# Generated deterministically by seda-macro-lef-normalizer-v1; recipe orfs-ng45-fakeram-metal3-coupledl2-pg-v1.
VERSION 5.8 ;
BUSBITCHARS "[]" ;
DIVIDERCHAR "/" ;

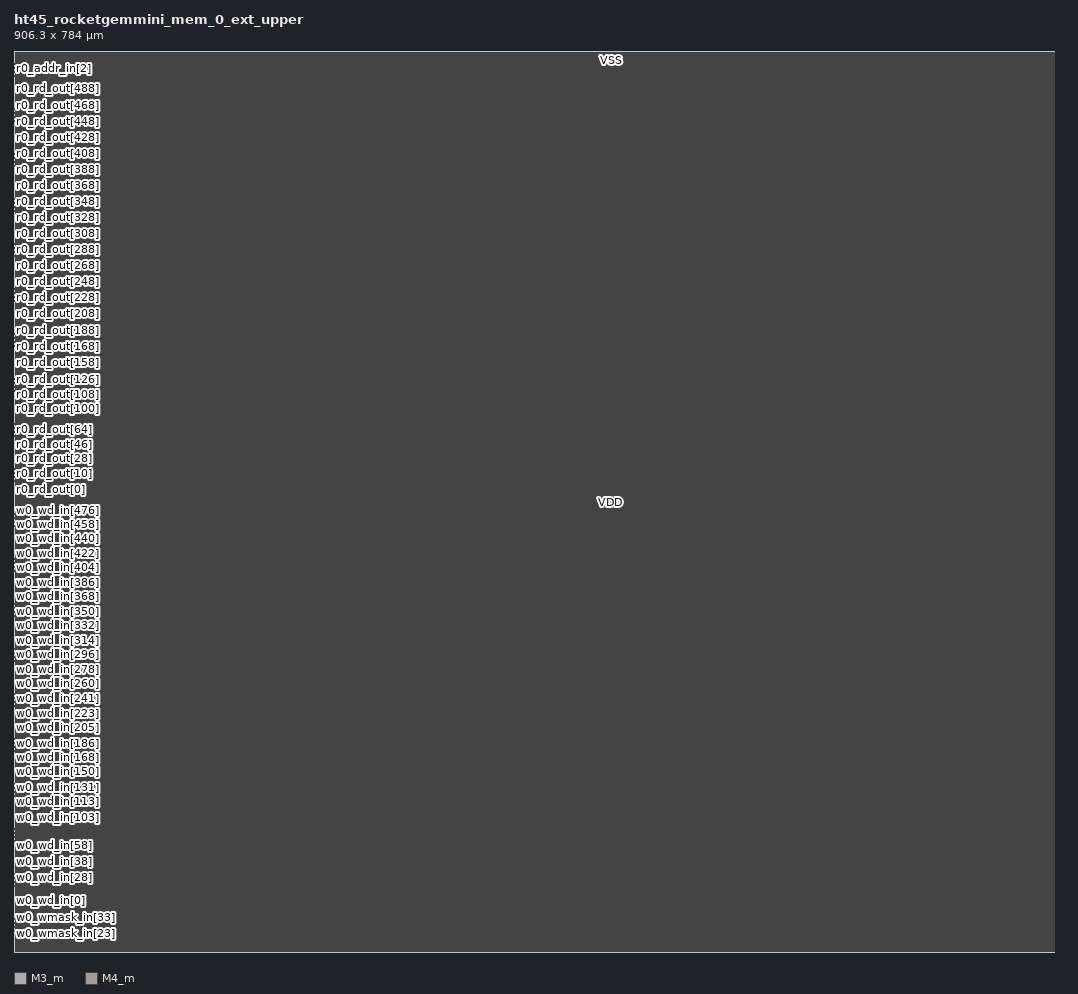
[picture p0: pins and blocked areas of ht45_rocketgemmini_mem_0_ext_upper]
MACRO ht45_rocketgemmini_mem_0_ext_upper
  FOREIGN ht45_rocketgemmini_mem_0_ext_upper 0 0 ;
  CLASS BLOCK ;
  ORIGIN 0 0 ;
  SIZE 906.3 BY 784 ;
  SYMMETRY X Y R90 ;
  PIN w0_wmask_in[0]
    DIRECTION INPUT ;
    USE SIGNAL ;
    SHAPE ABUTMENT ;
    PORT
      LAYER M3_m ;
      RECT 0 0.035 0.07 0.105 ;
    END
  END w0_wmask_in[0]
  PIN w0_wmask_in[1]
    DIRECTION INPUT ;
    USE SIGNAL ;
    SHAPE ABUTMENT ;
    PORT
      LAYER M3_m ;
      RECT 0 0.735 0.07 0.805 ;
    END
  END w0_wmask_in[1]
  PIN w0_wmask_in[2]
    DIRECTION INPUT ;
    USE SIGNAL ;
    SHAPE ABUTMENT ;
    PORT
      LAYER M3_m ;
      RECT 0 1.435 0.07 1.505 ;
    END
  END w0_wmask_in[2]
  PIN w0_wmask_in[3]
    DIRECTION INPUT ;
    USE SIGNAL ;
    SHAPE ABUTMENT ;
    PORT
      LAYER M3_m ;
      RECT 0 2.135 0.07 2.205 ;
    END
  END w0_wmask_in[3]
  PIN w0_wmask_in[4]
    DIRECTION INPUT ;
    USE SIGNAL ;
    SHAPE ABUTMENT ;
    PORT
      LAYER M3_m ;
      RECT 0 2.835 0.07 2.905 ;
    END
  END w0_wmask_in[4]
  PIN w0_wmask_in[5]
    DIRECTION INPUT ;
    USE SIGNAL ;
    SHAPE ABUTMENT ;
    PORT
      LAYER M3_m ;
      RECT 0 3.535 0.07 3.605 ;
    END
  END w0_wmask_in[5]
  PIN w0_wmask_in[6]
    DIRECTION INPUT ;
    USE SIGNAL ;
    SHAPE ABUTMENT ;
    PORT
      LAYER M3_m ;
      RECT 0 4.235 0.07 4.305 ;
    END
  END w0_wmask_in[6]
  PIN w0_wmask_in[7]
    DIRECTION INPUT ;
    USE SIGNAL ;
    SHAPE ABUTMENT ;
    PORT
      LAYER M3_m ;
      RECT 0 4.935 0.07 5.005 ;
    END
  END w0_wmask_in[7]
  PIN w0_wmask_in[8]
    DIRECTION INPUT ;
    USE SIGNAL ;
    SHAPE ABUTMENT ;
    PORT
      LAYER M3_m ;
      RECT 0 5.635 0.07 5.705 ;
    END
  END w0_wmask_in[8]
  PIN w0_wmask_in[9]
    DIRECTION INPUT ;
    USE SIGNAL ;
    SHAPE ABUTMENT ;
    PORT
      LAYER M3_m ;
      RECT 0 6.335 0.07 6.405 ;
    END
  END w0_wmask_in[9]
  PIN w0_wmask_in[10]
    DIRECTION INPUT ;
    USE SIGNAL ;
    SHAPE ABUTMENT ;
    PORT
      LAYER M3_m ;
      RECT 0 7.035 0.07 7.105 ;
    END
  END w0_wmask_in[10]
  PIN w0_wmask_in[11]
    DIRECTION INPUT ;
    USE SIGNAL ;
    SHAPE ABUTMENT ;
    PORT
      LAYER M3_m ;
      RECT 0 7.735 0.07 7.805 ;
    END
  END w0_wmask_in[11]
  PIN w0_wmask_in[12]
    DIRECTION INPUT ;
    USE SIGNAL ;
    SHAPE ABUTMENT ;
    PORT
      LAYER M3_m ;
      RECT 0 8.435 0.07 8.505 ;
    END
  END w0_wmask_in[12]
  PIN w0_wmask_in[13]
    DIRECTION INPUT ;
    USE SIGNAL ;
    SHAPE ABUTMENT ;
    PORT
      LAYER M3_m ;
      RECT 0 9.135 0.07 9.205 ;
    END
  END w0_wmask_in[13]
  PIN w0_wmask_in[14]
    DIRECTION INPUT ;
    USE SIGNAL ;
    SHAPE ABUTMENT ;
    PORT
      LAYER M3_m ;
      RECT 0 9.835 0.07 9.905 ;
    END
  END w0_wmask_in[14]
  PIN w0_wmask_in[15]
    DIRECTION INPUT ;
    USE SIGNAL ;
    SHAPE ABUTMENT ;
    PORT
      LAYER M3_m ;
      RECT 0 10.535 0.07 10.605 ;
    END
  END w0_wmask_in[15]
  PIN w0_wmask_in[16]
    DIRECTION INPUT ;
    USE SIGNAL ;
    SHAPE ABUTMENT ;
    PORT
      LAYER M3_m ;
      RECT 0 11.235 0.07 11.305 ;
    END
  END w0_wmask_in[16]
  PIN w0_wmask_in[17]
    DIRECTION INPUT ;
    USE SIGNAL ;
    SHAPE ABUTMENT ;
    PORT
      LAYER M3_m ;
      RECT 0 11.935 0.07 12.005 ;
    END
  END w0_wmask_in[17]
  PIN w0_wmask_in[18]
    DIRECTION INPUT ;
    USE SIGNAL ;
    SHAPE ABUTMENT ;
    PORT
      LAYER M3_m ;
      RECT 0 12.635 0.07 12.705 ;
    END
  END w0_wmask_in[18]
  PIN w0_wmask_in[19]
    DIRECTION INPUT ;
    USE SIGNAL ;
    SHAPE ABUTMENT ;
    PORT
      LAYER M3_m ;
      RECT 0 13.335 0.07 13.405 ;
    END
  END w0_wmask_in[19]
  PIN w0_wmask_in[20]
    DIRECTION INPUT ;
    USE SIGNAL ;
    SHAPE ABUTMENT ;
    PORT
      LAYER M3_m ;
      RECT 0 14.035 0.07 14.105 ;
    END
  END w0_wmask_in[20]
  PIN w0_wmask_in[21]
    DIRECTION INPUT ;
    USE SIGNAL ;
    SHAPE ABUTMENT ;
    PORT
      LAYER M3_m ;
      RECT 0 14.735 0.07 14.805 ;
    END
  END w0_wmask_in[21]
  PIN w0_wmask_in[22]
    DIRECTION INPUT ;
    USE SIGNAL ;
    SHAPE ABUTMENT ;
    PORT
      LAYER M3_m ;
      RECT 0 15.435 0.07 15.505 ;
    END
  END w0_wmask_in[22]
  PIN w0_wmask_in[23]
    DIRECTION INPUT ;
    USE SIGNAL ;
    SHAPE ABUTMENT ;
    PORT
      LAYER M3_m ;
      RECT 0 16.135 0.07 16.205 ;
    END
  END w0_wmask_in[23]
  PIN w0_wmask_in[24]
    DIRECTION INPUT ;
    USE SIGNAL ;
    SHAPE ABUTMENT ;
    PORT
      LAYER M3_m ;
      RECT 0 16.835 0.07 16.905 ;
    END
  END w0_wmask_in[24]
  PIN w0_wmask_in[25]
    DIRECTION INPUT ;
    USE SIGNAL ;
    SHAPE ABUTMENT ;
    PORT
      LAYER M3_m ;
      RECT 0 17.535 0.07 17.605 ;
    END
  END w0_wmask_in[25]
  PIN w0_wmask_in[26]
    DIRECTION INPUT ;
    USE SIGNAL ;
    SHAPE ABUTMENT ;
    PORT
      LAYER M3_m ;
      RECT 0 18.235 0.07 18.305 ;
    END
  END w0_wmask_in[26]
  PIN w0_wmask_in[27]
    DIRECTION INPUT ;
    USE SIGNAL ;
    SHAPE ABUTMENT ;
    PORT
      LAYER M3_m ;
      RECT 0 18.935 0.07 19.005 ;
    END
  END w0_wmask_in[27]
  PIN w0_wmask_in[28]
    DIRECTION INPUT ;
    USE SIGNAL ;
    SHAPE ABUTMENT ;
    PORT
      LAYER M3_m ;
      RECT 0 19.635 0.07 19.705 ;
    END
  END w0_wmask_in[28]
  PIN w0_wmask_in[29]
    DIRECTION INPUT ;
    USE SIGNAL ;
    SHAPE ABUTMENT ;
    PORT
      LAYER M3_m ;
      RECT 0 20.335 0.07 20.405 ;
    END
  END w0_wmask_in[29]
  PIN w0_wmask_in[30]
    DIRECTION INPUT ;
    USE SIGNAL ;
    SHAPE ABUTMENT ;
    PORT
      LAYER M3_m ;
      RECT 0 21.035 0.07 21.105 ;
    END
  END w0_wmask_in[30]
  PIN w0_wmask_in[31]
    DIRECTION INPUT ;
    USE SIGNAL ;
    SHAPE ABUTMENT ;
    PORT
      LAYER M3_m ;
      RECT 0 21.735 0.07 21.805 ;
    END
  END w0_wmask_in[31]
  PIN w0_wmask_in[32]
    DIRECTION INPUT ;
    USE SIGNAL ;
    SHAPE ABUTMENT ;
    PORT
      LAYER M3_m ;
      RECT 0 22.435 0.07 22.505 ;
    END
  END w0_wmask_in[32]
  PIN w0_wmask_in[33]
    DIRECTION INPUT ;
    USE SIGNAL ;
    SHAPE ABUTMENT ;
    PORT
      LAYER M3_m ;
      RECT 0 23.135 0.07 23.205 ;
    END
  END w0_wmask_in[33]
  PIN w0_wmask_in[34]
    DIRECTION INPUT ;
    USE SIGNAL ;
    SHAPE ABUTMENT ;
    PORT
      LAYER M3_m ;
      RECT 0 23.835 0.07 23.905 ;
    END
  END w0_wmask_in[34]
  PIN w0_wmask_in[35]
    DIRECTION INPUT ;
    USE SIGNAL ;
    SHAPE ABUTMENT ;
    PORT
      LAYER M3_m ;
      RECT 0 24.535 0.07 24.605 ;
    END
  END w0_wmask_in[35]
  PIN w0_wmask_in[36]
    DIRECTION INPUT ;
    USE SIGNAL ;
    SHAPE ABUTMENT ;
    PORT
      LAYER M3_m ;
      RECT 0 25.235 0.07 25.305 ;
    END
  END w0_wmask_in[36]
  PIN w0_wmask_in[37]
    DIRECTION INPUT ;
    USE SIGNAL ;
    SHAPE ABUTMENT ;
    PORT
      LAYER M3_m ;
      RECT 0 25.935 0.07 26.005 ;
    END
  END w0_wmask_in[37]
  PIN w0_wmask_in[38]
    DIRECTION INPUT ;
    USE SIGNAL ;
    SHAPE ABUTMENT ;
    PORT
      LAYER M3_m ;
      RECT 0 26.635 0.07 26.705 ;
    END
  END w0_wmask_in[38]
  PIN w0_wmask_in[39]
    DIRECTION INPUT ;
    USE SIGNAL ;
    SHAPE ABUTMENT ;
    PORT
      LAYER M3_m ;
      RECT 0 27.335 0.07 27.405 ;
    END
  END w0_wmask_in[39]
  PIN w0_wmask_in[40]
    DIRECTION INPUT ;
    USE SIGNAL ;
    SHAPE ABUTMENT ;
    PORT
      LAYER M3_m ;
      RECT 0 28.035 0.07 28.105 ;
    END
  END w0_wmask_in[40]
  PIN w0_wmask_in[41]
    DIRECTION INPUT ;
    USE SIGNAL ;
    SHAPE ABUTMENT ;
    PORT
      LAYER M3_m ;
      RECT 0 28.735 0.07 28.805 ;
    END
  END w0_wmask_in[41]
  PIN w0_wmask_in[42]
    DIRECTION INPUT ;
    USE SIGNAL ;
    SHAPE ABUTMENT ;
    PORT
      LAYER M3_m ;
      RECT 0 29.435 0.07 29.505 ;
    END
  END w0_wmask_in[42]
  PIN w0_wmask_in[43]
    DIRECTION INPUT ;
    USE SIGNAL ;
    SHAPE ABUTMENT ;
    PORT
      LAYER M3_m ;
      RECT 0 30.135 0.07 30.205 ;
    END
  END w0_wmask_in[43]
  PIN w0_wmask_in[44]
    DIRECTION INPUT ;
    USE SIGNAL ;
    SHAPE ABUTMENT ;
    PORT
      LAYER M3_m ;
      RECT 0 30.835 0.07 30.905 ;
    END
  END w0_wmask_in[44]
  PIN w0_wmask_in[45]
    DIRECTION INPUT ;
    USE SIGNAL ;
    SHAPE ABUTMENT ;
    PORT
      LAYER M3_m ;
      RECT 0 31.535 0.07 31.605 ;
    END
  END w0_wmask_in[45]
  PIN w0_wmask_in[46]
    DIRECTION INPUT ;
    USE SIGNAL ;
    SHAPE ABUTMENT ;
    PORT
      LAYER M3_m ;
      RECT 0 32.235 0.07 32.305 ;
    END
  END w0_wmask_in[46]
  PIN w0_wmask_in[47]
    DIRECTION INPUT ;
    USE SIGNAL ;
    SHAPE ABUTMENT ;
    PORT
      LAYER M3_m ;
      RECT 0 32.935 0.07 33.005 ;
    END
  END w0_wmask_in[47]
  PIN w0_wmask_in[48]
    DIRECTION INPUT ;
    USE SIGNAL ;
    SHAPE ABUTMENT ;
    PORT
      LAYER M3_m ;
      RECT 0 33.635 0.07 33.705 ;
    END
  END w0_wmask_in[48]
  PIN w0_wmask_in[49]
    DIRECTION INPUT ;
    USE SIGNAL ;
    SHAPE ABUTMENT ;
    PORT
      LAYER M3_m ;
      RECT 0 34.335 0.07 34.405 ;
    END
  END w0_wmask_in[49]
  PIN w0_wmask_in[50]
    DIRECTION INPUT ;
    USE SIGNAL ;
    SHAPE ABUTMENT ;
    PORT
      LAYER M3_m ;
      RECT 0 35.035 0.07 35.105 ;
    END
  END w0_wmask_in[50]
  PIN w0_wmask_in[51]
    DIRECTION INPUT ;
    USE SIGNAL ;
    SHAPE ABUTMENT ;
    PORT
      LAYER M3_m ;
      RECT 0 35.735 0.07 35.805 ;
    END
  END w0_wmask_in[51]
  PIN w0_wmask_in[52]
    DIRECTION INPUT ;
    USE SIGNAL ;
    SHAPE ABUTMENT ;
    PORT
      LAYER M3_m ;
      RECT 0 36.435 0.07 36.505 ;
    END
  END w0_wmask_in[52]
  PIN w0_wmask_in[53]
    DIRECTION INPUT ;
    USE SIGNAL ;
    SHAPE ABUTMENT ;
    PORT
      LAYER M3_m ;
      RECT 0 37.135 0.07 37.205 ;
    END
  END w0_wmask_in[53]
  PIN w0_wmask_in[54]
    DIRECTION INPUT ;
    USE SIGNAL ;
    SHAPE ABUTMENT ;
    PORT
      LAYER M3_m ;
      RECT 0 37.835 0.07 37.905 ;
    END
  END w0_wmask_in[54]
  PIN w0_wmask_in[55]
    DIRECTION INPUT ;
    USE SIGNAL ;
    SHAPE ABUTMENT ;
    PORT
      LAYER M3_m ;
      RECT 0 38.535 0.07 38.605 ;
    END
  END w0_wmask_in[55]
  PIN w0_wmask_in[56]
    DIRECTION INPUT ;
    USE SIGNAL ;
    SHAPE ABUTMENT ;
    PORT
      LAYER M3_m ;
      RECT 0 39.235 0.07 39.305 ;
    END
  END w0_wmask_in[56]
  PIN w0_wmask_in[57]
    DIRECTION INPUT ;
    USE SIGNAL ;
    SHAPE ABUTMENT ;
    PORT
      LAYER M3_m ;
      RECT 0 39.935 0.07 40.005 ;
    END
  END w0_wmask_in[57]
  PIN w0_wmask_in[58]
    DIRECTION INPUT ;
    USE SIGNAL ;
    SHAPE ABUTMENT ;
    PORT
      LAYER M3_m ;
      RECT 0 40.635 0.07 40.705 ;
    END
  END w0_wmask_in[58]
  PIN w0_wmask_in[59]
    DIRECTION INPUT ;
    USE SIGNAL ;
    SHAPE ABUTMENT ;
    PORT
      LAYER M3_m ;
      RECT 0 41.335 0.07 41.405 ;
    END
  END w0_wmask_in[59]
  PIN w0_wmask_in[60]
    DIRECTION INPUT ;
    USE SIGNAL ;
    SHAPE ABUTMENT ;
    PORT
      LAYER M3_m ;
      RECT 0 42.035 0.07 42.105 ;
    END
  END w0_wmask_in[60]
  PIN w0_wmask_in[61]
    DIRECTION INPUT ;
    USE SIGNAL ;
    SHAPE ABUTMENT ;
    PORT
      LAYER M3_m ;
      RECT 0 42.735 0.07 42.805 ;
    END
  END w0_wmask_in[61]
  PIN w0_wmask_in[62]
    DIRECTION INPUT ;
    USE SIGNAL ;
    SHAPE ABUTMENT ;
    PORT
      LAYER M3_m ;
      RECT 0 43.435 0.07 43.505 ;
    END
  END w0_wmask_in[62]
  PIN w0_wmask_in[63]
    DIRECTION INPUT ;
    USE SIGNAL ;
    SHAPE ABUTMENT ;
    PORT
      LAYER M3_m ;
      RECT 0 44.135 0.07 44.205 ;
    END
  END w0_wmask_in[63]
  PIN w0_wd_in[0]
    DIRECTION INPUT ;
    USE SIGNAL ;
    SHAPE ABUTMENT ;
    PORT
      LAYER M3_m ;
      RECT 0 44.835 0.07 44.905 ;
    END
  END w0_wd_in[0]
  PIN w0_wd_in[1]
    DIRECTION INPUT ;
    USE SIGNAL ;
    SHAPE ABUTMENT ;
    PORT
      LAYER M3_m ;
      RECT 0 45.535 0.07 45.605 ;
    END
  END w0_wd_in[1]
  PIN w0_wd_in[2]
    DIRECTION INPUT ;
    USE SIGNAL ;
    SHAPE ABUTMENT ;
    PORT
      LAYER M3_m ;
      RECT 0 46.235 0.07 46.305 ;
    END
  END w0_wd_in[2]
  PIN w0_wd_in[3]
    DIRECTION INPUT ;
    USE SIGNAL ;
    SHAPE ABUTMENT ;
    PORT
      LAYER M3_m ;
      RECT 0 46.935 0.07 47.005 ;
    END
  END w0_wd_in[3]
  PIN w0_wd_in[4]
    DIRECTION INPUT ;
    USE SIGNAL ;
    SHAPE ABUTMENT ;
    PORT
      LAYER M3_m ;
      RECT 0 47.635 0.07 47.705 ;
    END
  END w0_wd_in[4]
  PIN w0_wd_in[5]
    DIRECTION INPUT ;
    USE SIGNAL ;
    SHAPE ABUTMENT ;
    PORT
      LAYER M3_m ;
      RECT 0 48.335 0.07 48.405 ;
    END
  END w0_wd_in[5]
  PIN w0_wd_in[6]
    DIRECTION INPUT ;
    USE SIGNAL ;
    SHAPE ABUTMENT ;
    PORT
      LAYER M3_m ;
      RECT 0 49.035 0.07 49.105 ;
    END
  END w0_wd_in[6]
  PIN w0_wd_in[7]
    DIRECTION INPUT ;
    USE SIGNAL ;
    SHAPE ABUTMENT ;
    PORT
      LAYER M3_m ;
      RECT 0 49.735 0.07 49.805 ;
    END
  END w0_wd_in[7]
  PIN w0_wd_in[8]
    DIRECTION INPUT ;
    USE SIGNAL ;
    SHAPE ABUTMENT ;
    PORT
      LAYER M3_m ;
      RECT 0 50.435 0.07 50.505 ;
    END
  END w0_wd_in[8]
  PIN w0_wd_in[9]
    DIRECTION INPUT ;
    USE SIGNAL ;
    SHAPE ABUTMENT ;
    PORT
      LAYER M3_m ;
      RECT 0 51.135 0.07 51.205 ;
    END
  END w0_wd_in[9]
  PIN w0_wd_in[10]
    DIRECTION INPUT ;
    USE SIGNAL ;
    SHAPE ABUTMENT ;
    PORT
      LAYER M3_m ;
      RECT 0 51.835 0.07 51.905 ;
    END
  END w0_wd_in[10]
  PIN w0_wd_in[11]
    DIRECTION INPUT ;
    USE SIGNAL ;
    SHAPE ABUTMENT ;
    PORT
      LAYER M3_m ;
      RECT 0 52.535 0.07 52.605 ;
    END
  END w0_wd_in[11]
  PIN w0_wd_in[12]
    DIRECTION INPUT ;
    USE SIGNAL ;
    SHAPE ABUTMENT ;
    PORT
      LAYER M3_m ;
      RECT 0 53.235 0.07 53.305 ;
    END
  END w0_wd_in[12]
  PIN w0_wd_in[13]
    DIRECTION INPUT ;
    USE SIGNAL ;
    SHAPE ABUTMENT ;
    PORT
      LAYER M3_m ;
      RECT 0 53.935 0.07 54.005 ;
    END
  END w0_wd_in[13]
  PIN w0_wd_in[14]
    DIRECTION INPUT ;
    USE SIGNAL ;
    SHAPE ABUTMENT ;
    PORT
      LAYER M3_m ;
      RECT 0 54.635 0.07 54.705 ;
    END
  END w0_wd_in[14]
  PIN w0_wd_in[15]
    DIRECTION INPUT ;
    USE SIGNAL ;
    SHAPE ABUTMENT ;
    PORT
      LAYER M3_m ;
      RECT 0 55.335 0.07 55.405 ;
    END
  END w0_wd_in[15]
  PIN w0_wd_in[16]
    DIRECTION INPUT ;
    USE SIGNAL ;
    SHAPE ABUTMENT ;
    PORT
      LAYER M3_m ;
      RECT 0 56.035 0.07 56.105 ;
    END
  END w0_wd_in[16]
  PIN w0_wd_in[17]
    DIRECTION INPUT ;
    USE SIGNAL ;
    SHAPE ABUTMENT ;
    PORT
      LAYER M3_m ;
      RECT 0 56.735 0.07 56.805 ;
    END
  END w0_wd_in[17]
  PIN w0_wd_in[18]
    DIRECTION INPUT ;
    USE SIGNAL ;
    SHAPE ABUTMENT ;
    PORT
      LAYER M3_m ;
      RECT 0 57.435 0.07 57.505 ;
    END
  END w0_wd_in[18]
  PIN w0_wd_in[19]
    DIRECTION INPUT ;
    USE SIGNAL ;
    SHAPE ABUTMENT ;
    PORT
      LAYER M3_m ;
      RECT 0 58.135 0.07 58.205 ;
    END
  END w0_wd_in[19]
  PIN w0_wd_in[20]
    DIRECTION INPUT ;
    USE SIGNAL ;
    SHAPE ABUTMENT ;
    PORT
      LAYER M3_m ;
      RECT 0 58.835 0.07 58.905 ;
    END
  END w0_wd_in[20]
  PIN w0_wd_in[21]
    DIRECTION INPUT ;
    USE SIGNAL ;
    SHAPE ABUTMENT ;
    PORT
      LAYER M3_m ;
      RECT 0 59.535 0.07 59.605 ;
    END
  END w0_wd_in[21]
  PIN w0_wd_in[22]
    DIRECTION INPUT ;
    USE SIGNAL ;
    SHAPE ABUTMENT ;
    PORT
      LAYER M3_m ;
      RECT 0 60.235 0.07 60.305 ;
    END
  END w0_wd_in[22]
  PIN w0_wd_in[23]
    DIRECTION INPUT ;
    USE SIGNAL ;
    SHAPE ABUTMENT ;
    PORT
      LAYER M3_m ;
      RECT 0 60.935 0.07 61.005 ;
    END
  END w0_wd_in[23]
  PIN w0_wd_in[24]
    DIRECTION INPUT ;
    USE SIGNAL ;
    SHAPE ABUTMENT ;
    PORT
      LAYER M3_m ;
      RECT 0 61.635 0.07 61.705 ;
    END
  END w0_wd_in[24]
  PIN w0_wd_in[25]
    DIRECTION INPUT ;
    USE SIGNAL ;
    SHAPE ABUTMENT ;
    PORT
      LAYER M3_m ;
      RECT 0 62.335 0.07 62.405 ;
    END
  END w0_wd_in[25]
  PIN w0_wd_in[26]
    DIRECTION INPUT ;
    USE SIGNAL ;
    SHAPE ABUTMENT ;
    PORT
      LAYER M3_m ;
      RECT 0 63.035 0.07 63.105 ;
    END
  END w0_wd_in[26]
  PIN w0_wd_in[27]
    DIRECTION INPUT ;
    USE SIGNAL ;
    SHAPE ABUTMENT ;
    PORT
      LAYER M3_m ;
      RECT 0 63.735 0.07 63.805 ;
    END
  END w0_wd_in[27]
  PIN w0_wd_in[28]
    DIRECTION INPUT ;
    USE SIGNAL ;
    SHAPE ABUTMENT ;
    PORT
      LAYER M3_m ;
      RECT 0 64.435 0.07 64.505 ;
    END
  END w0_wd_in[28]
  PIN w0_wd_in[29]
    DIRECTION INPUT ;
    USE SIGNAL ;
    SHAPE ABUTMENT ;
    PORT
      LAYER M3_m ;
      RECT 0 65.135 0.07 65.205 ;
    END
  END w0_wd_in[29]
  PIN w0_wd_in[30]
    DIRECTION INPUT ;
    USE SIGNAL ;
    SHAPE ABUTMENT ;
    PORT
      LAYER M3_m ;
      RECT 0 65.835 0.07 65.905 ;
    END
  END w0_wd_in[30]
  PIN w0_wd_in[31]
    DIRECTION INPUT ;
    USE SIGNAL ;
    SHAPE ABUTMENT ;
    PORT
      LAYER M3_m ;
      RECT 0 66.535 0.07 66.605 ;
    END
  END w0_wd_in[31]
  PIN w0_wd_in[32]
    DIRECTION INPUT ;
    USE SIGNAL ;
    SHAPE ABUTMENT ;
    PORT
      LAYER M3_m ;
      RECT 0 67.235 0.07 67.305 ;
    END
  END w0_wd_in[32]
  PIN w0_wd_in[33]
    DIRECTION INPUT ;
    USE SIGNAL ;
    SHAPE ABUTMENT ;
    PORT
      LAYER M3_m ;
      RECT 0 67.935 0.07 68.005 ;
    END
  END w0_wd_in[33]
  PIN w0_wd_in[34]
    DIRECTION INPUT ;
    USE SIGNAL ;
    SHAPE ABUTMENT ;
    PORT
      LAYER M3_m ;
      RECT 0 68.635 0.07 68.705 ;
    END
  END w0_wd_in[34]
  PIN w0_wd_in[35]
    DIRECTION INPUT ;
    USE SIGNAL ;
    SHAPE ABUTMENT ;
    PORT
      LAYER M3_m ;
      RECT 0 69.335 0.07 69.405 ;
    END
  END w0_wd_in[35]
  PIN w0_wd_in[36]
    DIRECTION INPUT ;
    USE SIGNAL ;
    SHAPE ABUTMENT ;
    PORT
      LAYER M3_m ;
      RECT 0 70.035 0.07 70.105 ;
    END
  END w0_wd_in[36]
  PIN w0_wd_in[37]
    DIRECTION INPUT ;
    USE SIGNAL ;
    SHAPE ABUTMENT ;
    PORT
      LAYER M3_m ;
      RECT 0 70.735 0.07 70.805 ;
    END
  END w0_wd_in[37]
  PIN w0_wd_in[38]
    DIRECTION INPUT ;
    USE SIGNAL ;
    SHAPE ABUTMENT ;
    PORT
      LAYER M3_m ;
      RECT 0 71.435 0.07 71.505 ;
    END
  END w0_wd_in[38]
  PIN w0_wd_in[39]
    DIRECTION INPUT ;
    USE SIGNAL ;
    SHAPE ABUTMENT ;
    PORT
      LAYER M3_m ;
      RECT 0 72.135 0.07 72.205 ;
    END
  END w0_wd_in[39]
  PIN w0_wd_in[40]
    DIRECTION INPUT ;
    USE SIGNAL ;
    SHAPE ABUTMENT ;
    PORT
      LAYER M3_m ;
      RECT 0 72.835 0.07 72.905 ;
    END
  END w0_wd_in[40]
  PIN w0_wd_in[41]
    DIRECTION INPUT ;
    USE SIGNAL ;
    SHAPE ABUTMENT ;
    PORT
      LAYER M3_m ;
      RECT 0 73.535 0.07 73.605 ;
    END
  END w0_wd_in[41]
  PIN w0_wd_in[42]
    DIRECTION INPUT ;
    USE SIGNAL ;
    SHAPE ABUTMENT ;
    PORT
      LAYER M3_m ;
      RECT 0 74.235 0.07 74.305 ;
    END
  END w0_wd_in[42]
  PIN w0_wd_in[43]
    DIRECTION INPUT ;
    USE SIGNAL ;
    SHAPE ABUTMENT ;
    PORT
      LAYER M3_m ;
      RECT 0 74.935 0.07 75.005 ;
    END
  END w0_wd_in[43]
  PIN w0_wd_in[44]
    DIRECTION INPUT ;
    USE SIGNAL ;
    SHAPE ABUTMENT ;
    PORT
      LAYER M3_m ;
      RECT 0 75.635 0.07 75.705 ;
    END
  END w0_wd_in[44]
  PIN w0_wd_in[45]
    DIRECTION INPUT ;
    USE SIGNAL ;
    SHAPE ABUTMENT ;
    PORT
      LAYER M3_m ;
      RECT 0 76.335 0.07 76.405 ;
    END
  END w0_wd_in[45]
  PIN w0_wd_in[46]
    DIRECTION INPUT ;
    USE SIGNAL ;
    SHAPE ABUTMENT ;
    PORT
      LAYER M3_m ;
      RECT 0 77.035 0.07 77.105 ;
    END
  END w0_wd_in[46]
  PIN w0_wd_in[47]
    DIRECTION INPUT ;
    USE SIGNAL ;
    SHAPE ABUTMENT ;
    PORT
      LAYER M3_m ;
      RECT 0 77.735 0.07 77.805 ;
    END
  END w0_wd_in[47]
  PIN w0_wd_in[48]
    DIRECTION INPUT ;
    USE SIGNAL ;
    SHAPE ABUTMENT ;
    PORT
      LAYER M3_m ;
      RECT 0 78.435 0.07 78.505 ;
    END
  END w0_wd_in[48]
  PIN w0_wd_in[49]
    DIRECTION INPUT ;
    USE SIGNAL ;
    SHAPE ABUTMENT ;
    PORT
      LAYER M3_m ;
      RECT 0 79.135 0.07 79.205 ;
    END
  END w0_wd_in[49]
  PIN w0_wd_in[50]
    DIRECTION INPUT ;
    USE SIGNAL ;
    SHAPE ABUTMENT ;
    PORT
      LAYER M3_m ;
      RECT 0 79.835 0.07 79.905 ;
    END
  END w0_wd_in[50]
  PIN w0_wd_in[51]
    DIRECTION INPUT ;
    USE SIGNAL ;
    SHAPE ABUTMENT ;
    PORT
      LAYER M3_m ;
      RECT 0 80.535 0.07 80.605 ;
    END
  END w0_wd_in[51]
  PIN w0_wd_in[52]
    DIRECTION INPUT ;
    USE SIGNAL ;
    SHAPE ABUTMENT ;
    PORT
      LAYER M3_m ;
      RECT 0 81.235 0.07 81.305 ;
    END
  END w0_wd_in[52]
  PIN w0_wd_in[53]
    DIRECTION INPUT ;
    USE SIGNAL ;
    SHAPE ABUTMENT ;
    PORT
      LAYER M3_m ;
      RECT 0 81.935 0.07 82.005 ;
    END
  END w0_wd_in[53]
  PIN w0_wd_in[54]
    DIRECTION INPUT ;
    USE SIGNAL ;
    SHAPE ABUTMENT ;
    PORT
      LAYER M3_m ;
      RECT 0 82.635 0.07 82.705 ;
    END
  END w0_wd_in[54]
  PIN w0_wd_in[55]
    DIRECTION INPUT ;
    USE SIGNAL ;
    SHAPE ABUTMENT ;
    PORT
      LAYER M3_m ;
      RECT 0 83.335 0.07 83.405 ;
    END
  END w0_wd_in[55]
  PIN w0_wd_in[56]
    DIRECTION INPUT ;
    USE SIGNAL ;
    SHAPE ABUTMENT ;
    PORT
      LAYER M3_m ;
      RECT 0 84.035 0.07 84.105 ;
    END
  END w0_wd_in[56]
  PIN w0_wd_in[57]
    DIRECTION INPUT ;
    USE SIGNAL ;
    SHAPE ABUTMENT ;
    PORT
      LAYER M3_m ;
      RECT 0 84.735 0.07 84.805 ;
    END
  END w0_wd_in[57]
  PIN w0_wd_in[58]
    DIRECTION INPUT ;
    USE SIGNAL ;
    SHAPE ABUTMENT ;
    PORT
      LAYER M3_m ;
      RECT 0 85.435 0.07 85.505 ;
    END
  END w0_wd_in[58]
  PIN w0_wd_in[59]
    DIRECTION INPUT ;
    USE SIGNAL ;
    SHAPE ABUTMENT ;
    PORT
      LAYER M3_m ;
      RECT 0 86.135 0.07 86.205 ;
    END
  END w0_wd_in[59]
  PIN w0_wd_in[60]
    DIRECTION INPUT ;
    USE SIGNAL ;
    SHAPE ABUTMENT ;
    PORT
      LAYER M3_m ;
      RECT 0 86.835 0.07 86.905 ;
    END
  END w0_wd_in[60]
  PIN w0_wd_in[61]
    DIRECTION INPUT ;
    USE SIGNAL ;
    SHAPE ABUTMENT ;
    PORT
      LAYER M3_m ;
      RECT 0 87.535 0.07 87.605 ;
    END
  END w0_wd_in[61]
  PIN w0_wd_in[62]
    DIRECTION INPUT ;
    USE SIGNAL ;
    SHAPE ABUTMENT ;
    PORT
      LAYER M3_m ;
      RECT 0 88.235 0.07 88.305 ;
    END
  END w0_wd_in[62]
  PIN w0_wd_in[63]
    DIRECTION INPUT ;
    USE SIGNAL ;
    SHAPE ABUTMENT ;
    PORT
      LAYER M3_m ;
      RECT 0 88.935 0.07 89.005 ;
    END
  END w0_wd_in[63]
  PIN w0_wd_in[64]
    DIRECTION INPUT ;
    USE SIGNAL ;
    SHAPE ABUTMENT ;
    PORT
      LAYER M3_m ;
      RECT 0 89.635 0.07 89.705 ;
    END
  END w0_wd_in[64]
  PIN w0_wd_in[65]
    DIRECTION INPUT ;
    USE SIGNAL ;
    SHAPE ABUTMENT ;
    PORT
      LAYER M3_m ;
      RECT 0 90.335 0.07 90.405 ;
    END
  END w0_wd_in[65]
  PIN w0_wd_in[66]
    DIRECTION INPUT ;
    USE SIGNAL ;
    SHAPE ABUTMENT ;
    PORT
      LAYER M3_m ;
      RECT 0 91.035 0.07 91.105 ;
    END
  END w0_wd_in[66]
  PIN w0_wd_in[67]
    DIRECTION INPUT ;
    USE SIGNAL ;
    SHAPE ABUTMENT ;
    PORT
      LAYER M3_m ;
      RECT 0 91.735 0.07 91.805 ;
    END
  END w0_wd_in[67]
  PIN w0_wd_in[68]
    DIRECTION INPUT ;
    USE SIGNAL ;
    SHAPE ABUTMENT ;
    PORT
      LAYER M3_m ;
      RECT 0 92.435 0.07 92.505 ;
    END
  END w0_wd_in[68]
  PIN w0_wd_in[69]
    DIRECTION INPUT ;
    USE SIGNAL ;
    SHAPE ABUTMENT ;
    PORT
      LAYER M3_m ;
      RECT 0 93.135 0.07 93.205 ;
    END
  END w0_wd_in[69]
  PIN w0_wd_in[70]
    DIRECTION INPUT ;
    USE SIGNAL ;
    SHAPE ABUTMENT ;
    PORT
      LAYER M3_m ;
      RECT 0 93.835 0.07 93.905 ;
    END
  END w0_wd_in[70]
  PIN w0_wd_in[71]
    DIRECTION INPUT ;
    USE SIGNAL ;
    SHAPE ABUTMENT ;
    PORT
      LAYER M3_m ;
      RECT 0 94.535 0.07 94.605 ;
    END
  END w0_wd_in[71]
  PIN w0_wd_in[72]
    DIRECTION INPUT ;
    USE SIGNAL ;
    SHAPE ABUTMENT ;
    PORT
      LAYER M3_m ;
      RECT 0 95.235 0.07 95.305 ;
    END
  END w0_wd_in[72]
  PIN w0_wd_in[73]
    DIRECTION INPUT ;
    USE SIGNAL ;
    SHAPE ABUTMENT ;
    PORT
      LAYER M3_m ;
      RECT 0 95.935 0.07 96.005 ;
    END
  END w0_wd_in[73]
  PIN w0_wd_in[74]
    DIRECTION INPUT ;
    USE SIGNAL ;
    SHAPE ABUTMENT ;
    PORT
      LAYER M3_m ;
      RECT 0 96.635 0.07 96.705 ;
    END
  END w0_wd_in[74]
  PIN w0_wd_in[75]
    DIRECTION INPUT ;
    USE SIGNAL ;
    SHAPE ABUTMENT ;
    PORT
      LAYER M3_m ;
      RECT 0 97.335 0.07 97.405 ;
    END
  END w0_wd_in[75]
  PIN w0_wd_in[76]
    DIRECTION INPUT ;
    USE SIGNAL ;
    SHAPE ABUTMENT ;
    PORT
      LAYER M3_m ;
      RECT 0 98.035 0.07 98.105 ;
    END
  END w0_wd_in[76]
  PIN w0_wd_in[77]
    DIRECTION INPUT ;
    USE SIGNAL ;
    SHAPE ABUTMENT ;
    PORT
      LAYER M3_m ;
      RECT 0 98.735 0.07 98.805 ;
    END
  END w0_wd_in[77]
  PIN w0_wd_in[78]
    DIRECTION INPUT ;
    USE SIGNAL ;
    SHAPE ABUTMENT ;
    PORT
      LAYER M3_m ;
      RECT 0 99.435 0.07 99.505 ;
    END
  END w0_wd_in[78]
  PIN w0_wd_in[79]
    DIRECTION INPUT ;
    USE SIGNAL ;
    SHAPE ABUTMENT ;
    PORT
      LAYER M3_m ;
      RECT 0 100.135 0.07 100.205 ;
    END
  END w0_wd_in[79]
  PIN w0_wd_in[80]
    DIRECTION INPUT ;
    USE SIGNAL ;
    SHAPE ABUTMENT ;
    PORT
      LAYER M3_m ;
      RECT 0 100.835 0.07 100.905 ;
    END
  END w0_wd_in[80]
  PIN w0_wd_in[81]
    DIRECTION INPUT ;
    USE SIGNAL ;
    SHAPE ABUTMENT ;
    PORT
      LAYER M3_m ;
      RECT 0 101.535 0.07 101.605 ;
    END
  END w0_wd_in[81]
  PIN w0_wd_in[82]
    DIRECTION INPUT ;
    USE SIGNAL ;
    SHAPE ABUTMENT ;
    PORT
      LAYER M3_m ;
      RECT 0 102.235 0.07 102.305 ;
    END
  END w0_wd_in[82]
  PIN w0_wd_in[83]
    DIRECTION INPUT ;
    USE SIGNAL ;
    SHAPE ABUTMENT ;
    PORT
      LAYER M3_m ;
      RECT 0 102.935 0.07 103.005 ;
    END
  END w0_wd_in[83]
  PIN w0_wd_in[84]
    DIRECTION INPUT ;
    USE SIGNAL ;
    SHAPE ABUTMENT ;
    PORT
      LAYER M3_m ;
      RECT 0 103.635 0.07 103.705 ;
    END
  END w0_wd_in[84]
  PIN w0_wd_in[85]
    DIRECTION INPUT ;
    USE SIGNAL ;
    SHAPE ABUTMENT ;
    PORT
      LAYER M3_m ;
      RECT 0 104.335 0.07 104.405 ;
    END
  END w0_wd_in[85]
  PIN w0_wd_in[86]
    DIRECTION INPUT ;
    USE SIGNAL ;
    SHAPE ABUTMENT ;
    PORT
      LAYER M3_m ;
      RECT 0 105.035 0.07 105.105 ;
    END
  END w0_wd_in[86]
  PIN w0_wd_in[87]
    DIRECTION INPUT ;
    USE SIGNAL ;
    SHAPE ABUTMENT ;
    PORT
      LAYER M3_m ;
      RECT 0 105.735 0.07 105.805 ;
    END
  END w0_wd_in[87]
  PIN w0_wd_in[88]
    DIRECTION INPUT ;
    USE SIGNAL ;
    SHAPE ABUTMENT ;
    PORT
      LAYER M3_m ;
      RECT 0 106.435 0.07 106.505 ;
    END
  END w0_wd_in[88]
  PIN w0_wd_in[89]
    DIRECTION INPUT ;
    USE SIGNAL ;
    SHAPE ABUTMENT ;
    PORT
      LAYER M3_m ;
      RECT 0 107.135 0.07 107.205 ;
    END
  END w0_wd_in[89]
  PIN w0_wd_in[90]
    DIRECTION INPUT ;
    USE SIGNAL ;
    SHAPE ABUTMENT ;
    PORT
      LAYER M3_m ;
      RECT 0 107.835 0.07 107.905 ;
    END
  END w0_wd_in[90]
  PIN w0_wd_in[91]
    DIRECTION INPUT ;
    USE SIGNAL ;
    SHAPE ABUTMENT ;
    PORT
      LAYER M3_m ;
      RECT 0 108.535 0.07 108.605 ;
    END
  END w0_wd_in[91]
  PIN w0_wd_in[92]
    DIRECTION INPUT ;
    USE SIGNAL ;
    SHAPE ABUTMENT ;
    PORT
      LAYER M3_m ;
      RECT 0 109.235 0.07 109.305 ;
    END
  END w0_wd_in[92]
  PIN w0_wd_in[93]
    DIRECTION INPUT ;
    USE SIGNAL ;
    SHAPE ABUTMENT ;
    PORT
      LAYER M3_m ;
      RECT 0 109.935 0.07 110.005 ;
    END
  END w0_wd_in[93]
  PIN w0_wd_in[94]
    DIRECTION INPUT ;
    USE SIGNAL ;
    SHAPE ABUTMENT ;
    PORT
      LAYER M3_m ;
      RECT 0 110.635 0.07 110.705 ;
    END
  END w0_wd_in[94]
  PIN w0_wd_in[95]
    DIRECTION INPUT ;
    USE SIGNAL ;
    SHAPE ABUTMENT ;
    PORT
      LAYER M3_m ;
      RECT 0 111.335 0.07 111.405 ;
    END
  END w0_wd_in[95]
  PIN w0_wd_in[96]
    DIRECTION INPUT ;
    USE SIGNAL ;
    SHAPE ABUTMENT ;
    PORT
      LAYER M3_m ;
      RECT 0 112.035 0.07 112.105 ;
    END
  END w0_wd_in[96]
  PIN w0_wd_in[97]
    DIRECTION INPUT ;
    USE SIGNAL ;
    SHAPE ABUTMENT ;
    PORT
      LAYER M3_m ;
      RECT 0 112.735 0.07 112.805 ;
    END
  END w0_wd_in[97]
  PIN w0_wd_in[98]
    DIRECTION INPUT ;
    USE SIGNAL ;
    SHAPE ABUTMENT ;
    PORT
      LAYER M3_m ;
      RECT 0 113.435 0.07 113.505 ;
    END
  END w0_wd_in[98]
  PIN w0_wd_in[99]
    DIRECTION INPUT ;
    USE SIGNAL ;
    SHAPE ABUTMENT ;
    PORT
      LAYER M3_m ;
      RECT 0 114.135 0.07 114.205 ;
    END
  END w0_wd_in[99]
  PIN w0_wd_in[100]
    DIRECTION INPUT ;
    USE SIGNAL ;
    SHAPE ABUTMENT ;
    PORT
      LAYER M3_m ;
      RECT 0 114.835 0.07 114.905 ;
    END
  END w0_wd_in[100]
  PIN w0_wd_in[101]
    DIRECTION INPUT ;
    USE SIGNAL ;
    SHAPE ABUTMENT ;
    PORT
      LAYER M3_m ;
      RECT 0 115.535 0.07 115.605 ;
    END
  END w0_wd_in[101]
  PIN w0_wd_in[102]
    DIRECTION INPUT ;
    USE SIGNAL ;
    SHAPE ABUTMENT ;
    PORT
      LAYER M3_m ;
      RECT 0 116.235 0.07 116.305 ;
    END
  END w0_wd_in[102]
  PIN w0_wd_in[103]
    DIRECTION INPUT ;
    USE SIGNAL ;
    SHAPE ABUTMENT ;
    PORT
      LAYER M3_m ;
      RECT 0 116.935 0.07 117.005 ;
    END
  END w0_wd_in[103]
  PIN w0_wd_in[104]
    DIRECTION INPUT ;
    USE SIGNAL ;
    SHAPE ABUTMENT ;
    PORT
      LAYER M3_m ;
      RECT 0 117.635 0.07 117.705 ;
    END
  END w0_wd_in[104]
  PIN w0_wd_in[105]
    DIRECTION INPUT ;
    USE SIGNAL ;
    SHAPE ABUTMENT ;
    PORT
      LAYER M3_m ;
      RECT 0 118.335 0.07 118.405 ;
    END
  END w0_wd_in[105]
  PIN w0_wd_in[106]
    DIRECTION INPUT ;
    USE SIGNAL ;
    SHAPE ABUTMENT ;
    PORT
      LAYER M3_m ;
      RECT 0 119.035 0.07 119.105 ;
    END
  END w0_wd_in[106]
  PIN w0_wd_in[107]
    DIRECTION INPUT ;
    USE SIGNAL ;
    SHAPE ABUTMENT ;
    PORT
      LAYER M3_m ;
      RECT 0 119.735 0.07 119.805 ;
    END
  END w0_wd_in[107]
  PIN w0_wd_in[108]
    DIRECTION INPUT ;
    USE SIGNAL ;
    SHAPE ABUTMENT ;
    PORT
      LAYER M3_m ;
      RECT 0 120.435 0.07 120.505 ;
    END
  END w0_wd_in[108]
  PIN w0_wd_in[109]
    DIRECTION INPUT ;
    USE SIGNAL ;
    SHAPE ABUTMENT ;
    PORT
      LAYER M3_m ;
      RECT 0 121.135 0.07 121.205 ;
    END
  END w0_wd_in[109]
  PIN w0_wd_in[110]
    DIRECTION INPUT ;
    USE SIGNAL ;
    SHAPE ABUTMENT ;
    PORT
      LAYER M3_m ;
      RECT 0 121.835 0.07 121.905 ;
    END
  END w0_wd_in[110]
  PIN w0_wd_in[111]
    DIRECTION INPUT ;
    USE SIGNAL ;
    SHAPE ABUTMENT ;
    PORT
      LAYER M3_m ;
      RECT 0 122.535 0.07 122.605 ;
    END
  END w0_wd_in[111]
  PIN w0_wd_in[112]
    DIRECTION INPUT ;
    USE SIGNAL ;
    SHAPE ABUTMENT ;
    PORT
      LAYER M3_m ;
      RECT 0 123.235 0.07 123.305 ;
    END
  END w0_wd_in[112]
  PIN w0_wd_in[113]
    DIRECTION INPUT ;
    USE SIGNAL ;
    SHAPE ABUTMENT ;
    PORT
      LAYER M3_m ;
      RECT 0 123.935 0.07 124.005 ;
    END
  END w0_wd_in[113]
  PIN w0_wd_in[114]
    DIRECTION INPUT ;
    USE SIGNAL ;
    SHAPE ABUTMENT ;
    PORT
      LAYER M3_m ;
      RECT 0 124.635 0.07 124.705 ;
    END
  END w0_wd_in[114]
  PIN w0_wd_in[115]
    DIRECTION INPUT ;
    USE SIGNAL ;
    SHAPE ABUTMENT ;
    PORT
      LAYER M3_m ;
      RECT 0 125.335 0.07 125.405 ;
    END
  END w0_wd_in[115]
  PIN w0_wd_in[116]
    DIRECTION INPUT ;
    USE SIGNAL ;
    SHAPE ABUTMENT ;
    PORT
      LAYER M3_m ;
      RECT 0 126.035 0.07 126.105 ;
    END
  END w0_wd_in[116]
  PIN w0_wd_in[117]
    DIRECTION INPUT ;
    USE SIGNAL ;
    SHAPE ABUTMENT ;
    PORT
      LAYER M3_m ;
      RECT 0 126.735 0.07 126.805 ;
    END
  END w0_wd_in[117]
  PIN w0_wd_in[118]
    DIRECTION INPUT ;
    USE SIGNAL ;
    SHAPE ABUTMENT ;
    PORT
      LAYER M3_m ;
      RECT 0 127.435 0.07 127.505 ;
    END
  END w0_wd_in[118]
  PIN w0_wd_in[119]
    DIRECTION INPUT ;
    USE SIGNAL ;
    SHAPE ABUTMENT ;
    PORT
      LAYER M3_m ;
      RECT 0 128.135 0.07 128.205 ;
    END
  END w0_wd_in[119]
  PIN w0_wd_in[120]
    DIRECTION INPUT ;
    USE SIGNAL ;
    SHAPE ABUTMENT ;
    PORT
      LAYER M3_m ;
      RECT 0 128.835 0.07 128.905 ;
    END
  END w0_wd_in[120]
  PIN w0_wd_in[121]
    DIRECTION INPUT ;
    USE SIGNAL ;
    SHAPE ABUTMENT ;
    PORT
      LAYER M3_m ;
      RECT 0 129.535 0.07 129.605 ;
    END
  END w0_wd_in[121]
  PIN w0_wd_in[122]
    DIRECTION INPUT ;
    USE SIGNAL ;
    SHAPE ABUTMENT ;
    PORT
      LAYER M3_m ;
      RECT 0 130.235 0.07 130.305 ;
    END
  END w0_wd_in[122]
  PIN w0_wd_in[123]
    DIRECTION INPUT ;
    USE SIGNAL ;
    SHAPE ABUTMENT ;
    PORT
      LAYER M3_m ;
      RECT 0 130.935 0.07 131.005 ;
    END
  END w0_wd_in[123]
  PIN w0_wd_in[124]
    DIRECTION INPUT ;
    USE SIGNAL ;
    SHAPE ABUTMENT ;
    PORT
      LAYER M3_m ;
      RECT 0 131.635 0.07 131.705 ;
    END
  END w0_wd_in[124]
  PIN w0_wd_in[125]
    DIRECTION INPUT ;
    USE SIGNAL ;
    SHAPE ABUTMENT ;
    PORT
      LAYER M3_m ;
      RECT 0 132.335 0.07 132.405 ;
    END
  END w0_wd_in[125]
  PIN w0_wd_in[126]
    DIRECTION INPUT ;
    USE SIGNAL ;
    SHAPE ABUTMENT ;
    PORT
      LAYER M3_m ;
      RECT 0 133.035 0.07 133.105 ;
    END
  END w0_wd_in[126]
  PIN w0_wd_in[127]
    DIRECTION INPUT ;
    USE SIGNAL ;
    SHAPE ABUTMENT ;
    PORT
      LAYER M3_m ;
      RECT 0 133.735 0.07 133.805 ;
    END
  END w0_wd_in[127]
  PIN w0_wd_in[128]
    DIRECTION INPUT ;
    USE SIGNAL ;
    SHAPE ABUTMENT ;
    PORT
      LAYER M3_m ;
      RECT 0 134.435 0.07 134.505 ;
    END
  END w0_wd_in[128]
  PIN w0_wd_in[129]
    DIRECTION INPUT ;
    USE SIGNAL ;
    SHAPE ABUTMENT ;
    PORT
      LAYER M3_m ;
      RECT 0 135.135 0.07 135.205 ;
    END
  END w0_wd_in[129]
  PIN w0_wd_in[130]
    DIRECTION INPUT ;
    USE SIGNAL ;
    SHAPE ABUTMENT ;
    PORT
      LAYER M3_m ;
      RECT 0 135.835 0.07 135.905 ;
    END
  END w0_wd_in[130]
  PIN w0_wd_in[131]
    DIRECTION INPUT ;
    USE SIGNAL ;
    SHAPE ABUTMENT ;
    PORT
      LAYER M3_m ;
      RECT 0 136.535 0.07 136.605 ;
    END
  END w0_wd_in[131]
  PIN w0_wd_in[132]
    DIRECTION INPUT ;
    USE SIGNAL ;
    SHAPE ABUTMENT ;
    PORT
      LAYER M3_m ;
      RECT 0 137.235 0.07 137.305 ;
    END
  END w0_wd_in[132]
  PIN w0_wd_in[133]
    DIRECTION INPUT ;
    USE SIGNAL ;
    SHAPE ABUTMENT ;
    PORT
      LAYER M3_m ;
      RECT 0 137.935 0.07 138.005 ;
    END
  END w0_wd_in[133]
  PIN w0_wd_in[134]
    DIRECTION INPUT ;
    USE SIGNAL ;
    SHAPE ABUTMENT ;
    PORT
      LAYER M3_m ;
      RECT 0 138.635 0.07 138.705 ;
    END
  END w0_wd_in[134]
  PIN w0_wd_in[135]
    DIRECTION INPUT ;
    USE SIGNAL ;
    SHAPE ABUTMENT ;
    PORT
      LAYER M3_m ;
      RECT 0 139.335 0.07 139.405 ;
    END
  END w0_wd_in[135]
  PIN w0_wd_in[136]
    DIRECTION INPUT ;
    USE SIGNAL ;
    SHAPE ABUTMENT ;
    PORT
      LAYER M3_m ;
      RECT 0 140.035 0.07 140.105 ;
    END
  END w0_wd_in[136]
  PIN w0_wd_in[137]
    DIRECTION INPUT ;
    USE SIGNAL ;
    SHAPE ABUTMENT ;
    PORT
      LAYER M3_m ;
      RECT 0 140.735 0.07 140.805 ;
    END
  END w0_wd_in[137]
  PIN w0_wd_in[138]
    DIRECTION INPUT ;
    USE SIGNAL ;
    SHAPE ABUTMENT ;
    PORT
      LAYER M3_m ;
      RECT 0 141.435 0.07 141.505 ;
    END
  END w0_wd_in[138]
  PIN w0_wd_in[139]
    DIRECTION INPUT ;
    USE SIGNAL ;
    SHAPE ABUTMENT ;
    PORT
      LAYER M3_m ;
      RECT 0 142.135 0.07 142.205 ;
    END
  END w0_wd_in[139]
  PIN w0_wd_in[140]
    DIRECTION INPUT ;
    USE SIGNAL ;
    SHAPE ABUTMENT ;
    PORT
      LAYER M3_m ;
      RECT 0 142.835 0.07 142.905 ;
    END
  END w0_wd_in[140]
  PIN w0_wd_in[141]
    DIRECTION INPUT ;
    USE SIGNAL ;
    SHAPE ABUTMENT ;
    PORT
      LAYER M3_m ;
      RECT 0 143.535 0.07 143.605 ;
    END
  END w0_wd_in[141]
  PIN w0_wd_in[142]
    DIRECTION INPUT ;
    USE SIGNAL ;
    SHAPE ABUTMENT ;
    PORT
      LAYER M3_m ;
      RECT 0 144.235 0.07 144.305 ;
    END
  END w0_wd_in[142]
  PIN w0_wd_in[143]
    DIRECTION INPUT ;
    USE SIGNAL ;
    SHAPE ABUTMENT ;
    PORT
      LAYER M3_m ;
      RECT 0 144.935 0.07 145.005 ;
    END
  END w0_wd_in[143]
  PIN w0_wd_in[144]
    DIRECTION INPUT ;
    USE SIGNAL ;
    SHAPE ABUTMENT ;
    PORT
      LAYER M3_m ;
      RECT 0 145.635 0.07 145.705 ;
    END
  END w0_wd_in[144]
  PIN w0_wd_in[145]
    DIRECTION INPUT ;
    USE SIGNAL ;
    SHAPE ABUTMENT ;
    PORT
      LAYER M3_m ;
      RECT 0 146.335 0.07 146.405 ;
    END
  END w0_wd_in[145]
  PIN w0_wd_in[146]
    DIRECTION INPUT ;
    USE SIGNAL ;
    SHAPE ABUTMENT ;
    PORT
      LAYER M3_m ;
      RECT 0 147.035 0.07 147.105 ;
    END
  END w0_wd_in[146]
  PIN w0_wd_in[147]
    DIRECTION INPUT ;
    USE SIGNAL ;
    SHAPE ABUTMENT ;
    PORT
      LAYER M3_m ;
      RECT 0 147.735 0.07 147.805 ;
    END
  END w0_wd_in[147]
  PIN w0_wd_in[148]
    DIRECTION INPUT ;
    USE SIGNAL ;
    SHAPE ABUTMENT ;
    PORT
      LAYER M3_m ;
      RECT 0 148.435 0.07 148.505 ;
    END
  END w0_wd_in[148]
  PIN w0_wd_in[149]
    DIRECTION INPUT ;
    USE SIGNAL ;
    SHAPE ABUTMENT ;
    PORT
      LAYER M3_m ;
      RECT 0 149.135 0.07 149.205 ;
    END
  END w0_wd_in[149]
  PIN w0_wd_in[150]
    DIRECTION INPUT ;
    USE SIGNAL ;
    SHAPE ABUTMENT ;
    PORT
      LAYER M3_m ;
      RECT 0 149.835 0.07 149.905 ;
    END
  END w0_wd_in[150]
  PIN w0_wd_in[151]
    DIRECTION INPUT ;
    USE SIGNAL ;
    SHAPE ABUTMENT ;
    PORT
      LAYER M3_m ;
      RECT 0 150.535 0.07 150.605 ;
    END
  END w0_wd_in[151]
  PIN w0_wd_in[152]
    DIRECTION INPUT ;
    USE SIGNAL ;
    SHAPE ABUTMENT ;
    PORT
      LAYER M3_m ;
      RECT 0 151.235 0.07 151.305 ;
    END
  END w0_wd_in[152]
  PIN w0_wd_in[153]
    DIRECTION INPUT ;
    USE SIGNAL ;
    SHAPE ABUTMENT ;
    PORT
      LAYER M3_m ;
      RECT 0 151.935 0.07 152.005 ;
    END
  END w0_wd_in[153]
  PIN w0_wd_in[154]
    DIRECTION INPUT ;
    USE SIGNAL ;
    SHAPE ABUTMENT ;
    PORT
      LAYER M3_m ;
      RECT 0 152.635 0.07 152.705 ;
    END
  END w0_wd_in[154]
  PIN w0_wd_in[155]
    DIRECTION INPUT ;
    USE SIGNAL ;
    SHAPE ABUTMENT ;
    PORT
      LAYER M3_m ;
      RECT 0 153.335 0.07 153.405 ;
    END
  END w0_wd_in[155]
  PIN w0_wd_in[156]
    DIRECTION INPUT ;
    USE SIGNAL ;
    SHAPE ABUTMENT ;
    PORT
      LAYER M3_m ;
      RECT 0 154.035 0.07 154.105 ;
    END
  END w0_wd_in[156]
  PIN w0_wd_in[157]
    DIRECTION INPUT ;
    USE SIGNAL ;
    SHAPE ABUTMENT ;
    PORT
      LAYER M3_m ;
      RECT 0 154.735 0.07 154.805 ;
    END
  END w0_wd_in[157]
  PIN w0_wd_in[158]
    DIRECTION INPUT ;
    USE SIGNAL ;
    SHAPE ABUTMENT ;
    PORT
      LAYER M3_m ;
      RECT 0 155.435 0.07 155.505 ;
    END
  END w0_wd_in[158]
  PIN w0_wd_in[159]
    DIRECTION INPUT ;
    USE SIGNAL ;
    SHAPE ABUTMENT ;
    PORT
      LAYER M3_m ;
      RECT 0 156.135 0.07 156.205 ;
    END
  END w0_wd_in[159]
  PIN w0_wd_in[160]
    DIRECTION INPUT ;
    USE SIGNAL ;
    SHAPE ABUTMENT ;
    PORT
      LAYER M3_m ;
      RECT 0 156.835 0.07 156.905 ;
    END
  END w0_wd_in[160]
  PIN w0_wd_in[161]
    DIRECTION INPUT ;
    USE SIGNAL ;
    SHAPE ABUTMENT ;
    PORT
      LAYER M3_m ;
      RECT 0 157.535 0.07 157.605 ;
    END
  END w0_wd_in[161]
  PIN w0_wd_in[162]
    DIRECTION INPUT ;
    USE SIGNAL ;
    SHAPE ABUTMENT ;
    PORT
      LAYER M3_m ;
      RECT 0 158.235 0.07 158.305 ;
    END
  END w0_wd_in[162]
  PIN w0_wd_in[163]
    DIRECTION INPUT ;
    USE SIGNAL ;
    SHAPE ABUTMENT ;
    PORT
      LAYER M3_m ;
      RECT 0 158.935 0.07 159.005 ;
    END
  END w0_wd_in[163]
  PIN w0_wd_in[164]
    DIRECTION INPUT ;
    USE SIGNAL ;
    SHAPE ABUTMENT ;
    PORT
      LAYER M3_m ;
      RECT 0 159.635 0.07 159.705 ;
    END
  END w0_wd_in[164]
  PIN w0_wd_in[165]
    DIRECTION INPUT ;
    USE SIGNAL ;
    SHAPE ABUTMENT ;
    PORT
      LAYER M3_m ;
      RECT 0 160.335 0.07 160.405 ;
    END
  END w0_wd_in[165]
  PIN w0_wd_in[166]
    DIRECTION INPUT ;
    USE SIGNAL ;
    SHAPE ABUTMENT ;
    PORT
      LAYER M3_m ;
      RECT 0 161.035 0.07 161.105 ;
    END
  END w0_wd_in[166]
  PIN w0_wd_in[167]
    DIRECTION INPUT ;
    USE SIGNAL ;
    SHAPE ABUTMENT ;
    PORT
      LAYER M3_m ;
      RECT 0 161.735 0.07 161.805 ;
    END
  END w0_wd_in[167]
  PIN w0_wd_in[168]
    DIRECTION INPUT ;
    USE SIGNAL ;
    SHAPE ABUTMENT ;
    PORT
      LAYER M3_m ;
      RECT 0 162.435 0.07 162.505 ;
    END
  END w0_wd_in[168]
  PIN w0_wd_in[169]
    DIRECTION INPUT ;
    USE SIGNAL ;
    SHAPE ABUTMENT ;
    PORT
      LAYER M3_m ;
      RECT 0 163.135 0.07 163.205 ;
    END
  END w0_wd_in[169]
  PIN w0_wd_in[170]
    DIRECTION INPUT ;
    USE SIGNAL ;
    SHAPE ABUTMENT ;
    PORT
      LAYER M3_m ;
      RECT 0 163.835 0.07 163.905 ;
    END
  END w0_wd_in[170]
  PIN w0_wd_in[171]
    DIRECTION INPUT ;
    USE SIGNAL ;
    SHAPE ABUTMENT ;
    PORT
      LAYER M3_m ;
      RECT 0 164.535 0.07 164.605 ;
    END
  END w0_wd_in[171]
  PIN w0_wd_in[172]
    DIRECTION INPUT ;
    USE SIGNAL ;
    SHAPE ABUTMENT ;
    PORT
      LAYER M3_m ;
      RECT 0 165.235 0.07 165.305 ;
    END
  END w0_wd_in[172]
  PIN w0_wd_in[173]
    DIRECTION INPUT ;
    USE SIGNAL ;
    SHAPE ABUTMENT ;
    PORT
      LAYER M3_m ;
      RECT 0 165.935 0.07 166.005 ;
    END
  END w0_wd_in[173]
  PIN w0_wd_in[174]
    DIRECTION INPUT ;
    USE SIGNAL ;
    SHAPE ABUTMENT ;
    PORT
      LAYER M3_m ;
      RECT 0 166.635 0.07 166.705 ;
    END
  END w0_wd_in[174]
  PIN w0_wd_in[175]
    DIRECTION INPUT ;
    USE SIGNAL ;
    SHAPE ABUTMENT ;
    PORT
      LAYER M3_m ;
      RECT 0 167.335 0.07 167.405 ;
    END
  END w0_wd_in[175]
  PIN w0_wd_in[176]
    DIRECTION INPUT ;
    USE SIGNAL ;
    SHAPE ABUTMENT ;
    PORT
      LAYER M3_m ;
      RECT 0 168.035 0.07 168.105 ;
    END
  END w0_wd_in[176]
  PIN w0_wd_in[177]
    DIRECTION INPUT ;
    USE SIGNAL ;
    SHAPE ABUTMENT ;
    PORT
      LAYER M3_m ;
      RECT 0 168.735 0.07 168.805 ;
    END
  END w0_wd_in[177]
  PIN w0_wd_in[178]
    DIRECTION INPUT ;
    USE SIGNAL ;
    SHAPE ABUTMENT ;
    PORT
      LAYER M3_m ;
      RECT 0 169.435 0.07 169.505 ;
    END
  END w0_wd_in[178]
  PIN w0_wd_in[179]
    DIRECTION INPUT ;
    USE SIGNAL ;
    SHAPE ABUTMENT ;
    PORT
      LAYER M3_m ;
      RECT 0 170.135 0.07 170.205 ;
    END
  END w0_wd_in[179]
  PIN w0_wd_in[180]
    DIRECTION INPUT ;
    USE SIGNAL ;
    SHAPE ABUTMENT ;
    PORT
      LAYER M3_m ;
      RECT 0 170.835 0.07 170.905 ;
    END
  END w0_wd_in[180]
  PIN w0_wd_in[181]
    DIRECTION INPUT ;
    USE SIGNAL ;
    SHAPE ABUTMENT ;
    PORT
      LAYER M3_m ;
      RECT 0 171.535 0.07 171.605 ;
    END
  END w0_wd_in[181]
  PIN w0_wd_in[182]
    DIRECTION INPUT ;
    USE SIGNAL ;
    SHAPE ABUTMENT ;
    PORT
      LAYER M3_m ;
      RECT 0 172.235 0.07 172.305 ;
    END
  END w0_wd_in[182]
  PIN w0_wd_in[183]
    DIRECTION INPUT ;
    USE SIGNAL ;
    SHAPE ABUTMENT ;
    PORT
      LAYER M3_m ;
      RECT 0 172.935 0.07 173.005 ;
    END
  END w0_wd_in[183]
  PIN w0_wd_in[184]
    DIRECTION INPUT ;
    USE SIGNAL ;
    SHAPE ABUTMENT ;
    PORT
      LAYER M3_m ;
      RECT 0 173.635 0.07 173.705 ;
    END
  END w0_wd_in[184]
  PIN w0_wd_in[185]
    DIRECTION INPUT ;
    USE SIGNAL ;
    SHAPE ABUTMENT ;
    PORT
      LAYER M3_m ;
      RECT 0 174.335 0.07 174.405 ;
    END
  END w0_wd_in[185]
  PIN w0_wd_in[186]
    DIRECTION INPUT ;
    USE SIGNAL ;
    SHAPE ABUTMENT ;
    PORT
      LAYER M3_m ;
      RECT 0 175.035 0.07 175.105 ;
    END
  END w0_wd_in[186]
  PIN w0_wd_in[187]
    DIRECTION INPUT ;
    USE SIGNAL ;
    SHAPE ABUTMENT ;
    PORT
      LAYER M3_m ;
      RECT 0 175.735 0.07 175.805 ;
    END
  END w0_wd_in[187]
  PIN w0_wd_in[188]
    DIRECTION INPUT ;
    USE SIGNAL ;
    SHAPE ABUTMENT ;
    PORT
      LAYER M3_m ;
      RECT 0 176.435 0.07 176.505 ;
    END
  END w0_wd_in[188]
  PIN w0_wd_in[189]
    DIRECTION INPUT ;
    USE SIGNAL ;
    SHAPE ABUTMENT ;
    PORT
      LAYER M3_m ;
      RECT 0 177.135 0.07 177.205 ;
    END
  END w0_wd_in[189]
  PIN w0_wd_in[190]
    DIRECTION INPUT ;
    USE SIGNAL ;
    SHAPE ABUTMENT ;
    PORT
      LAYER M3_m ;
      RECT 0 177.835 0.07 177.905 ;
    END
  END w0_wd_in[190]
  PIN w0_wd_in[191]
    DIRECTION INPUT ;
    USE SIGNAL ;
    SHAPE ABUTMENT ;
    PORT
      LAYER M3_m ;
      RECT 0 178.535 0.07 178.605 ;
    END
  END w0_wd_in[191]
  PIN w0_wd_in[192]
    DIRECTION INPUT ;
    USE SIGNAL ;
    SHAPE ABUTMENT ;
    PORT
      LAYER M3_m ;
      RECT 0 179.235 0.07 179.305 ;
    END
  END w0_wd_in[192]
  PIN w0_wd_in[193]
    DIRECTION INPUT ;
    USE SIGNAL ;
    SHAPE ABUTMENT ;
    PORT
      LAYER M3_m ;
      RECT 0 179.935 0.07 180.005 ;
    END
  END w0_wd_in[193]
  PIN w0_wd_in[194]
    DIRECTION INPUT ;
    USE SIGNAL ;
    SHAPE ABUTMENT ;
    PORT
      LAYER M3_m ;
      RECT 0 180.635 0.07 180.705 ;
    END
  END w0_wd_in[194]
  PIN w0_wd_in[195]
    DIRECTION INPUT ;
    USE SIGNAL ;
    SHAPE ABUTMENT ;
    PORT
      LAYER M3_m ;
      RECT 0 181.335 0.07 181.405 ;
    END
  END w0_wd_in[195]
  PIN w0_wd_in[196]
    DIRECTION INPUT ;
    USE SIGNAL ;
    SHAPE ABUTMENT ;
    PORT
      LAYER M3_m ;
      RECT 0 182.035 0.07 182.105 ;
    END
  END w0_wd_in[196]
  PIN w0_wd_in[197]
    DIRECTION INPUT ;
    USE SIGNAL ;
    SHAPE ABUTMENT ;
    PORT
      LAYER M3_m ;
      RECT 0 182.735 0.07 182.805 ;
    END
  END w0_wd_in[197]
  PIN w0_wd_in[198]
    DIRECTION INPUT ;
    USE SIGNAL ;
    SHAPE ABUTMENT ;
    PORT
      LAYER M3_m ;
      RECT 0 183.435 0.07 183.505 ;
    END
  END w0_wd_in[198]
  PIN w0_wd_in[199]
    DIRECTION INPUT ;
    USE SIGNAL ;
    SHAPE ABUTMENT ;
    PORT
      LAYER M3_m ;
      RECT 0 184.135 0.07 184.205 ;
    END
  END w0_wd_in[199]
  PIN w0_wd_in[200]
    DIRECTION INPUT ;
    USE SIGNAL ;
    SHAPE ABUTMENT ;
    PORT
      LAYER M3_m ;
      RECT 0 184.835 0.07 184.905 ;
    END
  END w0_wd_in[200]
  PIN w0_wd_in[201]
    DIRECTION INPUT ;
    USE SIGNAL ;
    SHAPE ABUTMENT ;
    PORT
      LAYER M3_m ;
      RECT 0 185.535 0.07 185.605 ;
    END
  END w0_wd_in[201]
  PIN w0_wd_in[202]
    DIRECTION INPUT ;
    USE SIGNAL ;
    SHAPE ABUTMENT ;
    PORT
      LAYER M3_m ;
      RECT 0 186.235 0.07 186.305 ;
    END
  END w0_wd_in[202]
  PIN w0_wd_in[203]
    DIRECTION INPUT ;
    USE SIGNAL ;
    SHAPE ABUTMENT ;
    PORT
      LAYER M3_m ;
      RECT 0 186.935 0.07 187.005 ;
    END
  END w0_wd_in[203]
  PIN w0_wd_in[204]
    DIRECTION INPUT ;
    USE SIGNAL ;
    SHAPE ABUTMENT ;
    PORT
      LAYER M3_m ;
      RECT 0 187.635 0.07 187.705 ;
    END
  END w0_wd_in[204]
  PIN w0_wd_in[205]
    DIRECTION INPUT ;
    USE SIGNAL ;
    SHAPE ABUTMENT ;
    PORT
      LAYER M3_m ;
      RECT 0 188.335 0.07 188.405 ;
    END
  END w0_wd_in[205]
  PIN w0_wd_in[206]
    DIRECTION INPUT ;
    USE SIGNAL ;
    SHAPE ABUTMENT ;
    PORT
      LAYER M3_m ;
      RECT 0 189.035 0.07 189.105 ;
    END
  END w0_wd_in[206]
  PIN w0_wd_in[207]
    DIRECTION INPUT ;
    USE SIGNAL ;
    SHAPE ABUTMENT ;
    PORT
      LAYER M3_m ;
      RECT 0 189.735 0.07 189.805 ;
    END
  END w0_wd_in[207]
  PIN w0_wd_in[208]
    DIRECTION INPUT ;
    USE SIGNAL ;
    SHAPE ABUTMENT ;
    PORT
      LAYER M3_m ;
      RECT 0 190.435 0.07 190.505 ;
    END
  END w0_wd_in[208]
  PIN w0_wd_in[209]
    DIRECTION INPUT ;
    USE SIGNAL ;
    SHAPE ABUTMENT ;
    PORT
      LAYER M3_m ;
      RECT 0 191.135 0.07 191.205 ;
    END
  END w0_wd_in[209]
  PIN w0_wd_in[210]
    DIRECTION INPUT ;
    USE SIGNAL ;
    SHAPE ABUTMENT ;
    PORT
      LAYER M3_m ;
      RECT 0 191.835 0.07 191.905 ;
    END
  END w0_wd_in[210]
  PIN w0_wd_in[211]
    DIRECTION INPUT ;
    USE SIGNAL ;
    SHAPE ABUTMENT ;
    PORT
      LAYER M3_m ;
      RECT 0 192.535 0.07 192.605 ;
    END
  END w0_wd_in[211]
  PIN w0_wd_in[212]
    DIRECTION INPUT ;
    USE SIGNAL ;
    SHAPE ABUTMENT ;
    PORT
      LAYER M3_m ;
      RECT 0 193.235 0.07 193.305 ;
    END
  END w0_wd_in[212]
  PIN w0_wd_in[213]
    DIRECTION INPUT ;
    USE SIGNAL ;
    SHAPE ABUTMENT ;
    PORT
      LAYER M3_m ;
      RECT 0 193.935 0.07 194.005 ;
    END
  END w0_wd_in[213]
  PIN w0_wd_in[214]
    DIRECTION INPUT ;
    USE SIGNAL ;
    SHAPE ABUTMENT ;
    PORT
      LAYER M3_m ;
      RECT 0 194.635 0.07 194.705 ;
    END
  END w0_wd_in[214]
  PIN w0_wd_in[215]
    DIRECTION INPUT ;
    USE SIGNAL ;
    SHAPE ABUTMENT ;
    PORT
      LAYER M3_m ;
      RECT 0 195.335 0.07 195.405 ;
    END
  END w0_wd_in[215]
  PIN w0_wd_in[216]
    DIRECTION INPUT ;
    USE SIGNAL ;
    SHAPE ABUTMENT ;
    PORT
      LAYER M3_m ;
      RECT 0 196.035 0.07 196.105 ;
    END
  END w0_wd_in[216]
  PIN w0_wd_in[217]
    DIRECTION INPUT ;
    USE SIGNAL ;
    SHAPE ABUTMENT ;
    PORT
      LAYER M3_m ;
      RECT 0 196.735 0.07 196.805 ;
    END
  END w0_wd_in[217]
  PIN w0_wd_in[218]
    DIRECTION INPUT ;
    USE SIGNAL ;
    SHAPE ABUTMENT ;
    PORT
      LAYER M3_m ;
      RECT 0 197.435 0.07 197.505 ;
    END
  END w0_wd_in[218]
  PIN w0_wd_in[219]
    DIRECTION INPUT ;
    USE SIGNAL ;
    SHAPE ABUTMENT ;
    PORT
      LAYER M3_m ;
      RECT 0 198.135 0.07 198.205 ;
    END
  END w0_wd_in[219]
  PIN w0_wd_in[220]
    DIRECTION INPUT ;
    USE SIGNAL ;
    SHAPE ABUTMENT ;
    PORT
      LAYER M3_m ;
      RECT 0 198.835 0.07 198.905 ;
    END
  END w0_wd_in[220]
  PIN w0_wd_in[221]
    DIRECTION INPUT ;
    USE SIGNAL ;
    SHAPE ABUTMENT ;
    PORT
      LAYER M3_m ;
      RECT 0 199.535 0.07 199.605 ;
    END
  END w0_wd_in[221]
  PIN w0_wd_in[222]
    DIRECTION INPUT ;
    USE SIGNAL ;
    SHAPE ABUTMENT ;
    PORT
      LAYER M3_m ;
      RECT 0 200.235 0.07 200.305 ;
    END
  END w0_wd_in[222]
  PIN w0_wd_in[223]
    DIRECTION INPUT ;
    USE SIGNAL ;
    SHAPE ABUTMENT ;
    PORT
      LAYER M3_m ;
      RECT 0 200.935 0.07 201.005 ;
    END
  END w0_wd_in[223]
  PIN w0_wd_in[224]
    DIRECTION INPUT ;
    USE SIGNAL ;
    SHAPE ABUTMENT ;
    PORT
      LAYER M3_m ;
      RECT 0 201.635 0.07 201.705 ;
    END
  END w0_wd_in[224]
  PIN w0_wd_in[225]
    DIRECTION INPUT ;
    USE SIGNAL ;
    SHAPE ABUTMENT ;
    PORT
      LAYER M3_m ;
      RECT 0 202.335 0.07 202.405 ;
    END
  END w0_wd_in[225]
  PIN w0_wd_in[226]
    DIRECTION INPUT ;
    USE SIGNAL ;
    SHAPE ABUTMENT ;
    PORT
      LAYER M3_m ;
      RECT 0 203.035 0.07 203.105 ;
    END
  END w0_wd_in[226]
  PIN w0_wd_in[227]
    DIRECTION INPUT ;
    USE SIGNAL ;
    SHAPE ABUTMENT ;
    PORT
      LAYER M3_m ;
      RECT 0 203.735 0.07 203.805 ;
    END
  END w0_wd_in[227]
  PIN w0_wd_in[228]
    DIRECTION INPUT ;
    USE SIGNAL ;
    SHAPE ABUTMENT ;
    PORT
      LAYER M3_m ;
      RECT 0 204.435 0.07 204.505 ;
    END
  END w0_wd_in[228]
  PIN w0_wd_in[229]
    DIRECTION INPUT ;
    USE SIGNAL ;
    SHAPE ABUTMENT ;
    PORT
      LAYER M3_m ;
      RECT 0 205.135 0.07 205.205 ;
    END
  END w0_wd_in[229]
  PIN w0_wd_in[230]
    DIRECTION INPUT ;
    USE SIGNAL ;
    SHAPE ABUTMENT ;
    PORT
      LAYER M3_m ;
      RECT 0 205.835 0.07 205.905 ;
    END
  END w0_wd_in[230]
  PIN w0_wd_in[231]
    DIRECTION INPUT ;
    USE SIGNAL ;
    SHAPE ABUTMENT ;
    PORT
      LAYER M3_m ;
      RECT 0 206.535 0.07 206.605 ;
    END
  END w0_wd_in[231]
  PIN w0_wd_in[232]
    DIRECTION INPUT ;
    USE SIGNAL ;
    SHAPE ABUTMENT ;
    PORT
      LAYER M3_m ;
      RECT 0 207.235 0.07 207.305 ;
    END
  END w0_wd_in[232]
  PIN w0_wd_in[233]
    DIRECTION INPUT ;
    USE SIGNAL ;
    SHAPE ABUTMENT ;
    PORT
      LAYER M3_m ;
      RECT 0 207.935 0.07 208.005 ;
    END
  END w0_wd_in[233]
  PIN w0_wd_in[234]
    DIRECTION INPUT ;
    USE SIGNAL ;
    SHAPE ABUTMENT ;
    PORT
      LAYER M3_m ;
      RECT 0 208.635 0.07 208.705 ;
    END
  END w0_wd_in[234]
  PIN w0_wd_in[235]
    DIRECTION INPUT ;
    USE SIGNAL ;
    SHAPE ABUTMENT ;
    PORT
      LAYER M3_m ;
      RECT 0 209.335 0.07 209.405 ;
    END
  END w0_wd_in[235]
  PIN w0_wd_in[236]
    DIRECTION INPUT ;
    USE SIGNAL ;
    SHAPE ABUTMENT ;
    PORT
      LAYER M3_m ;
      RECT 0 210.035 0.07 210.105 ;
    END
  END w0_wd_in[236]
  PIN w0_wd_in[237]
    DIRECTION INPUT ;
    USE SIGNAL ;
    SHAPE ABUTMENT ;
    PORT
      LAYER M3_m ;
      RECT 0 210.735 0.07 210.805 ;
    END
  END w0_wd_in[237]
  PIN w0_wd_in[238]
    DIRECTION INPUT ;
    USE SIGNAL ;
    SHAPE ABUTMENT ;
    PORT
      LAYER M3_m ;
      RECT 0 211.435 0.07 211.505 ;
    END
  END w0_wd_in[238]
  PIN w0_wd_in[239]
    DIRECTION INPUT ;
    USE SIGNAL ;
    SHAPE ABUTMENT ;
    PORT
      LAYER M3_m ;
      RECT 0 212.135 0.07 212.205 ;
    END
  END w0_wd_in[239]
  PIN w0_wd_in[240]
    DIRECTION INPUT ;
    USE SIGNAL ;
    SHAPE ABUTMENT ;
    PORT
      LAYER M3_m ;
      RECT 0 212.835 0.07 212.905 ;
    END
  END w0_wd_in[240]
  PIN w0_wd_in[241]
    DIRECTION INPUT ;
    USE SIGNAL ;
    SHAPE ABUTMENT ;
    PORT
      LAYER M3_m ;
      RECT 0 213.535 0.07 213.605 ;
    END
  END w0_wd_in[241]
  PIN w0_wd_in[242]
    DIRECTION INPUT ;
    USE SIGNAL ;
    SHAPE ABUTMENT ;
    PORT
      LAYER M3_m ;
      RECT 0 214.235 0.07 214.305 ;
    END
  END w0_wd_in[242]
  PIN w0_wd_in[243]
    DIRECTION INPUT ;
    USE SIGNAL ;
    SHAPE ABUTMENT ;
    PORT
      LAYER M3_m ;
      RECT 0 214.935 0.07 215.005 ;
    END
  END w0_wd_in[243]
  PIN w0_wd_in[244]
    DIRECTION INPUT ;
    USE SIGNAL ;
    SHAPE ABUTMENT ;
    PORT
      LAYER M3_m ;
      RECT 0 215.635 0.07 215.705 ;
    END
  END w0_wd_in[244]
  PIN w0_wd_in[245]
    DIRECTION INPUT ;
    USE SIGNAL ;
    SHAPE ABUTMENT ;
    PORT
      LAYER M3_m ;
      RECT 0 216.335 0.07 216.405 ;
    END
  END w0_wd_in[245]
  PIN w0_wd_in[246]
    DIRECTION INPUT ;
    USE SIGNAL ;
    SHAPE ABUTMENT ;
    PORT
      LAYER M3_m ;
      RECT 0 217.035 0.07 217.105 ;
    END
  END w0_wd_in[246]
  PIN w0_wd_in[247]
    DIRECTION INPUT ;
    USE SIGNAL ;
    SHAPE ABUTMENT ;
    PORT
      LAYER M3_m ;
      RECT 0 217.735 0.07 217.805 ;
    END
  END w0_wd_in[247]
  PIN w0_wd_in[248]
    DIRECTION INPUT ;
    USE SIGNAL ;
    SHAPE ABUTMENT ;
    PORT
      LAYER M3_m ;
      RECT 0 218.435 0.07 218.505 ;
    END
  END w0_wd_in[248]
  PIN w0_wd_in[249]
    DIRECTION INPUT ;
    USE SIGNAL ;
    SHAPE ABUTMENT ;
    PORT
      LAYER M3_m ;
      RECT 0 219.135 0.07 219.205 ;
    END
  END w0_wd_in[249]
  PIN w0_wd_in[250]
    DIRECTION INPUT ;
    USE SIGNAL ;
    SHAPE ABUTMENT ;
    PORT
      LAYER M3_m ;
      RECT 0 219.835 0.07 219.905 ;
    END
  END w0_wd_in[250]
  PIN w0_wd_in[251]
    DIRECTION INPUT ;
    USE SIGNAL ;
    SHAPE ABUTMENT ;
    PORT
      LAYER M3_m ;
      RECT 0 220.535 0.07 220.605 ;
    END
  END w0_wd_in[251]
  PIN w0_wd_in[252]
    DIRECTION INPUT ;
    USE SIGNAL ;
    SHAPE ABUTMENT ;
    PORT
      LAYER M3_m ;
      RECT 0 221.235 0.07 221.305 ;
    END
  END w0_wd_in[252]
  PIN w0_wd_in[253]
    DIRECTION INPUT ;
    USE SIGNAL ;
    SHAPE ABUTMENT ;
    PORT
      LAYER M3_m ;
      RECT 0 221.935 0.07 222.005 ;
    END
  END w0_wd_in[253]
  PIN w0_wd_in[254]
    DIRECTION INPUT ;
    USE SIGNAL ;
    SHAPE ABUTMENT ;
    PORT
      LAYER M3_m ;
      RECT 0 222.635 0.07 222.705 ;
    END
  END w0_wd_in[254]
  PIN w0_wd_in[255]
    DIRECTION INPUT ;
    USE SIGNAL ;
    SHAPE ABUTMENT ;
    PORT
      LAYER M3_m ;
      RECT 0 223.335 0.07 223.405 ;
    END
  END w0_wd_in[255]
  PIN w0_wd_in[256]
    DIRECTION INPUT ;
    USE SIGNAL ;
    SHAPE ABUTMENT ;
    PORT
      LAYER M3_m ;
      RECT 0 224.035 0.07 224.105 ;
    END
  END w0_wd_in[256]
  PIN w0_wd_in[257]
    DIRECTION INPUT ;
    USE SIGNAL ;
    SHAPE ABUTMENT ;
    PORT
      LAYER M3_m ;
      RECT 0 224.735 0.07 224.805 ;
    END
  END w0_wd_in[257]
  PIN w0_wd_in[258]
    DIRECTION INPUT ;
    USE SIGNAL ;
    SHAPE ABUTMENT ;
    PORT
      LAYER M3_m ;
      RECT 0 225.435 0.07 225.505 ;
    END
  END w0_wd_in[258]
  PIN w0_wd_in[259]
    DIRECTION INPUT ;
    USE SIGNAL ;
    SHAPE ABUTMENT ;
    PORT
      LAYER M3_m ;
      RECT 0 226.135 0.07 226.205 ;
    END
  END w0_wd_in[259]
  PIN w0_wd_in[260]
    DIRECTION INPUT ;
    USE SIGNAL ;
    SHAPE ABUTMENT ;
    PORT
      LAYER M3_m ;
      RECT 0 226.835 0.07 226.905 ;
    END
  END w0_wd_in[260]
  PIN w0_wd_in[261]
    DIRECTION INPUT ;
    USE SIGNAL ;
    SHAPE ABUTMENT ;
    PORT
      LAYER M3_m ;
      RECT 0 227.535 0.07 227.605 ;
    END
  END w0_wd_in[261]
  PIN w0_wd_in[262]
    DIRECTION INPUT ;
    USE SIGNAL ;
    SHAPE ABUTMENT ;
    PORT
      LAYER M3_m ;
      RECT 0 228.235 0.07 228.305 ;
    END
  END w0_wd_in[262]
  PIN w0_wd_in[263]
    DIRECTION INPUT ;
    USE SIGNAL ;
    SHAPE ABUTMENT ;
    PORT
      LAYER M3_m ;
      RECT 0 228.935 0.07 229.005 ;
    END
  END w0_wd_in[263]
  PIN w0_wd_in[264]
    DIRECTION INPUT ;
    USE SIGNAL ;
    SHAPE ABUTMENT ;
    PORT
      LAYER M3_m ;
      RECT 0 229.635 0.07 229.705 ;
    END
  END w0_wd_in[264]
  PIN w0_wd_in[265]
    DIRECTION INPUT ;
    USE SIGNAL ;
    SHAPE ABUTMENT ;
    PORT
      LAYER M3_m ;
      RECT 0 230.335 0.07 230.405 ;
    END
  END w0_wd_in[265]
  PIN w0_wd_in[266]
    DIRECTION INPUT ;
    USE SIGNAL ;
    SHAPE ABUTMENT ;
    PORT
      LAYER M3_m ;
      RECT 0 231.035 0.07 231.105 ;
    END
  END w0_wd_in[266]
  PIN w0_wd_in[267]
    DIRECTION INPUT ;
    USE SIGNAL ;
    SHAPE ABUTMENT ;
    PORT
      LAYER M3_m ;
      RECT 0 231.735 0.07 231.805 ;
    END
  END w0_wd_in[267]
  PIN w0_wd_in[268]
    DIRECTION INPUT ;
    USE SIGNAL ;
    SHAPE ABUTMENT ;
    PORT
      LAYER M3_m ;
      RECT 0 232.435 0.07 232.505 ;
    END
  END w0_wd_in[268]
  PIN w0_wd_in[269]
    DIRECTION INPUT ;
    USE SIGNAL ;
    SHAPE ABUTMENT ;
    PORT
      LAYER M3_m ;
      RECT 0 233.135 0.07 233.205 ;
    END
  END w0_wd_in[269]
  PIN w0_wd_in[270]
    DIRECTION INPUT ;
    USE SIGNAL ;
    SHAPE ABUTMENT ;
    PORT
      LAYER M3_m ;
      RECT 0 233.835 0.07 233.905 ;
    END
  END w0_wd_in[270]
  PIN w0_wd_in[271]
    DIRECTION INPUT ;
    USE SIGNAL ;
    SHAPE ABUTMENT ;
    PORT
      LAYER M3_m ;
      RECT 0 234.535 0.07 234.605 ;
    END
  END w0_wd_in[271]
  PIN w0_wd_in[272]
    DIRECTION INPUT ;
    USE SIGNAL ;
    SHAPE ABUTMENT ;
    PORT
      LAYER M3_m ;
      RECT 0 235.235 0.07 235.305 ;
    END
  END w0_wd_in[272]
  PIN w0_wd_in[273]
    DIRECTION INPUT ;
    USE SIGNAL ;
    SHAPE ABUTMENT ;
    PORT
      LAYER M3_m ;
      RECT 0 235.935 0.07 236.005 ;
    END
  END w0_wd_in[273]
  PIN w0_wd_in[274]
    DIRECTION INPUT ;
    USE SIGNAL ;
    SHAPE ABUTMENT ;
    PORT
      LAYER M3_m ;
      RECT 0 236.635 0.07 236.705 ;
    END
  END w0_wd_in[274]
  PIN w0_wd_in[275]
    DIRECTION INPUT ;
    USE SIGNAL ;
    SHAPE ABUTMENT ;
    PORT
      LAYER M3_m ;
      RECT 0 237.335 0.07 237.405 ;
    END
  END w0_wd_in[275]
  PIN w0_wd_in[276]
    DIRECTION INPUT ;
    USE SIGNAL ;
    SHAPE ABUTMENT ;
    PORT
      LAYER M3_m ;
      RECT 0 238.035 0.07 238.105 ;
    END
  END w0_wd_in[276]
  PIN w0_wd_in[277]
    DIRECTION INPUT ;
    USE SIGNAL ;
    SHAPE ABUTMENT ;
    PORT
      LAYER M3_m ;
      RECT 0 238.735 0.07 238.805 ;
    END
  END w0_wd_in[277]
  PIN w0_wd_in[278]
    DIRECTION INPUT ;
    USE SIGNAL ;
    SHAPE ABUTMENT ;
    PORT
      LAYER M3_m ;
      RECT 0 239.435 0.07 239.505 ;
    END
  END w0_wd_in[278]
  PIN w0_wd_in[279]
    DIRECTION INPUT ;
    USE SIGNAL ;
    SHAPE ABUTMENT ;
    PORT
      LAYER M3_m ;
      RECT 0 240.135 0.07 240.205 ;
    END
  END w0_wd_in[279]
  PIN w0_wd_in[280]
    DIRECTION INPUT ;
    USE SIGNAL ;
    SHAPE ABUTMENT ;
    PORT
      LAYER M3_m ;
      RECT 0 240.835 0.07 240.905 ;
    END
  END w0_wd_in[280]
  PIN w0_wd_in[281]
    DIRECTION INPUT ;
    USE SIGNAL ;
    SHAPE ABUTMENT ;
    PORT
      LAYER M3_m ;
      RECT 0 241.535 0.07 241.605 ;
    END
  END w0_wd_in[281]
  PIN w0_wd_in[282]
    DIRECTION INPUT ;
    USE SIGNAL ;
    SHAPE ABUTMENT ;
    PORT
      LAYER M3_m ;
      RECT 0 242.235 0.07 242.305 ;
    END
  END w0_wd_in[282]
  PIN w0_wd_in[283]
    DIRECTION INPUT ;
    USE SIGNAL ;
    SHAPE ABUTMENT ;
    PORT
      LAYER M3_m ;
      RECT 0 242.935 0.07 243.005 ;
    END
  END w0_wd_in[283]
  PIN w0_wd_in[284]
    DIRECTION INPUT ;
    USE SIGNAL ;
    SHAPE ABUTMENT ;
    PORT
      LAYER M3_m ;
      RECT 0 243.635 0.07 243.705 ;
    END
  END w0_wd_in[284]
  PIN w0_wd_in[285]
    DIRECTION INPUT ;
    USE SIGNAL ;
    SHAPE ABUTMENT ;
    PORT
      LAYER M3_m ;
      RECT 0 244.335 0.07 244.405 ;
    END
  END w0_wd_in[285]
  PIN w0_wd_in[286]
    DIRECTION INPUT ;
    USE SIGNAL ;
    SHAPE ABUTMENT ;
    PORT
      LAYER M3_m ;
      RECT 0 245.035 0.07 245.105 ;
    END
  END w0_wd_in[286]
  PIN w0_wd_in[287]
    DIRECTION INPUT ;
    USE SIGNAL ;
    SHAPE ABUTMENT ;
    PORT
      LAYER M3_m ;
      RECT 0 245.735 0.07 245.805 ;
    END
  END w0_wd_in[287]
  PIN w0_wd_in[288]
    DIRECTION INPUT ;
    USE SIGNAL ;
    SHAPE ABUTMENT ;
    PORT
      LAYER M3_m ;
      RECT 0 246.435 0.07 246.505 ;
    END
  END w0_wd_in[288]
  PIN w0_wd_in[289]
    DIRECTION INPUT ;
    USE SIGNAL ;
    SHAPE ABUTMENT ;
    PORT
      LAYER M3_m ;
      RECT 0 247.135 0.07 247.205 ;
    END
  END w0_wd_in[289]
  PIN w0_wd_in[290]
    DIRECTION INPUT ;
    USE SIGNAL ;
    SHAPE ABUTMENT ;
    PORT
      LAYER M3_m ;
      RECT 0 247.835 0.07 247.905 ;
    END
  END w0_wd_in[290]
  PIN w0_wd_in[291]
    DIRECTION INPUT ;
    USE SIGNAL ;
    SHAPE ABUTMENT ;
    PORT
      LAYER M3_m ;
      RECT 0 248.535 0.07 248.605 ;
    END
  END w0_wd_in[291]
  PIN w0_wd_in[292]
    DIRECTION INPUT ;
    USE SIGNAL ;
    SHAPE ABUTMENT ;
    PORT
      LAYER M3_m ;
      RECT 0 249.235 0.07 249.305 ;
    END
  END w0_wd_in[292]
  PIN w0_wd_in[293]
    DIRECTION INPUT ;
    USE SIGNAL ;
    SHAPE ABUTMENT ;
    PORT
      LAYER M3_m ;
      RECT 0 249.935 0.07 250.005 ;
    END
  END w0_wd_in[293]
  PIN w0_wd_in[294]
    DIRECTION INPUT ;
    USE SIGNAL ;
    SHAPE ABUTMENT ;
    PORT
      LAYER M3_m ;
      RECT 0 250.635 0.07 250.705 ;
    END
  END w0_wd_in[294]
  PIN w0_wd_in[295]
    DIRECTION INPUT ;
    USE SIGNAL ;
    SHAPE ABUTMENT ;
    PORT
      LAYER M3_m ;
      RECT 0 251.335 0.07 251.405 ;
    END
  END w0_wd_in[295]
  PIN w0_wd_in[296]
    DIRECTION INPUT ;
    USE SIGNAL ;
    SHAPE ABUTMENT ;
    PORT
      LAYER M3_m ;
      RECT 0 252.035 0.07 252.105 ;
    END
  END w0_wd_in[296]
  PIN w0_wd_in[297]
    DIRECTION INPUT ;
    USE SIGNAL ;
    SHAPE ABUTMENT ;
    PORT
      LAYER M3_m ;
      RECT 0 252.735 0.07 252.805 ;
    END
  END w0_wd_in[297]
  PIN w0_wd_in[298]
    DIRECTION INPUT ;
    USE SIGNAL ;
    SHAPE ABUTMENT ;
    PORT
      LAYER M3_m ;
      RECT 0 253.435 0.07 253.505 ;
    END
  END w0_wd_in[298]
  PIN w0_wd_in[299]
    DIRECTION INPUT ;
    USE SIGNAL ;
    SHAPE ABUTMENT ;
    PORT
      LAYER M3_m ;
      RECT 0 254.135 0.07 254.205 ;
    END
  END w0_wd_in[299]
  PIN w0_wd_in[300]
    DIRECTION INPUT ;
    USE SIGNAL ;
    SHAPE ABUTMENT ;
    PORT
      LAYER M3_m ;
      RECT 0 254.835 0.07 254.905 ;
    END
  END w0_wd_in[300]
  PIN w0_wd_in[301]
    DIRECTION INPUT ;
    USE SIGNAL ;
    SHAPE ABUTMENT ;
    PORT
      LAYER M3_m ;
      RECT 0 255.535 0.07 255.605 ;
    END
  END w0_wd_in[301]
  PIN w0_wd_in[302]
    DIRECTION INPUT ;
    USE SIGNAL ;
    SHAPE ABUTMENT ;
    PORT
      LAYER M3_m ;
      RECT 0 256.235 0.07 256.305 ;
    END
  END w0_wd_in[302]
  PIN w0_wd_in[303]
    DIRECTION INPUT ;
    USE SIGNAL ;
    SHAPE ABUTMENT ;
    PORT
      LAYER M3_m ;
      RECT 0 256.935 0.07 257.005 ;
    END
  END w0_wd_in[303]
  PIN w0_wd_in[304]
    DIRECTION INPUT ;
    USE SIGNAL ;
    SHAPE ABUTMENT ;
    PORT
      LAYER M3_m ;
      RECT 0 257.635 0.07 257.705 ;
    END
  END w0_wd_in[304]
  PIN w0_wd_in[305]
    DIRECTION INPUT ;
    USE SIGNAL ;
    SHAPE ABUTMENT ;
    PORT
      LAYER M3_m ;
      RECT 0 258.335 0.07 258.405 ;
    END
  END w0_wd_in[305]
  PIN w0_wd_in[306]
    DIRECTION INPUT ;
    USE SIGNAL ;
    SHAPE ABUTMENT ;
    PORT
      LAYER M3_m ;
      RECT 0 259.035 0.07 259.105 ;
    END
  END w0_wd_in[306]
  PIN w0_wd_in[307]
    DIRECTION INPUT ;
    USE SIGNAL ;
    SHAPE ABUTMENT ;
    PORT
      LAYER M3_m ;
      RECT 0 259.735 0.07 259.805 ;
    END
  END w0_wd_in[307]
  PIN w0_wd_in[308]
    DIRECTION INPUT ;
    USE SIGNAL ;
    SHAPE ABUTMENT ;
    PORT
      LAYER M3_m ;
      RECT 0 260.435 0.07 260.505 ;
    END
  END w0_wd_in[308]
  PIN w0_wd_in[309]
    DIRECTION INPUT ;
    USE SIGNAL ;
    SHAPE ABUTMENT ;
    PORT
      LAYER M3_m ;
      RECT 0 261.135 0.07 261.205 ;
    END
  END w0_wd_in[309]
  PIN w0_wd_in[310]
    DIRECTION INPUT ;
    USE SIGNAL ;
    SHAPE ABUTMENT ;
    PORT
      LAYER M3_m ;
      RECT 0 261.835 0.07 261.905 ;
    END
  END w0_wd_in[310]
  PIN w0_wd_in[311]
    DIRECTION INPUT ;
    USE SIGNAL ;
    SHAPE ABUTMENT ;
    PORT
      LAYER M3_m ;
      RECT 0 262.535 0.07 262.605 ;
    END
  END w0_wd_in[311]
  PIN w0_wd_in[312]
    DIRECTION INPUT ;
    USE SIGNAL ;
    SHAPE ABUTMENT ;
    PORT
      LAYER M3_m ;
      RECT 0 263.235 0.07 263.305 ;
    END
  END w0_wd_in[312]
  PIN w0_wd_in[313]
    DIRECTION INPUT ;
    USE SIGNAL ;
    SHAPE ABUTMENT ;
    PORT
      LAYER M3_m ;
      RECT 0 263.935 0.07 264.005 ;
    END
  END w0_wd_in[313]
  PIN w0_wd_in[314]
    DIRECTION INPUT ;
    USE SIGNAL ;
    SHAPE ABUTMENT ;
    PORT
      LAYER M3_m ;
      RECT 0 264.635 0.07 264.705 ;
    END
  END w0_wd_in[314]
  PIN w0_wd_in[315]
    DIRECTION INPUT ;
    USE SIGNAL ;
    SHAPE ABUTMENT ;
    PORT
      LAYER M3_m ;
      RECT 0 265.335 0.07 265.405 ;
    END
  END w0_wd_in[315]
  PIN w0_wd_in[316]
    DIRECTION INPUT ;
    USE SIGNAL ;
    SHAPE ABUTMENT ;
    PORT
      LAYER M3_m ;
      RECT 0 266.035 0.07 266.105 ;
    END
  END w0_wd_in[316]
  PIN w0_wd_in[317]
    DIRECTION INPUT ;
    USE SIGNAL ;
    SHAPE ABUTMENT ;
    PORT
      LAYER M3_m ;
      RECT 0 266.735 0.07 266.805 ;
    END
  END w0_wd_in[317]
  PIN w0_wd_in[318]
    DIRECTION INPUT ;
    USE SIGNAL ;
    SHAPE ABUTMENT ;
    PORT
      LAYER M3_m ;
      RECT 0 267.435 0.07 267.505 ;
    END
  END w0_wd_in[318]
  PIN w0_wd_in[319]
    DIRECTION INPUT ;
    USE SIGNAL ;
    SHAPE ABUTMENT ;
    PORT
      LAYER M3_m ;
      RECT 0 268.135 0.07 268.205 ;
    END
  END w0_wd_in[319]
  PIN w0_wd_in[320]
    DIRECTION INPUT ;
    USE SIGNAL ;
    SHAPE ABUTMENT ;
    PORT
      LAYER M3_m ;
      RECT 0 268.835 0.07 268.905 ;
    END
  END w0_wd_in[320]
  PIN w0_wd_in[321]
    DIRECTION INPUT ;
    USE SIGNAL ;
    SHAPE ABUTMENT ;
    PORT
      LAYER M3_m ;
      RECT 0 269.535 0.07 269.605 ;
    END
  END w0_wd_in[321]
  PIN w0_wd_in[322]
    DIRECTION INPUT ;
    USE SIGNAL ;
    SHAPE ABUTMENT ;
    PORT
      LAYER M3_m ;
      RECT 0 270.235 0.07 270.305 ;
    END
  END w0_wd_in[322]
  PIN w0_wd_in[323]
    DIRECTION INPUT ;
    USE SIGNAL ;
    SHAPE ABUTMENT ;
    PORT
      LAYER M3_m ;
      RECT 0 270.935 0.07 271.005 ;
    END
  END w0_wd_in[323]
  PIN w0_wd_in[324]
    DIRECTION INPUT ;
    USE SIGNAL ;
    SHAPE ABUTMENT ;
    PORT
      LAYER M3_m ;
      RECT 0 271.635 0.07 271.705 ;
    END
  END w0_wd_in[324]
  PIN w0_wd_in[325]
    DIRECTION INPUT ;
    USE SIGNAL ;
    SHAPE ABUTMENT ;
    PORT
      LAYER M3_m ;
      RECT 0 272.335 0.07 272.405 ;
    END
  END w0_wd_in[325]
  PIN w0_wd_in[326]
    DIRECTION INPUT ;
    USE SIGNAL ;
    SHAPE ABUTMENT ;
    PORT
      LAYER M3_m ;
      RECT 0 273.035 0.07 273.105 ;
    END
  END w0_wd_in[326]
  PIN w0_wd_in[327]
    DIRECTION INPUT ;
    USE SIGNAL ;
    SHAPE ABUTMENT ;
    PORT
      LAYER M3_m ;
      RECT 0 273.735 0.07 273.805 ;
    END
  END w0_wd_in[327]
  PIN w0_wd_in[328]
    DIRECTION INPUT ;
    USE SIGNAL ;
    SHAPE ABUTMENT ;
    PORT
      LAYER M3_m ;
      RECT 0 274.435 0.07 274.505 ;
    END
  END w0_wd_in[328]
  PIN w0_wd_in[329]
    DIRECTION INPUT ;
    USE SIGNAL ;
    SHAPE ABUTMENT ;
    PORT
      LAYER M3_m ;
      RECT 0 275.135 0.07 275.205 ;
    END
  END w0_wd_in[329]
  PIN w0_wd_in[330]
    DIRECTION INPUT ;
    USE SIGNAL ;
    SHAPE ABUTMENT ;
    PORT
      LAYER M3_m ;
      RECT 0 275.835 0.07 275.905 ;
    END
  END w0_wd_in[330]
  PIN w0_wd_in[331]
    DIRECTION INPUT ;
    USE SIGNAL ;
    SHAPE ABUTMENT ;
    PORT
      LAYER M3_m ;
      RECT 0 276.535 0.07 276.605 ;
    END
  END w0_wd_in[331]
  PIN w0_wd_in[332]
    DIRECTION INPUT ;
    USE SIGNAL ;
    SHAPE ABUTMENT ;
    PORT
      LAYER M3_m ;
      RECT 0 277.235 0.07 277.305 ;
    END
  END w0_wd_in[332]
  PIN w0_wd_in[333]
    DIRECTION INPUT ;
    USE SIGNAL ;
    SHAPE ABUTMENT ;
    PORT
      LAYER M3_m ;
      RECT 0 277.935 0.07 278.005 ;
    END
  END w0_wd_in[333]
  PIN w0_wd_in[334]
    DIRECTION INPUT ;
    USE SIGNAL ;
    SHAPE ABUTMENT ;
    PORT
      LAYER M3_m ;
      RECT 0 278.635 0.07 278.705 ;
    END
  END w0_wd_in[334]
  PIN w0_wd_in[335]
    DIRECTION INPUT ;
    USE SIGNAL ;
    SHAPE ABUTMENT ;
    PORT
      LAYER M3_m ;
      RECT 0 279.335 0.07 279.405 ;
    END
  END w0_wd_in[335]
  PIN w0_wd_in[336]
    DIRECTION INPUT ;
    USE SIGNAL ;
    SHAPE ABUTMENT ;
    PORT
      LAYER M3_m ;
      RECT 0 280.035 0.07 280.105 ;
    END
  END w0_wd_in[336]
  PIN w0_wd_in[337]
    DIRECTION INPUT ;
    USE SIGNAL ;
    SHAPE ABUTMENT ;
    PORT
      LAYER M3_m ;
      RECT 0 280.735 0.07 280.805 ;
    END
  END w0_wd_in[337]
  PIN w0_wd_in[338]
    DIRECTION INPUT ;
    USE SIGNAL ;
    SHAPE ABUTMENT ;
    PORT
      LAYER M3_m ;
      RECT 0 281.435 0.07 281.505 ;
    END
  END w0_wd_in[338]
  PIN w0_wd_in[339]
    DIRECTION INPUT ;
    USE SIGNAL ;
    SHAPE ABUTMENT ;
    PORT
      LAYER M3_m ;
      RECT 0 282.135 0.07 282.205 ;
    END
  END w0_wd_in[339]
  PIN w0_wd_in[340]
    DIRECTION INPUT ;
    USE SIGNAL ;
    SHAPE ABUTMENT ;
    PORT
      LAYER M3_m ;
      RECT 0 282.835 0.07 282.905 ;
    END
  END w0_wd_in[340]
  PIN w0_wd_in[341]
    DIRECTION INPUT ;
    USE SIGNAL ;
    SHAPE ABUTMENT ;
    PORT
      LAYER M3_m ;
      RECT 0 283.535 0.07 283.605 ;
    END
  END w0_wd_in[341]
  PIN w0_wd_in[342]
    DIRECTION INPUT ;
    USE SIGNAL ;
    SHAPE ABUTMENT ;
    PORT
      LAYER M3_m ;
      RECT 0 284.235 0.07 284.305 ;
    END
  END w0_wd_in[342]
  PIN w0_wd_in[343]
    DIRECTION INPUT ;
    USE SIGNAL ;
    SHAPE ABUTMENT ;
    PORT
      LAYER M3_m ;
      RECT 0 284.935 0.07 285.005 ;
    END
  END w0_wd_in[343]
  PIN w0_wd_in[344]
    DIRECTION INPUT ;
    USE SIGNAL ;
    SHAPE ABUTMENT ;
    PORT
      LAYER M3_m ;
      RECT 0 285.635 0.07 285.705 ;
    END
  END w0_wd_in[344]
  PIN w0_wd_in[345]
    DIRECTION INPUT ;
    USE SIGNAL ;
    SHAPE ABUTMENT ;
    PORT
      LAYER M3_m ;
      RECT 0 286.335 0.07 286.405 ;
    END
  END w0_wd_in[345]
  PIN w0_wd_in[346]
    DIRECTION INPUT ;
    USE SIGNAL ;
    SHAPE ABUTMENT ;
    PORT
      LAYER M3_m ;
      RECT 0 287.035 0.07 287.105 ;
    END
  END w0_wd_in[346]
  PIN w0_wd_in[347]
    DIRECTION INPUT ;
    USE SIGNAL ;
    SHAPE ABUTMENT ;
    PORT
      LAYER M3_m ;
      RECT 0 287.735 0.07 287.805 ;
    END
  END w0_wd_in[347]
  PIN w0_wd_in[348]
    DIRECTION INPUT ;
    USE SIGNAL ;
    SHAPE ABUTMENT ;
    PORT
      LAYER M3_m ;
      RECT 0 288.435 0.07 288.505 ;
    END
  END w0_wd_in[348]
  PIN w0_wd_in[349]
    DIRECTION INPUT ;
    USE SIGNAL ;
    SHAPE ABUTMENT ;
    PORT
      LAYER M3_m ;
      RECT 0 289.135 0.07 289.205 ;
    END
  END w0_wd_in[349]
  PIN w0_wd_in[350]
    DIRECTION INPUT ;
    USE SIGNAL ;
    SHAPE ABUTMENT ;
    PORT
      LAYER M3_m ;
      RECT 0 289.835 0.07 289.905 ;
    END
  END w0_wd_in[350]
  PIN w0_wd_in[351]
    DIRECTION INPUT ;
    USE SIGNAL ;
    SHAPE ABUTMENT ;
    PORT
      LAYER M3_m ;
      RECT 0 290.535 0.07 290.605 ;
    END
  END w0_wd_in[351]
  PIN w0_wd_in[352]
    DIRECTION INPUT ;
    USE SIGNAL ;
    SHAPE ABUTMENT ;
    PORT
      LAYER M3_m ;
      RECT 0 291.235 0.07 291.305 ;
    END
  END w0_wd_in[352]
  PIN w0_wd_in[353]
    DIRECTION INPUT ;
    USE SIGNAL ;
    SHAPE ABUTMENT ;
    PORT
      LAYER M3_m ;
      RECT 0 291.935 0.07 292.005 ;
    END
  END w0_wd_in[353]
  PIN w0_wd_in[354]
    DIRECTION INPUT ;
    USE SIGNAL ;
    SHAPE ABUTMENT ;
    PORT
      LAYER M3_m ;
      RECT 0 292.635 0.07 292.705 ;
    END
  END w0_wd_in[354]
  PIN w0_wd_in[355]
    DIRECTION INPUT ;
    USE SIGNAL ;
    SHAPE ABUTMENT ;
    PORT
      LAYER M3_m ;
      RECT 0 293.335 0.07 293.405 ;
    END
  END w0_wd_in[355]
  PIN w0_wd_in[356]
    DIRECTION INPUT ;
    USE SIGNAL ;
    SHAPE ABUTMENT ;
    PORT
      LAYER M3_m ;
      RECT 0 294.035 0.07 294.105 ;
    END
  END w0_wd_in[356]
  PIN w0_wd_in[357]
    DIRECTION INPUT ;
    USE SIGNAL ;
    SHAPE ABUTMENT ;
    PORT
      LAYER M3_m ;
      RECT 0 294.735 0.07 294.805 ;
    END
  END w0_wd_in[357]
  PIN w0_wd_in[358]
    DIRECTION INPUT ;
    USE SIGNAL ;
    SHAPE ABUTMENT ;
    PORT
      LAYER M3_m ;
      RECT 0 295.435 0.07 295.505 ;
    END
  END w0_wd_in[358]
  PIN w0_wd_in[359]
    DIRECTION INPUT ;
    USE SIGNAL ;
    SHAPE ABUTMENT ;
    PORT
      LAYER M3_m ;
      RECT 0 296.135 0.07 296.205 ;
    END
  END w0_wd_in[359]
  PIN w0_wd_in[360]
    DIRECTION INPUT ;
    USE SIGNAL ;
    SHAPE ABUTMENT ;
    PORT
      LAYER M3_m ;
      RECT 0 296.835 0.07 296.905 ;
    END
  END w0_wd_in[360]
  PIN w0_wd_in[361]
    DIRECTION INPUT ;
    USE SIGNAL ;
    SHAPE ABUTMENT ;
    PORT
      LAYER M3_m ;
      RECT 0 297.535 0.07 297.605 ;
    END
  END w0_wd_in[361]
  PIN w0_wd_in[362]
    DIRECTION INPUT ;
    USE SIGNAL ;
    SHAPE ABUTMENT ;
    PORT
      LAYER M3_m ;
      RECT 0 298.235 0.07 298.305 ;
    END
  END w0_wd_in[362]
  PIN w0_wd_in[363]
    DIRECTION INPUT ;
    USE SIGNAL ;
    SHAPE ABUTMENT ;
    PORT
      LAYER M3_m ;
      RECT 0 298.935 0.07 299.005 ;
    END
  END w0_wd_in[363]
  PIN w0_wd_in[364]
    DIRECTION INPUT ;
    USE SIGNAL ;
    SHAPE ABUTMENT ;
    PORT
      LAYER M3_m ;
      RECT 0 299.635 0.07 299.705 ;
    END
  END w0_wd_in[364]
  PIN w0_wd_in[365]
    DIRECTION INPUT ;
    USE SIGNAL ;
    SHAPE ABUTMENT ;
    PORT
      LAYER M3_m ;
      RECT 0 300.335 0.07 300.405 ;
    END
  END w0_wd_in[365]
  PIN w0_wd_in[366]
    DIRECTION INPUT ;
    USE SIGNAL ;
    SHAPE ABUTMENT ;
    PORT
      LAYER M3_m ;
      RECT 0 301.035 0.07 301.105 ;
    END
  END w0_wd_in[366]
  PIN w0_wd_in[367]
    DIRECTION INPUT ;
    USE SIGNAL ;
    SHAPE ABUTMENT ;
    PORT
      LAYER M3_m ;
      RECT 0 301.735 0.07 301.805 ;
    END
  END w0_wd_in[367]
  PIN w0_wd_in[368]
    DIRECTION INPUT ;
    USE SIGNAL ;
    SHAPE ABUTMENT ;
    PORT
      LAYER M3_m ;
      RECT 0 302.435 0.07 302.505 ;
    END
  END w0_wd_in[368]
  PIN w0_wd_in[369]
    DIRECTION INPUT ;
    USE SIGNAL ;
    SHAPE ABUTMENT ;
    PORT
      LAYER M3_m ;
      RECT 0 303.135 0.07 303.205 ;
    END
  END w0_wd_in[369]
  PIN w0_wd_in[370]
    DIRECTION INPUT ;
    USE SIGNAL ;
    SHAPE ABUTMENT ;
    PORT
      LAYER M3_m ;
      RECT 0 303.835 0.07 303.905 ;
    END
  END w0_wd_in[370]
  PIN w0_wd_in[371]
    DIRECTION INPUT ;
    USE SIGNAL ;
    SHAPE ABUTMENT ;
    PORT
      LAYER M3_m ;
      RECT 0 304.535 0.07 304.605 ;
    END
  END w0_wd_in[371]
  PIN w0_wd_in[372]
    DIRECTION INPUT ;
    USE SIGNAL ;
    SHAPE ABUTMENT ;
    PORT
      LAYER M3_m ;
      RECT 0 305.235 0.07 305.305 ;
    END
  END w0_wd_in[372]
  PIN w0_wd_in[373]
    DIRECTION INPUT ;
    USE SIGNAL ;
    SHAPE ABUTMENT ;
    PORT
      LAYER M3_m ;
      RECT 0 305.935 0.07 306.005 ;
    END
  END w0_wd_in[373]
  PIN w0_wd_in[374]
    DIRECTION INPUT ;
    USE SIGNAL ;
    SHAPE ABUTMENT ;
    PORT
      LAYER M3_m ;
      RECT 0 306.635 0.07 306.705 ;
    END
  END w0_wd_in[374]
  PIN w0_wd_in[375]
    DIRECTION INPUT ;
    USE SIGNAL ;
    SHAPE ABUTMENT ;
    PORT
      LAYER M3_m ;
      RECT 0 307.335 0.07 307.405 ;
    END
  END w0_wd_in[375]
  PIN w0_wd_in[376]
    DIRECTION INPUT ;
    USE SIGNAL ;
    SHAPE ABUTMENT ;
    PORT
      LAYER M3_m ;
      RECT 0 308.035 0.07 308.105 ;
    END
  END w0_wd_in[376]
  PIN w0_wd_in[377]
    DIRECTION INPUT ;
    USE SIGNAL ;
    SHAPE ABUTMENT ;
    PORT
      LAYER M3_m ;
      RECT 0 308.735 0.07 308.805 ;
    END
  END w0_wd_in[377]
  PIN w0_wd_in[378]
    DIRECTION INPUT ;
    USE SIGNAL ;
    SHAPE ABUTMENT ;
    PORT
      LAYER M3_m ;
      RECT 0 309.435 0.07 309.505 ;
    END
  END w0_wd_in[378]
  PIN w0_wd_in[379]
    DIRECTION INPUT ;
    USE SIGNAL ;
    SHAPE ABUTMENT ;
    PORT
      LAYER M3_m ;
      RECT 0 310.135 0.07 310.205 ;
    END
  END w0_wd_in[379]
  PIN w0_wd_in[380]
    DIRECTION INPUT ;
    USE SIGNAL ;
    SHAPE ABUTMENT ;
    PORT
      LAYER M3_m ;
      RECT 0 310.835 0.07 310.905 ;
    END
  END w0_wd_in[380]
  PIN w0_wd_in[381]
    DIRECTION INPUT ;
    USE SIGNAL ;
    SHAPE ABUTMENT ;
    PORT
      LAYER M3_m ;
      RECT 0 311.535 0.07 311.605 ;
    END
  END w0_wd_in[381]
  PIN w0_wd_in[382]
    DIRECTION INPUT ;
    USE SIGNAL ;
    SHAPE ABUTMENT ;
    PORT
      LAYER M3_m ;
      RECT 0 312.235 0.07 312.305 ;
    END
  END w0_wd_in[382]
  PIN w0_wd_in[383]
    DIRECTION INPUT ;
    USE SIGNAL ;
    SHAPE ABUTMENT ;
    PORT
      LAYER M3_m ;
      RECT 0 312.935 0.07 313.005 ;
    END
  END w0_wd_in[383]
  PIN w0_wd_in[384]
    DIRECTION INPUT ;
    USE SIGNAL ;
    SHAPE ABUTMENT ;
    PORT
      LAYER M3_m ;
      RECT 0 313.635 0.07 313.705 ;
    END
  END w0_wd_in[384]
  PIN w0_wd_in[385]
    DIRECTION INPUT ;
    USE SIGNAL ;
    SHAPE ABUTMENT ;
    PORT
      LAYER M3_m ;
      RECT 0 314.335 0.07 314.405 ;
    END
  END w0_wd_in[385]
  PIN w0_wd_in[386]
    DIRECTION INPUT ;
    USE SIGNAL ;
    SHAPE ABUTMENT ;
    PORT
      LAYER M3_m ;
      RECT 0 315.035 0.07 315.105 ;
    END
  END w0_wd_in[386]
  PIN w0_wd_in[387]
    DIRECTION INPUT ;
    USE SIGNAL ;
    SHAPE ABUTMENT ;
    PORT
      LAYER M3_m ;
      RECT 0 315.735 0.07 315.805 ;
    END
  END w0_wd_in[387]
  PIN w0_wd_in[388]
    DIRECTION INPUT ;
    USE SIGNAL ;
    SHAPE ABUTMENT ;
    PORT
      LAYER M3_m ;
      RECT 0 316.435 0.07 316.505 ;
    END
  END w0_wd_in[388]
  PIN w0_wd_in[389]
    DIRECTION INPUT ;
    USE SIGNAL ;
    SHAPE ABUTMENT ;
    PORT
      LAYER M3_m ;
      RECT 0 317.135 0.07 317.205 ;
    END
  END w0_wd_in[389]
  PIN w0_wd_in[390]
    DIRECTION INPUT ;
    USE SIGNAL ;
    SHAPE ABUTMENT ;
    PORT
      LAYER M3_m ;
      RECT 0 317.835 0.07 317.905 ;
    END
  END w0_wd_in[390]
  PIN w0_wd_in[391]
    DIRECTION INPUT ;
    USE SIGNAL ;
    SHAPE ABUTMENT ;
    PORT
      LAYER M3_m ;
      RECT 0 318.535 0.07 318.605 ;
    END
  END w0_wd_in[391]
  PIN w0_wd_in[392]
    DIRECTION INPUT ;
    USE SIGNAL ;
    SHAPE ABUTMENT ;
    PORT
      LAYER M3_m ;
      RECT 0 319.235 0.07 319.305 ;
    END
  END w0_wd_in[392]
  PIN w0_wd_in[393]
    DIRECTION INPUT ;
    USE SIGNAL ;
    SHAPE ABUTMENT ;
    PORT
      LAYER M3_m ;
      RECT 0 319.935 0.07 320.005 ;
    END
  END w0_wd_in[393]
  PIN w0_wd_in[394]
    DIRECTION INPUT ;
    USE SIGNAL ;
    SHAPE ABUTMENT ;
    PORT
      LAYER M3_m ;
      RECT 0 320.635 0.07 320.705 ;
    END
  END w0_wd_in[394]
  PIN w0_wd_in[395]
    DIRECTION INPUT ;
    USE SIGNAL ;
    SHAPE ABUTMENT ;
    PORT
      LAYER M3_m ;
      RECT 0 321.335 0.07 321.405 ;
    END
  END w0_wd_in[395]
  PIN w0_wd_in[396]
    DIRECTION INPUT ;
    USE SIGNAL ;
    SHAPE ABUTMENT ;
    PORT
      LAYER M3_m ;
      RECT 0 322.035 0.07 322.105 ;
    END
  END w0_wd_in[396]
  PIN w0_wd_in[397]
    DIRECTION INPUT ;
    USE SIGNAL ;
    SHAPE ABUTMENT ;
    PORT
      LAYER M3_m ;
      RECT 0 322.735 0.07 322.805 ;
    END
  END w0_wd_in[397]
  PIN w0_wd_in[398]
    DIRECTION INPUT ;
    USE SIGNAL ;
    SHAPE ABUTMENT ;
    PORT
      LAYER M3_m ;
      RECT 0 323.435 0.07 323.505 ;
    END
  END w0_wd_in[398]
  PIN w0_wd_in[399]
    DIRECTION INPUT ;
    USE SIGNAL ;
    SHAPE ABUTMENT ;
    PORT
      LAYER M3_m ;
      RECT 0 324.135 0.07 324.205 ;
    END
  END w0_wd_in[399]
  PIN w0_wd_in[400]
    DIRECTION INPUT ;
    USE SIGNAL ;
    SHAPE ABUTMENT ;
    PORT
      LAYER M3_m ;
      RECT 0 324.835 0.07 324.905 ;
    END
  END w0_wd_in[400]
  PIN w0_wd_in[401]
    DIRECTION INPUT ;
    USE SIGNAL ;
    SHAPE ABUTMENT ;
    PORT
      LAYER M3_m ;
      RECT 0 325.535 0.07 325.605 ;
    END
  END w0_wd_in[401]
  PIN w0_wd_in[402]
    DIRECTION INPUT ;
    USE SIGNAL ;
    SHAPE ABUTMENT ;
    PORT
      LAYER M3_m ;
      RECT 0 326.235 0.07 326.305 ;
    END
  END w0_wd_in[402]
  PIN w0_wd_in[403]
    DIRECTION INPUT ;
    USE SIGNAL ;
    SHAPE ABUTMENT ;
    PORT
      LAYER M3_m ;
      RECT 0 326.935 0.07 327.005 ;
    END
  END w0_wd_in[403]
  PIN w0_wd_in[404]
    DIRECTION INPUT ;
    USE SIGNAL ;
    SHAPE ABUTMENT ;
    PORT
      LAYER M3_m ;
      RECT 0 327.635 0.07 327.705 ;
    END
  END w0_wd_in[404]
  PIN w0_wd_in[405]
    DIRECTION INPUT ;
    USE SIGNAL ;
    SHAPE ABUTMENT ;
    PORT
      LAYER M3_m ;
      RECT 0 328.335 0.07 328.405 ;
    END
  END w0_wd_in[405]
  PIN w0_wd_in[406]
    DIRECTION INPUT ;
    USE SIGNAL ;
    SHAPE ABUTMENT ;
    PORT
      LAYER M3_m ;
      RECT 0 329.035 0.07 329.105 ;
    END
  END w0_wd_in[406]
  PIN w0_wd_in[407]
    DIRECTION INPUT ;
    USE SIGNAL ;
    SHAPE ABUTMENT ;
    PORT
      LAYER M3_m ;
      RECT 0 329.735 0.07 329.805 ;
    END
  END w0_wd_in[407]
  PIN w0_wd_in[408]
    DIRECTION INPUT ;
    USE SIGNAL ;
    SHAPE ABUTMENT ;
    PORT
      LAYER M3_m ;
      RECT 0 330.435 0.07 330.505 ;
    END
  END w0_wd_in[408]
  PIN w0_wd_in[409]
    DIRECTION INPUT ;
    USE SIGNAL ;
    SHAPE ABUTMENT ;
    PORT
      LAYER M3_m ;
      RECT 0 331.135 0.07 331.205 ;
    END
  END w0_wd_in[409]
  PIN w0_wd_in[410]
    DIRECTION INPUT ;
    USE SIGNAL ;
    SHAPE ABUTMENT ;
    PORT
      LAYER M3_m ;
      RECT 0 331.835 0.07 331.905 ;
    END
  END w0_wd_in[410]
  PIN w0_wd_in[411]
    DIRECTION INPUT ;
    USE SIGNAL ;
    SHAPE ABUTMENT ;
    PORT
      LAYER M3_m ;
      RECT 0 332.535 0.07 332.605 ;
    END
  END w0_wd_in[411]
  PIN w0_wd_in[412]
    DIRECTION INPUT ;
    USE SIGNAL ;
    SHAPE ABUTMENT ;
    PORT
      LAYER M3_m ;
      RECT 0 333.235 0.07 333.305 ;
    END
  END w0_wd_in[412]
  PIN w0_wd_in[413]
    DIRECTION INPUT ;
    USE SIGNAL ;
    SHAPE ABUTMENT ;
    PORT
      LAYER M3_m ;
      RECT 0 333.935 0.07 334.005 ;
    END
  END w0_wd_in[413]
  PIN w0_wd_in[414]
    DIRECTION INPUT ;
    USE SIGNAL ;
    SHAPE ABUTMENT ;
    PORT
      LAYER M3_m ;
      RECT 0 334.635 0.07 334.705 ;
    END
  END w0_wd_in[414]
  PIN w0_wd_in[415]
    DIRECTION INPUT ;
    USE SIGNAL ;
    SHAPE ABUTMENT ;
    PORT
      LAYER M3_m ;
      RECT 0 335.335 0.07 335.405 ;
    END
  END w0_wd_in[415]
  PIN w0_wd_in[416]
    DIRECTION INPUT ;
    USE SIGNAL ;
    SHAPE ABUTMENT ;
    PORT
      LAYER M3_m ;
      RECT 0 336.035 0.07 336.105 ;
    END
  END w0_wd_in[416]
  PIN w0_wd_in[417]
    DIRECTION INPUT ;
    USE SIGNAL ;
    SHAPE ABUTMENT ;
    PORT
      LAYER M3_m ;
      RECT 0 336.735 0.07 336.805 ;
    END
  END w0_wd_in[417]
  PIN w0_wd_in[418]
    DIRECTION INPUT ;
    USE SIGNAL ;
    SHAPE ABUTMENT ;
    PORT
      LAYER M3_m ;
      RECT 0 337.435 0.07 337.505 ;
    END
  END w0_wd_in[418]
  PIN w0_wd_in[419]
    DIRECTION INPUT ;
    USE SIGNAL ;
    SHAPE ABUTMENT ;
    PORT
      LAYER M3_m ;
      RECT 0 338.135 0.07 338.205 ;
    END
  END w0_wd_in[419]
  PIN w0_wd_in[420]
    DIRECTION INPUT ;
    USE SIGNAL ;
    SHAPE ABUTMENT ;
    PORT
      LAYER M3_m ;
      RECT 0 338.835 0.07 338.905 ;
    END
  END w0_wd_in[420]
  PIN w0_wd_in[421]
    DIRECTION INPUT ;
    USE SIGNAL ;
    SHAPE ABUTMENT ;
    PORT
      LAYER M3_m ;
      RECT 0 339.535 0.07 339.605 ;
    END
  END w0_wd_in[421]
  PIN w0_wd_in[422]
    DIRECTION INPUT ;
    USE SIGNAL ;
    SHAPE ABUTMENT ;
    PORT
      LAYER M3_m ;
      RECT 0 340.235 0.07 340.305 ;
    END
  END w0_wd_in[422]
  PIN w0_wd_in[423]
    DIRECTION INPUT ;
    USE SIGNAL ;
    SHAPE ABUTMENT ;
    PORT
      LAYER M3_m ;
      RECT 0 340.935 0.07 341.005 ;
    END
  END w0_wd_in[423]
  PIN w0_wd_in[424]
    DIRECTION INPUT ;
    USE SIGNAL ;
    SHAPE ABUTMENT ;
    PORT
      LAYER M3_m ;
      RECT 0 341.635 0.07 341.705 ;
    END
  END w0_wd_in[424]
  PIN w0_wd_in[425]
    DIRECTION INPUT ;
    USE SIGNAL ;
    SHAPE ABUTMENT ;
    PORT
      LAYER M3_m ;
      RECT 0 342.335 0.07 342.405 ;
    END
  END w0_wd_in[425]
  PIN w0_wd_in[426]
    DIRECTION INPUT ;
    USE SIGNAL ;
    SHAPE ABUTMENT ;
    PORT
      LAYER M3_m ;
      RECT 0 343.035 0.07 343.105 ;
    END
  END w0_wd_in[426]
  PIN w0_wd_in[427]
    DIRECTION INPUT ;
    USE SIGNAL ;
    SHAPE ABUTMENT ;
    PORT
      LAYER M3_m ;
      RECT 0 343.735 0.07 343.805 ;
    END
  END w0_wd_in[427]
  PIN w0_wd_in[428]
    DIRECTION INPUT ;
    USE SIGNAL ;
    SHAPE ABUTMENT ;
    PORT
      LAYER M3_m ;
      RECT 0 344.435 0.07 344.505 ;
    END
  END w0_wd_in[428]
  PIN w0_wd_in[429]
    DIRECTION INPUT ;
    USE SIGNAL ;
    SHAPE ABUTMENT ;
    PORT
      LAYER M3_m ;
      RECT 0 345.135 0.07 345.205 ;
    END
  END w0_wd_in[429]
  PIN w0_wd_in[430]
    DIRECTION INPUT ;
    USE SIGNAL ;
    SHAPE ABUTMENT ;
    PORT
      LAYER M3_m ;
      RECT 0 345.835 0.07 345.905 ;
    END
  END w0_wd_in[430]
  PIN w0_wd_in[431]
    DIRECTION INPUT ;
    USE SIGNAL ;
    SHAPE ABUTMENT ;
    PORT
      LAYER M3_m ;
      RECT 0 346.535 0.07 346.605 ;
    END
  END w0_wd_in[431]
  PIN w0_wd_in[432]
    DIRECTION INPUT ;
    USE SIGNAL ;
    SHAPE ABUTMENT ;
    PORT
      LAYER M3_m ;
      RECT 0 347.235 0.07 347.305 ;
    END
  END w0_wd_in[432]
  PIN w0_wd_in[433]
    DIRECTION INPUT ;
    USE SIGNAL ;
    SHAPE ABUTMENT ;
    PORT
      LAYER M3_m ;
      RECT 0 347.935 0.07 348.005 ;
    END
  END w0_wd_in[433]
  PIN w0_wd_in[434]
    DIRECTION INPUT ;
    USE SIGNAL ;
    SHAPE ABUTMENT ;
    PORT
      LAYER M3_m ;
      RECT 0 348.635 0.07 348.705 ;
    END
  END w0_wd_in[434]
  PIN w0_wd_in[435]
    DIRECTION INPUT ;
    USE SIGNAL ;
    SHAPE ABUTMENT ;
    PORT
      LAYER M3_m ;
      RECT 0 349.335 0.07 349.405 ;
    END
  END w0_wd_in[435]
  PIN w0_wd_in[436]
    DIRECTION INPUT ;
    USE SIGNAL ;
    SHAPE ABUTMENT ;
    PORT
      LAYER M3_m ;
      RECT 0 350.035 0.07 350.105 ;
    END
  END w0_wd_in[436]
  PIN w0_wd_in[437]
    DIRECTION INPUT ;
    USE SIGNAL ;
    SHAPE ABUTMENT ;
    PORT
      LAYER M3_m ;
      RECT 0 350.735 0.07 350.805 ;
    END
  END w0_wd_in[437]
  PIN w0_wd_in[438]
    DIRECTION INPUT ;
    USE SIGNAL ;
    SHAPE ABUTMENT ;
    PORT
      LAYER M3_m ;
      RECT 0 351.435 0.07 351.505 ;
    END
  END w0_wd_in[438]
  PIN w0_wd_in[439]
    DIRECTION INPUT ;
    USE SIGNAL ;
    SHAPE ABUTMENT ;
    PORT
      LAYER M3_m ;
      RECT 0 352.135 0.07 352.205 ;
    END
  END w0_wd_in[439]
  PIN w0_wd_in[440]
    DIRECTION INPUT ;
    USE SIGNAL ;
    SHAPE ABUTMENT ;
    PORT
      LAYER M3_m ;
      RECT 0 352.835 0.07 352.905 ;
    END
  END w0_wd_in[440]
  PIN w0_wd_in[441]
    DIRECTION INPUT ;
    USE SIGNAL ;
    SHAPE ABUTMENT ;
    PORT
      LAYER M3_m ;
      RECT 0 353.535 0.07 353.605 ;
    END
  END w0_wd_in[441]
  PIN w0_wd_in[442]
    DIRECTION INPUT ;
    USE SIGNAL ;
    SHAPE ABUTMENT ;
    PORT
      LAYER M3_m ;
      RECT 0 354.235 0.07 354.305 ;
    END
  END w0_wd_in[442]
  PIN w0_wd_in[443]
    DIRECTION INPUT ;
    USE SIGNAL ;
    SHAPE ABUTMENT ;
    PORT
      LAYER M3_m ;
      RECT 0 354.935 0.07 355.005 ;
    END
  END w0_wd_in[443]
  PIN w0_wd_in[444]
    DIRECTION INPUT ;
    USE SIGNAL ;
    SHAPE ABUTMENT ;
    PORT
      LAYER M3_m ;
      RECT 0 355.635 0.07 355.705 ;
    END
  END w0_wd_in[444]
  PIN w0_wd_in[445]
    DIRECTION INPUT ;
    USE SIGNAL ;
    SHAPE ABUTMENT ;
    PORT
      LAYER M3_m ;
      RECT 0 356.335 0.07 356.405 ;
    END
  END w0_wd_in[445]
  PIN w0_wd_in[446]
    DIRECTION INPUT ;
    USE SIGNAL ;
    SHAPE ABUTMENT ;
    PORT
      LAYER M3_m ;
      RECT 0 357.035 0.07 357.105 ;
    END
  END w0_wd_in[446]
  PIN w0_wd_in[447]
    DIRECTION INPUT ;
    USE SIGNAL ;
    SHAPE ABUTMENT ;
    PORT
      LAYER M3_m ;
      RECT 0 357.735 0.07 357.805 ;
    END
  END w0_wd_in[447]
  PIN w0_wd_in[448]
    DIRECTION INPUT ;
    USE SIGNAL ;
    SHAPE ABUTMENT ;
    PORT
      LAYER M3_m ;
      RECT 0 358.435 0.07 358.505 ;
    END
  END w0_wd_in[448]
  PIN w0_wd_in[449]
    DIRECTION INPUT ;
    USE SIGNAL ;
    SHAPE ABUTMENT ;
    PORT
      LAYER M3_m ;
      RECT 0 359.135 0.07 359.205 ;
    END
  END w0_wd_in[449]
  PIN w0_wd_in[450]
    DIRECTION INPUT ;
    USE SIGNAL ;
    SHAPE ABUTMENT ;
    PORT
      LAYER M3_m ;
      RECT 0 359.835 0.07 359.905 ;
    END
  END w0_wd_in[450]
  PIN w0_wd_in[451]
    DIRECTION INPUT ;
    USE SIGNAL ;
    SHAPE ABUTMENT ;
    PORT
      LAYER M3_m ;
      RECT 0 360.535 0.07 360.605 ;
    END
  END w0_wd_in[451]
  PIN w0_wd_in[452]
    DIRECTION INPUT ;
    USE SIGNAL ;
    SHAPE ABUTMENT ;
    PORT
      LAYER M3_m ;
      RECT 0 361.235 0.07 361.305 ;
    END
  END w0_wd_in[452]
  PIN w0_wd_in[453]
    DIRECTION INPUT ;
    USE SIGNAL ;
    SHAPE ABUTMENT ;
    PORT
      LAYER M3_m ;
      RECT 0 361.935 0.07 362.005 ;
    END
  END w0_wd_in[453]
  PIN w0_wd_in[454]
    DIRECTION INPUT ;
    USE SIGNAL ;
    SHAPE ABUTMENT ;
    PORT
      LAYER M3_m ;
      RECT 0 362.635 0.07 362.705 ;
    END
  END w0_wd_in[454]
  PIN w0_wd_in[455]
    DIRECTION INPUT ;
    USE SIGNAL ;
    SHAPE ABUTMENT ;
    PORT
      LAYER M3_m ;
      RECT 0 363.335 0.07 363.405 ;
    END
  END w0_wd_in[455]
  PIN w0_wd_in[456]
    DIRECTION INPUT ;
    USE SIGNAL ;
    SHAPE ABUTMENT ;
    PORT
      LAYER M3_m ;
      RECT 0 364.035 0.07 364.105 ;
    END
  END w0_wd_in[456]
  PIN w0_wd_in[457]
    DIRECTION INPUT ;
    USE SIGNAL ;
    SHAPE ABUTMENT ;
    PORT
      LAYER M3_m ;
      RECT 0 364.735 0.07 364.805 ;
    END
  END w0_wd_in[457]
  PIN w0_wd_in[458]
    DIRECTION INPUT ;
    USE SIGNAL ;
    SHAPE ABUTMENT ;
    PORT
      LAYER M3_m ;
      RECT 0 365.435 0.07 365.505 ;
    END
  END w0_wd_in[458]
  PIN w0_wd_in[459]
    DIRECTION INPUT ;
    USE SIGNAL ;
    SHAPE ABUTMENT ;
    PORT
      LAYER M3_m ;
      RECT 0 366.135 0.07 366.205 ;
    END
  END w0_wd_in[459]
  PIN w0_wd_in[460]
    DIRECTION INPUT ;
    USE SIGNAL ;
    SHAPE ABUTMENT ;
    PORT
      LAYER M3_m ;
      RECT 0 366.835 0.07 366.905 ;
    END
  END w0_wd_in[460]
  PIN w0_wd_in[461]
    DIRECTION INPUT ;
    USE SIGNAL ;
    SHAPE ABUTMENT ;
    PORT
      LAYER M3_m ;
      RECT 0 367.535 0.07 367.605 ;
    END
  END w0_wd_in[461]
  PIN w0_wd_in[462]
    DIRECTION INPUT ;
    USE SIGNAL ;
    SHAPE ABUTMENT ;
    PORT
      LAYER M3_m ;
      RECT 0 368.235 0.07 368.305 ;
    END
  END w0_wd_in[462]
  PIN w0_wd_in[463]
    DIRECTION INPUT ;
    USE SIGNAL ;
    SHAPE ABUTMENT ;
    PORT
      LAYER M3_m ;
      RECT 0 368.935 0.07 369.005 ;
    END
  END w0_wd_in[463]
  PIN w0_wd_in[464]
    DIRECTION INPUT ;
    USE SIGNAL ;
    SHAPE ABUTMENT ;
    PORT
      LAYER M3_m ;
      RECT 0 369.635 0.07 369.705 ;
    END
  END w0_wd_in[464]
  PIN w0_wd_in[465]
    DIRECTION INPUT ;
    USE SIGNAL ;
    SHAPE ABUTMENT ;
    PORT
      LAYER M3_m ;
      RECT 0 370.335 0.07 370.405 ;
    END
  END w0_wd_in[465]
  PIN w0_wd_in[466]
    DIRECTION INPUT ;
    USE SIGNAL ;
    SHAPE ABUTMENT ;
    PORT
      LAYER M3_m ;
      RECT 0 371.035 0.07 371.105 ;
    END
  END w0_wd_in[466]
  PIN w0_wd_in[467]
    DIRECTION INPUT ;
    USE SIGNAL ;
    SHAPE ABUTMENT ;
    PORT
      LAYER M3_m ;
      RECT 0 371.735 0.07 371.805 ;
    END
  END w0_wd_in[467]
  PIN w0_wd_in[468]
    DIRECTION INPUT ;
    USE SIGNAL ;
    SHAPE ABUTMENT ;
    PORT
      LAYER M3_m ;
      RECT 0 372.435 0.07 372.505 ;
    END
  END w0_wd_in[468]
  PIN w0_wd_in[469]
    DIRECTION INPUT ;
    USE SIGNAL ;
    SHAPE ABUTMENT ;
    PORT
      LAYER M3_m ;
      RECT 0 373.135 0.07 373.205 ;
    END
  END w0_wd_in[469]
  PIN w0_wd_in[470]
    DIRECTION INPUT ;
    USE SIGNAL ;
    SHAPE ABUTMENT ;
    PORT
      LAYER M3_m ;
      RECT 0 373.835 0.07 373.905 ;
    END
  END w0_wd_in[470]
  PIN w0_wd_in[471]
    DIRECTION INPUT ;
    USE SIGNAL ;
    SHAPE ABUTMENT ;
    PORT
      LAYER M3_m ;
      RECT 0 374.535 0.07 374.605 ;
    END
  END w0_wd_in[471]
  PIN w0_wd_in[472]
    DIRECTION INPUT ;
    USE SIGNAL ;
    SHAPE ABUTMENT ;
    PORT
      LAYER M3_m ;
      RECT 0 375.235 0.07 375.305 ;
    END
  END w0_wd_in[472]
  PIN w0_wd_in[473]
    DIRECTION INPUT ;
    USE SIGNAL ;
    SHAPE ABUTMENT ;
    PORT
      LAYER M3_m ;
      RECT 0 375.935 0.07 376.005 ;
    END
  END w0_wd_in[473]
  PIN w0_wd_in[474]
    DIRECTION INPUT ;
    USE SIGNAL ;
    SHAPE ABUTMENT ;
    PORT
      LAYER M3_m ;
      RECT 0 376.635 0.07 376.705 ;
    END
  END w0_wd_in[474]
  PIN w0_wd_in[475]
    DIRECTION INPUT ;
    USE SIGNAL ;
    SHAPE ABUTMENT ;
    PORT
      LAYER M3_m ;
      RECT 0 377.335 0.07 377.405 ;
    END
  END w0_wd_in[475]
  PIN w0_wd_in[476]
    DIRECTION INPUT ;
    USE SIGNAL ;
    SHAPE ABUTMENT ;
    PORT
      LAYER M3_m ;
      RECT 0 378.035 0.07 378.105 ;
    END
  END w0_wd_in[476]
  PIN w0_wd_in[477]
    DIRECTION INPUT ;
    USE SIGNAL ;
    SHAPE ABUTMENT ;
    PORT
      LAYER M3_m ;
      RECT 0 378.735 0.07 378.805 ;
    END
  END w0_wd_in[477]
  PIN w0_wd_in[478]
    DIRECTION INPUT ;
    USE SIGNAL ;
    SHAPE ABUTMENT ;
    PORT
      LAYER M3_m ;
      RECT 0 379.435 0.07 379.505 ;
    END
  END w0_wd_in[478]
  PIN w0_wd_in[479]
    DIRECTION INPUT ;
    USE SIGNAL ;
    SHAPE ABUTMENT ;
    PORT
      LAYER M3_m ;
      RECT 0 380.135 0.07 380.205 ;
    END
  END w0_wd_in[479]
  PIN w0_wd_in[480]
    DIRECTION INPUT ;
    USE SIGNAL ;
    SHAPE ABUTMENT ;
    PORT
      LAYER M3_m ;
      RECT 0 380.835 0.07 380.905 ;
    END
  END w0_wd_in[480]
  PIN w0_wd_in[481]
    DIRECTION INPUT ;
    USE SIGNAL ;
    SHAPE ABUTMENT ;
    PORT
      LAYER M3_m ;
      RECT 0 381.535 0.07 381.605 ;
    END
  END w0_wd_in[481]
  PIN w0_wd_in[482]
    DIRECTION INPUT ;
    USE SIGNAL ;
    SHAPE ABUTMENT ;
    PORT
      LAYER M3_m ;
      RECT 0 382.235 0.07 382.305 ;
    END
  END w0_wd_in[482]
  PIN w0_wd_in[483]
    DIRECTION INPUT ;
    USE SIGNAL ;
    SHAPE ABUTMENT ;
    PORT
      LAYER M3_m ;
      RECT 0 382.935 0.07 383.005 ;
    END
  END w0_wd_in[483]
  PIN w0_wd_in[484]
    DIRECTION INPUT ;
    USE SIGNAL ;
    SHAPE ABUTMENT ;
    PORT
      LAYER M3_m ;
      RECT 0 383.635 0.07 383.705 ;
    END
  END w0_wd_in[484]
  PIN w0_wd_in[485]
    DIRECTION INPUT ;
    USE SIGNAL ;
    SHAPE ABUTMENT ;
    PORT
      LAYER M3_m ;
      RECT 0 384.335 0.07 384.405 ;
    END
  END w0_wd_in[485]
  PIN w0_wd_in[486]
    DIRECTION INPUT ;
    USE SIGNAL ;
    SHAPE ABUTMENT ;
    PORT
      LAYER M3_m ;
      RECT 0 385.035 0.07 385.105 ;
    END
  END w0_wd_in[486]
  PIN w0_wd_in[487]
    DIRECTION INPUT ;
    USE SIGNAL ;
    SHAPE ABUTMENT ;
    PORT
      LAYER M3_m ;
      RECT 0 385.735 0.07 385.805 ;
    END
  END w0_wd_in[487]
  PIN w0_wd_in[488]
    DIRECTION INPUT ;
    USE SIGNAL ;
    SHAPE ABUTMENT ;
    PORT
      LAYER M3_m ;
      RECT 0 386.435 0.07 386.505 ;
    END
  END w0_wd_in[488]
  PIN w0_wd_in[489]
    DIRECTION INPUT ;
    USE SIGNAL ;
    SHAPE ABUTMENT ;
    PORT
      LAYER M3_m ;
      RECT 0 387.135 0.07 387.205 ;
    END
  END w0_wd_in[489]
  PIN w0_wd_in[490]
    DIRECTION INPUT ;
    USE SIGNAL ;
    SHAPE ABUTMENT ;
    PORT
      LAYER M3_m ;
      RECT 0 387.835 0.07 387.905 ;
    END
  END w0_wd_in[490]
  PIN w0_wd_in[491]
    DIRECTION INPUT ;
    USE SIGNAL ;
    SHAPE ABUTMENT ;
    PORT
      LAYER M3_m ;
      RECT 0 388.535 0.07 388.605 ;
    END
  END w0_wd_in[491]
  PIN w0_wd_in[492]
    DIRECTION INPUT ;
    USE SIGNAL ;
    SHAPE ABUTMENT ;
    PORT
      LAYER M3_m ;
      RECT 0 389.235 0.07 389.305 ;
    END
  END w0_wd_in[492]
  PIN w0_wd_in[493]
    DIRECTION INPUT ;
    USE SIGNAL ;
    SHAPE ABUTMENT ;
    PORT
      LAYER M3_m ;
      RECT 0 389.935 0.07 390.005 ;
    END
  END w0_wd_in[493]
  PIN w0_wd_in[494]
    DIRECTION INPUT ;
    USE SIGNAL ;
    SHAPE ABUTMENT ;
    PORT
      LAYER M3_m ;
      RECT 0 390.635 0.07 390.705 ;
    END
  END w0_wd_in[494]
  PIN w0_wd_in[495]
    DIRECTION INPUT ;
    USE SIGNAL ;
    SHAPE ABUTMENT ;
    PORT
      LAYER M3_m ;
      RECT 0 391.335 0.07 391.405 ;
    END
  END w0_wd_in[495]
  PIN w0_wd_in[496]
    DIRECTION INPUT ;
    USE SIGNAL ;
    SHAPE ABUTMENT ;
    PORT
      LAYER M3_m ;
      RECT 0 392.035 0.07 392.105 ;
    END
  END w0_wd_in[496]
  PIN w0_wd_in[497]
    DIRECTION INPUT ;
    USE SIGNAL ;
    SHAPE ABUTMENT ;
    PORT
      LAYER M3_m ;
      RECT 0 392.735 0.07 392.805 ;
    END
  END w0_wd_in[497]
  PIN w0_wd_in[498]
    DIRECTION INPUT ;
    USE SIGNAL ;
    SHAPE ABUTMENT ;
    PORT
      LAYER M3_m ;
      RECT 0 393.435 0.07 393.505 ;
    END
  END w0_wd_in[498]
  PIN w0_wd_in[499]
    DIRECTION INPUT ;
    USE SIGNAL ;
    SHAPE ABUTMENT ;
    PORT
      LAYER M3_m ;
      RECT 0 394.135 0.07 394.205 ;
    END
  END w0_wd_in[499]
  PIN w0_wd_in[500]
    DIRECTION INPUT ;
    USE SIGNAL ;
    SHAPE ABUTMENT ;
    PORT
      LAYER M3_m ;
      RECT 0 394.835 0.07 394.905 ;
    END
  END w0_wd_in[500]
  PIN w0_wd_in[501]
    DIRECTION INPUT ;
    USE SIGNAL ;
    SHAPE ABUTMENT ;
    PORT
      LAYER M3_m ;
      RECT 0 395.535 0.07 395.605 ;
    END
  END w0_wd_in[501]
  PIN w0_wd_in[502]
    DIRECTION INPUT ;
    USE SIGNAL ;
    SHAPE ABUTMENT ;
    PORT
      LAYER M3_m ;
      RECT 0 396.235 0.07 396.305 ;
    END
  END w0_wd_in[502]
  PIN w0_wd_in[503]
    DIRECTION INPUT ;
    USE SIGNAL ;
    SHAPE ABUTMENT ;
    PORT
      LAYER M3_m ;
      RECT 0 396.935 0.07 397.005 ;
    END
  END w0_wd_in[503]
  PIN w0_wd_in[504]
    DIRECTION INPUT ;
    USE SIGNAL ;
    SHAPE ABUTMENT ;
    PORT
      LAYER M3_m ;
      RECT 0 397.635 0.07 397.705 ;
    END
  END w0_wd_in[504]
  PIN w0_wd_in[505]
    DIRECTION INPUT ;
    USE SIGNAL ;
    SHAPE ABUTMENT ;
    PORT
      LAYER M3_m ;
      RECT 0 398.335 0.07 398.405 ;
    END
  END w0_wd_in[505]
  PIN w0_wd_in[506]
    DIRECTION INPUT ;
    USE SIGNAL ;
    SHAPE ABUTMENT ;
    PORT
      LAYER M3_m ;
      RECT 0 399.035 0.07 399.105 ;
    END
  END w0_wd_in[506]
  PIN w0_wd_in[507]
    DIRECTION INPUT ;
    USE SIGNAL ;
    SHAPE ABUTMENT ;
    PORT
      LAYER M3_m ;
      RECT 0 399.735 0.07 399.805 ;
    END
  END w0_wd_in[507]
  PIN w0_wd_in[508]
    DIRECTION INPUT ;
    USE SIGNAL ;
    SHAPE ABUTMENT ;
    PORT
      LAYER M3_m ;
      RECT 0 400.435 0.07 400.505 ;
    END
  END w0_wd_in[508]
  PIN w0_wd_in[509]
    DIRECTION INPUT ;
    USE SIGNAL ;
    SHAPE ABUTMENT ;
    PORT
      LAYER M3_m ;
      RECT 0 401.135 0.07 401.205 ;
    END
  END w0_wd_in[509]
  PIN w0_wd_in[510]
    DIRECTION INPUT ;
    USE SIGNAL ;
    SHAPE ABUTMENT ;
    PORT
      LAYER M3_m ;
      RECT 0 401.835 0.07 401.905 ;
    END
  END w0_wd_in[510]
  PIN w0_wd_in[511]
    DIRECTION INPUT ;
    USE SIGNAL ;
    SHAPE ABUTMENT ;
    PORT
      LAYER M3_m ;
      RECT 0 402.535 0.07 402.605 ;
    END
  END w0_wd_in[511]
  PIN r0_rd_out[0]
    DIRECTION OUTPUT ;
    USE SIGNAL ;
    SHAPE ABUTMENT ;
    PORT
      LAYER M3_m ;
      RECT 0 403.235 0.07 403.305 ;
    END
  END r0_rd_out[0]
  PIN r0_rd_out[1]
    DIRECTION OUTPUT ;
    USE SIGNAL ;
    SHAPE ABUTMENT ;
    PORT
      LAYER M3_m ;
      RECT 0 403.935 0.07 404.005 ;
    END
  END r0_rd_out[1]
  PIN r0_rd_out[2]
    DIRECTION OUTPUT ;
    USE SIGNAL ;
    SHAPE ABUTMENT ;
    PORT
      LAYER M3_m ;
      RECT 0 404.635 0.07 404.705 ;
    END
  END r0_rd_out[2]
  PIN r0_rd_out[3]
    DIRECTION OUTPUT ;
    USE SIGNAL ;
    SHAPE ABUTMENT ;
    PORT
      LAYER M3_m ;
      RECT 0 405.335 0.07 405.405 ;
    END
  END r0_rd_out[3]
  PIN r0_rd_out[4]
    DIRECTION OUTPUT ;
    USE SIGNAL ;
    SHAPE ABUTMENT ;
    PORT
      LAYER M3_m ;
      RECT 0 406.035 0.07 406.105 ;
    END
  END r0_rd_out[4]
  PIN r0_rd_out[5]
    DIRECTION OUTPUT ;
    USE SIGNAL ;
    SHAPE ABUTMENT ;
    PORT
      LAYER M3_m ;
      RECT 0 406.735 0.07 406.805 ;
    END
  END r0_rd_out[5]
  PIN r0_rd_out[6]
    DIRECTION OUTPUT ;
    USE SIGNAL ;
    SHAPE ABUTMENT ;
    PORT
      LAYER M3_m ;
      RECT 0 407.435 0.07 407.505 ;
    END
  END r0_rd_out[6]
  PIN r0_rd_out[7]
    DIRECTION OUTPUT ;
    USE SIGNAL ;
    SHAPE ABUTMENT ;
    PORT
      LAYER M3_m ;
      RECT 0 408.135 0.07 408.205 ;
    END
  END r0_rd_out[7]
  PIN r0_rd_out[8]
    DIRECTION OUTPUT ;
    USE SIGNAL ;
    SHAPE ABUTMENT ;
    PORT
      LAYER M3_m ;
      RECT 0 408.835 0.07 408.905 ;
    END
  END r0_rd_out[8]
  PIN r0_rd_out[9]
    DIRECTION OUTPUT ;
    USE SIGNAL ;
    SHAPE ABUTMENT ;
    PORT
      LAYER M3_m ;
      RECT 0 409.535 0.07 409.605 ;
    END
  END r0_rd_out[9]
  PIN r0_rd_out[10]
    DIRECTION OUTPUT ;
    USE SIGNAL ;
    SHAPE ABUTMENT ;
    PORT
      LAYER M3_m ;
      RECT 0 410.235 0.07 410.305 ;
    END
  END r0_rd_out[10]
  PIN r0_rd_out[11]
    DIRECTION OUTPUT ;
    USE SIGNAL ;
    SHAPE ABUTMENT ;
    PORT
      LAYER M3_m ;
      RECT 0 410.935 0.07 411.005 ;
    END
  END r0_rd_out[11]
  PIN r0_rd_out[12]
    DIRECTION OUTPUT ;
    USE SIGNAL ;
    SHAPE ABUTMENT ;
    PORT
      LAYER M3_m ;
      RECT 0 411.635 0.07 411.705 ;
    END
  END r0_rd_out[12]
  PIN r0_rd_out[13]
    DIRECTION OUTPUT ;
    USE SIGNAL ;
    SHAPE ABUTMENT ;
    PORT
      LAYER M3_m ;
      RECT 0 412.335 0.07 412.405 ;
    END
  END r0_rd_out[13]
  PIN r0_rd_out[14]
    DIRECTION OUTPUT ;
    USE SIGNAL ;
    SHAPE ABUTMENT ;
    PORT
      LAYER M3_m ;
      RECT 0 413.035 0.07 413.105 ;
    END
  END r0_rd_out[14]
  PIN r0_rd_out[15]
    DIRECTION OUTPUT ;
    USE SIGNAL ;
    SHAPE ABUTMENT ;
    PORT
      LAYER M3_m ;
      RECT 0 413.735 0.07 413.805 ;
    END
  END r0_rd_out[15]
  PIN r0_rd_out[16]
    DIRECTION OUTPUT ;
    USE SIGNAL ;
    SHAPE ABUTMENT ;
    PORT
      LAYER M3_m ;
      RECT 0 414.435 0.07 414.505 ;
    END
  END r0_rd_out[16]
  PIN r0_rd_out[17]
    DIRECTION OUTPUT ;
    USE SIGNAL ;
    SHAPE ABUTMENT ;
    PORT
      LAYER M3_m ;
      RECT 0 415.135 0.07 415.205 ;
    END
  END r0_rd_out[17]
  PIN r0_rd_out[18]
    DIRECTION OUTPUT ;
    USE SIGNAL ;
    SHAPE ABUTMENT ;
    PORT
      LAYER M3_m ;
      RECT 0 415.835 0.07 415.905 ;
    END
  END r0_rd_out[18]
  PIN r0_rd_out[19]
    DIRECTION OUTPUT ;
    USE SIGNAL ;
    SHAPE ABUTMENT ;
    PORT
      LAYER M3_m ;
      RECT 0 416.535 0.07 416.605 ;
    END
  END r0_rd_out[19]
  PIN r0_rd_out[20]
    DIRECTION OUTPUT ;
    USE SIGNAL ;
    SHAPE ABUTMENT ;
    PORT
      LAYER M3_m ;
      RECT 0 417.235 0.07 417.305 ;
    END
  END r0_rd_out[20]
  PIN r0_rd_out[21]
    DIRECTION OUTPUT ;
    USE SIGNAL ;
    SHAPE ABUTMENT ;
    PORT
      LAYER M3_m ;
      RECT 0 417.935 0.07 418.005 ;
    END
  END r0_rd_out[21]
  PIN r0_rd_out[22]
    DIRECTION OUTPUT ;
    USE SIGNAL ;
    SHAPE ABUTMENT ;
    PORT
      LAYER M3_m ;
      RECT 0 418.635 0.07 418.705 ;
    END
  END r0_rd_out[22]
  PIN r0_rd_out[23]
    DIRECTION OUTPUT ;
    USE SIGNAL ;
    SHAPE ABUTMENT ;
    PORT
      LAYER M3_m ;
      RECT 0 419.335 0.07 419.405 ;
    END
  END r0_rd_out[23]
  PIN r0_rd_out[24]
    DIRECTION OUTPUT ;
    USE SIGNAL ;
    SHAPE ABUTMENT ;
    PORT
      LAYER M3_m ;
      RECT 0 420.035 0.07 420.105 ;
    END
  END r0_rd_out[24]
  PIN r0_rd_out[25]
    DIRECTION OUTPUT ;
    USE SIGNAL ;
    SHAPE ABUTMENT ;
    PORT
      LAYER M3_m ;
      RECT 0 420.735 0.07 420.805 ;
    END
  END r0_rd_out[25]
  PIN r0_rd_out[26]
    DIRECTION OUTPUT ;
    USE SIGNAL ;
    SHAPE ABUTMENT ;
    PORT
      LAYER M3_m ;
      RECT 0 421.435 0.07 421.505 ;
    END
  END r0_rd_out[26]
  PIN r0_rd_out[27]
    DIRECTION OUTPUT ;
    USE SIGNAL ;
    SHAPE ABUTMENT ;
    PORT
      LAYER M3_m ;
      RECT 0 422.135 0.07 422.205 ;
    END
  END r0_rd_out[27]
  PIN r0_rd_out[28]
    DIRECTION OUTPUT ;
    USE SIGNAL ;
    SHAPE ABUTMENT ;
    PORT
      LAYER M3_m ;
      RECT 0 422.835 0.07 422.905 ;
    END
  END r0_rd_out[28]
  PIN r0_rd_out[29]
    DIRECTION OUTPUT ;
    USE SIGNAL ;
    SHAPE ABUTMENT ;
    PORT
      LAYER M3_m ;
      RECT 0 423.535 0.07 423.605 ;
    END
  END r0_rd_out[29]
  PIN r0_rd_out[30]
    DIRECTION OUTPUT ;
    USE SIGNAL ;
    SHAPE ABUTMENT ;
    PORT
      LAYER M3_m ;
      RECT 0 424.235 0.07 424.305 ;
    END
  END r0_rd_out[30]
  PIN r0_rd_out[31]
    DIRECTION OUTPUT ;
    USE SIGNAL ;
    SHAPE ABUTMENT ;
    PORT
      LAYER M3_m ;
      RECT 0 424.935 0.07 425.005 ;
    END
  END r0_rd_out[31]
  PIN r0_rd_out[32]
    DIRECTION OUTPUT ;
    USE SIGNAL ;
    SHAPE ABUTMENT ;
    PORT
      LAYER M3_m ;
      RECT 0 425.635 0.07 425.705 ;
    END
  END r0_rd_out[32]
  PIN r0_rd_out[33]
    DIRECTION OUTPUT ;
    USE SIGNAL ;
    SHAPE ABUTMENT ;
    PORT
      LAYER M3_m ;
      RECT 0 426.335 0.07 426.405 ;
    END
  END r0_rd_out[33]
  PIN r0_rd_out[34]
    DIRECTION OUTPUT ;
    USE SIGNAL ;
    SHAPE ABUTMENT ;
    PORT
      LAYER M3_m ;
      RECT 0 427.035 0.07 427.105 ;
    END
  END r0_rd_out[34]
  PIN r0_rd_out[35]
    DIRECTION OUTPUT ;
    USE SIGNAL ;
    SHAPE ABUTMENT ;
    PORT
      LAYER M3_m ;
      RECT 0 427.735 0.07 427.805 ;
    END
  END r0_rd_out[35]
  PIN r0_rd_out[36]
    DIRECTION OUTPUT ;
    USE SIGNAL ;
    SHAPE ABUTMENT ;
    PORT
      LAYER M3_m ;
      RECT 0 428.435 0.07 428.505 ;
    END
  END r0_rd_out[36]
  PIN r0_rd_out[37]
    DIRECTION OUTPUT ;
    USE SIGNAL ;
    SHAPE ABUTMENT ;
    PORT
      LAYER M3_m ;
      RECT 0 429.135 0.07 429.205 ;
    END
  END r0_rd_out[37]
  PIN r0_rd_out[38]
    DIRECTION OUTPUT ;
    USE SIGNAL ;
    SHAPE ABUTMENT ;
    PORT
      LAYER M3_m ;
      RECT 0 429.835 0.07 429.905 ;
    END
  END r0_rd_out[38]
  PIN r0_rd_out[39]
    DIRECTION OUTPUT ;
    USE SIGNAL ;
    SHAPE ABUTMENT ;
    PORT
      LAYER M3_m ;
      RECT 0 430.535 0.07 430.605 ;
    END
  END r0_rd_out[39]
  PIN r0_rd_out[40]
    DIRECTION OUTPUT ;
    USE SIGNAL ;
    SHAPE ABUTMENT ;
    PORT
      LAYER M3_m ;
      RECT 0 431.235 0.07 431.305 ;
    END
  END r0_rd_out[40]
  PIN r0_rd_out[41]
    DIRECTION OUTPUT ;
    USE SIGNAL ;
    SHAPE ABUTMENT ;
    PORT
      LAYER M3_m ;
      RECT 0 431.935 0.07 432.005 ;
    END
  END r0_rd_out[41]
  PIN r0_rd_out[42]
    DIRECTION OUTPUT ;
    USE SIGNAL ;
    SHAPE ABUTMENT ;
    PORT
      LAYER M3_m ;
      RECT 0 432.635 0.07 432.705 ;
    END
  END r0_rd_out[42]
  PIN r0_rd_out[43]
    DIRECTION OUTPUT ;
    USE SIGNAL ;
    SHAPE ABUTMENT ;
    PORT
      LAYER M3_m ;
      RECT 0 433.335 0.07 433.405 ;
    END
  END r0_rd_out[43]
  PIN r0_rd_out[44]
    DIRECTION OUTPUT ;
    USE SIGNAL ;
    SHAPE ABUTMENT ;
    PORT
      LAYER M3_m ;
      RECT 0 434.035 0.07 434.105 ;
    END
  END r0_rd_out[44]
  PIN r0_rd_out[45]
    DIRECTION OUTPUT ;
    USE SIGNAL ;
    SHAPE ABUTMENT ;
    PORT
      LAYER M3_m ;
      RECT 0 434.735 0.07 434.805 ;
    END
  END r0_rd_out[45]
  PIN r0_rd_out[46]
    DIRECTION OUTPUT ;
    USE SIGNAL ;
    SHAPE ABUTMENT ;
    PORT
      LAYER M3_m ;
      RECT 0 435.435 0.07 435.505 ;
    END
  END r0_rd_out[46]
  PIN r0_rd_out[47]
    DIRECTION OUTPUT ;
    USE SIGNAL ;
    SHAPE ABUTMENT ;
    PORT
      LAYER M3_m ;
      RECT 0 436.135 0.07 436.205 ;
    END
  END r0_rd_out[47]
  PIN r0_rd_out[48]
    DIRECTION OUTPUT ;
    USE SIGNAL ;
    SHAPE ABUTMENT ;
    PORT
      LAYER M3_m ;
      RECT 0 436.835 0.07 436.905 ;
    END
  END r0_rd_out[48]
  PIN r0_rd_out[49]
    DIRECTION OUTPUT ;
    USE SIGNAL ;
    SHAPE ABUTMENT ;
    PORT
      LAYER M3_m ;
      RECT 0 437.535 0.07 437.605 ;
    END
  END r0_rd_out[49]
  PIN r0_rd_out[50]
    DIRECTION OUTPUT ;
    USE SIGNAL ;
    SHAPE ABUTMENT ;
    PORT
      LAYER M3_m ;
      RECT 0 438.235 0.07 438.305 ;
    END
  END r0_rd_out[50]
  PIN r0_rd_out[51]
    DIRECTION OUTPUT ;
    USE SIGNAL ;
    SHAPE ABUTMENT ;
    PORT
      LAYER M3_m ;
      RECT 0 438.935 0.07 439.005 ;
    END
  END r0_rd_out[51]
  PIN r0_rd_out[52]
    DIRECTION OUTPUT ;
    USE SIGNAL ;
    SHAPE ABUTMENT ;
    PORT
      LAYER M3_m ;
      RECT 0 439.635 0.07 439.705 ;
    END
  END r0_rd_out[52]
  PIN r0_rd_out[53]
    DIRECTION OUTPUT ;
    USE SIGNAL ;
    SHAPE ABUTMENT ;
    PORT
      LAYER M3_m ;
      RECT 0 440.335 0.07 440.405 ;
    END
  END r0_rd_out[53]
  PIN r0_rd_out[54]
    DIRECTION OUTPUT ;
    USE SIGNAL ;
    SHAPE ABUTMENT ;
    PORT
      LAYER M3_m ;
      RECT 0 441.035 0.07 441.105 ;
    END
  END r0_rd_out[54]
  PIN r0_rd_out[55]
    DIRECTION OUTPUT ;
    USE SIGNAL ;
    SHAPE ABUTMENT ;
    PORT
      LAYER M3_m ;
      RECT 0 441.735 0.07 441.805 ;
    END
  END r0_rd_out[55]
  PIN r0_rd_out[56]
    DIRECTION OUTPUT ;
    USE SIGNAL ;
    SHAPE ABUTMENT ;
    PORT
      LAYER M3_m ;
      RECT 0 442.435 0.07 442.505 ;
    END
  END r0_rd_out[56]
  PIN r0_rd_out[57]
    DIRECTION OUTPUT ;
    USE SIGNAL ;
    SHAPE ABUTMENT ;
    PORT
      LAYER M3_m ;
      RECT 0 443.135 0.07 443.205 ;
    END
  END r0_rd_out[57]
  PIN r0_rd_out[58]
    DIRECTION OUTPUT ;
    USE SIGNAL ;
    SHAPE ABUTMENT ;
    PORT
      LAYER M3_m ;
      RECT 0 443.835 0.07 443.905 ;
    END
  END r0_rd_out[58]
  PIN r0_rd_out[59]
    DIRECTION OUTPUT ;
    USE SIGNAL ;
    SHAPE ABUTMENT ;
    PORT
      LAYER M3_m ;
      RECT 0 444.535 0.07 444.605 ;
    END
  END r0_rd_out[59]
  PIN r0_rd_out[60]
    DIRECTION OUTPUT ;
    USE SIGNAL ;
    SHAPE ABUTMENT ;
    PORT
      LAYER M3_m ;
      RECT 0 445.235 0.07 445.305 ;
    END
  END r0_rd_out[60]
  PIN r0_rd_out[61]
    DIRECTION OUTPUT ;
    USE SIGNAL ;
    SHAPE ABUTMENT ;
    PORT
      LAYER M3_m ;
      RECT 0 445.935 0.07 446.005 ;
    END
  END r0_rd_out[61]
  PIN r0_rd_out[62]
    DIRECTION OUTPUT ;
    USE SIGNAL ;
    SHAPE ABUTMENT ;
    PORT
      LAYER M3_m ;
      RECT 0 446.635 0.07 446.705 ;
    END
  END r0_rd_out[62]
  PIN r0_rd_out[63]
    DIRECTION OUTPUT ;
    USE SIGNAL ;
    SHAPE ABUTMENT ;
    PORT
      LAYER M3_m ;
      RECT 0 447.335 0.07 447.405 ;
    END
  END r0_rd_out[63]
  PIN r0_rd_out[64]
    DIRECTION OUTPUT ;
    USE SIGNAL ;
    SHAPE ABUTMENT ;
    PORT
      LAYER M3_m ;
      RECT 0 448.035 0.07 448.105 ;
    END
  END r0_rd_out[64]
  PIN r0_rd_out[65]
    DIRECTION OUTPUT ;
    USE SIGNAL ;
    SHAPE ABUTMENT ;
    PORT
      LAYER M3_m ;
      RECT 0 448.735 0.07 448.805 ;
    END
  END r0_rd_out[65]
  PIN r0_rd_out[66]
    DIRECTION OUTPUT ;
    USE SIGNAL ;
    SHAPE ABUTMENT ;
    PORT
      LAYER M3_m ;
      RECT 0 449.435 0.07 449.505 ;
    END
  END r0_rd_out[66]
  PIN r0_rd_out[67]
    DIRECTION OUTPUT ;
    USE SIGNAL ;
    SHAPE ABUTMENT ;
    PORT
      LAYER M3_m ;
      RECT 0 450.135 0.07 450.205 ;
    END
  END r0_rd_out[67]
  PIN r0_rd_out[68]
    DIRECTION OUTPUT ;
    USE SIGNAL ;
    SHAPE ABUTMENT ;
    PORT
      LAYER M3_m ;
      RECT 0 450.835 0.07 450.905 ;
    END
  END r0_rd_out[68]
  PIN r0_rd_out[69]
    DIRECTION OUTPUT ;
    USE SIGNAL ;
    SHAPE ABUTMENT ;
    PORT
      LAYER M3_m ;
      RECT 0 451.535 0.07 451.605 ;
    END
  END r0_rd_out[69]
  PIN r0_rd_out[70]
    DIRECTION OUTPUT ;
    USE SIGNAL ;
    SHAPE ABUTMENT ;
    PORT
      LAYER M3_m ;
      RECT 0 452.235 0.07 452.305 ;
    END
  END r0_rd_out[70]
  PIN r0_rd_out[71]
    DIRECTION OUTPUT ;
    USE SIGNAL ;
    SHAPE ABUTMENT ;
    PORT
      LAYER M3_m ;
      RECT 0 452.935 0.07 453.005 ;
    END
  END r0_rd_out[71]
  PIN r0_rd_out[72]
    DIRECTION OUTPUT ;
    USE SIGNAL ;
    SHAPE ABUTMENT ;
    PORT
      LAYER M3_m ;
      RECT 0 453.635 0.07 453.705 ;
    END
  END r0_rd_out[72]
  PIN r0_rd_out[73]
    DIRECTION OUTPUT ;
    USE SIGNAL ;
    SHAPE ABUTMENT ;
    PORT
      LAYER M3_m ;
      RECT 0 454.335 0.07 454.405 ;
    END
  END r0_rd_out[73]
  PIN r0_rd_out[74]
    DIRECTION OUTPUT ;
    USE SIGNAL ;
    SHAPE ABUTMENT ;
    PORT
      LAYER M3_m ;
      RECT 0 455.035 0.07 455.105 ;
    END
  END r0_rd_out[74]
  PIN r0_rd_out[75]
    DIRECTION OUTPUT ;
    USE SIGNAL ;
    SHAPE ABUTMENT ;
    PORT
      LAYER M3_m ;
      RECT 0 455.735 0.07 455.805 ;
    END
  END r0_rd_out[75]
  PIN r0_rd_out[76]
    DIRECTION OUTPUT ;
    USE SIGNAL ;
    SHAPE ABUTMENT ;
    PORT
      LAYER M3_m ;
      RECT 0 456.435 0.07 456.505 ;
    END
  END r0_rd_out[76]
  PIN r0_rd_out[77]
    DIRECTION OUTPUT ;
    USE SIGNAL ;
    SHAPE ABUTMENT ;
    PORT
      LAYER M3_m ;
      RECT 0 457.135 0.07 457.205 ;
    END
  END r0_rd_out[77]
  PIN r0_rd_out[78]
    DIRECTION OUTPUT ;
    USE SIGNAL ;
    SHAPE ABUTMENT ;
    PORT
      LAYER M3_m ;
      RECT 0 457.835 0.07 457.905 ;
    END
  END r0_rd_out[78]
  PIN r0_rd_out[79]
    DIRECTION OUTPUT ;
    USE SIGNAL ;
    SHAPE ABUTMENT ;
    PORT
      LAYER M3_m ;
      RECT 0 458.535 0.07 458.605 ;
    END
  END r0_rd_out[79]
  PIN r0_rd_out[80]
    DIRECTION OUTPUT ;
    USE SIGNAL ;
    SHAPE ABUTMENT ;
    PORT
      LAYER M3_m ;
      RECT 0 459.235 0.07 459.305 ;
    END
  END r0_rd_out[80]
  PIN r0_rd_out[81]
    DIRECTION OUTPUT ;
    USE SIGNAL ;
    SHAPE ABUTMENT ;
    PORT
      LAYER M3_m ;
      RECT 0 459.935 0.07 460.005 ;
    END
  END r0_rd_out[81]
  PIN r0_rd_out[82]
    DIRECTION OUTPUT ;
    USE SIGNAL ;
    SHAPE ABUTMENT ;
    PORT
      LAYER M3_m ;
      RECT 0 460.635 0.07 460.705 ;
    END
  END r0_rd_out[82]
  PIN r0_rd_out[83]
    DIRECTION OUTPUT ;
    USE SIGNAL ;
    SHAPE ABUTMENT ;
    PORT
      LAYER M3_m ;
      RECT 0 461.335 0.07 461.405 ;
    END
  END r0_rd_out[83]
  PIN r0_rd_out[84]
    DIRECTION OUTPUT ;
    USE SIGNAL ;
    SHAPE ABUTMENT ;
    PORT
      LAYER M3_m ;
      RECT 0 462.035 0.07 462.105 ;
    END
  END r0_rd_out[84]
  PIN r0_rd_out[85]
    DIRECTION OUTPUT ;
    USE SIGNAL ;
    SHAPE ABUTMENT ;
    PORT
      LAYER M3_m ;
      RECT 0 462.735 0.07 462.805 ;
    END
  END r0_rd_out[85]
  PIN r0_rd_out[86]
    DIRECTION OUTPUT ;
    USE SIGNAL ;
    SHAPE ABUTMENT ;
    PORT
      LAYER M3_m ;
      RECT 0 463.435 0.07 463.505 ;
    END
  END r0_rd_out[86]
  PIN r0_rd_out[87]
    DIRECTION OUTPUT ;
    USE SIGNAL ;
    SHAPE ABUTMENT ;
    PORT
      LAYER M3_m ;
      RECT 0 464.135 0.07 464.205 ;
    END
  END r0_rd_out[87]
  PIN r0_rd_out[88]
    DIRECTION OUTPUT ;
    USE SIGNAL ;
    SHAPE ABUTMENT ;
    PORT
      LAYER M3_m ;
      RECT 0 464.835 0.07 464.905 ;
    END
  END r0_rd_out[88]
  PIN r0_rd_out[89]
    DIRECTION OUTPUT ;
    USE SIGNAL ;
    SHAPE ABUTMENT ;
    PORT
      LAYER M3_m ;
      RECT 0 465.535 0.07 465.605 ;
    END
  END r0_rd_out[89]
  PIN r0_rd_out[90]
    DIRECTION OUTPUT ;
    USE SIGNAL ;
    SHAPE ABUTMENT ;
    PORT
      LAYER M3_m ;
      RECT 0 466.235 0.07 466.305 ;
    END
  END r0_rd_out[90]
  PIN r0_rd_out[91]
    DIRECTION OUTPUT ;
    USE SIGNAL ;
    SHAPE ABUTMENT ;
    PORT
      LAYER M3_m ;
      RECT 0 466.935 0.07 467.005 ;
    END
  END r0_rd_out[91]
  PIN r0_rd_out[92]
    DIRECTION OUTPUT ;
    USE SIGNAL ;
    SHAPE ABUTMENT ;
    PORT
      LAYER M3_m ;
      RECT 0 467.635 0.07 467.705 ;
    END
  END r0_rd_out[92]
  PIN r0_rd_out[93]
    DIRECTION OUTPUT ;
    USE SIGNAL ;
    SHAPE ABUTMENT ;
    PORT
      LAYER M3_m ;
      RECT 0 468.335 0.07 468.405 ;
    END
  END r0_rd_out[93]
  PIN r0_rd_out[94]
    DIRECTION OUTPUT ;
    USE SIGNAL ;
    SHAPE ABUTMENT ;
    PORT
      LAYER M3_m ;
      RECT 0 469.035 0.07 469.105 ;
    END
  END r0_rd_out[94]
  PIN r0_rd_out[95]
    DIRECTION OUTPUT ;
    USE SIGNAL ;
    SHAPE ABUTMENT ;
    PORT
      LAYER M3_m ;
      RECT 0 469.735 0.07 469.805 ;
    END
  END r0_rd_out[95]
  PIN r0_rd_out[96]
    DIRECTION OUTPUT ;
    USE SIGNAL ;
    SHAPE ABUTMENT ;
    PORT
      LAYER M3_m ;
      RECT 0 470.435 0.07 470.505 ;
    END
  END r0_rd_out[96]
  PIN r0_rd_out[97]
    DIRECTION OUTPUT ;
    USE SIGNAL ;
    SHAPE ABUTMENT ;
    PORT
      LAYER M3_m ;
      RECT 0 471.135 0.07 471.205 ;
    END
  END r0_rd_out[97]
  PIN r0_rd_out[98]
    DIRECTION OUTPUT ;
    USE SIGNAL ;
    SHAPE ABUTMENT ;
    PORT
      LAYER M3_m ;
      RECT 0 471.835 0.07 471.905 ;
    END
  END r0_rd_out[98]
  PIN r0_rd_out[99]
    DIRECTION OUTPUT ;
    USE SIGNAL ;
    SHAPE ABUTMENT ;
    PORT
      LAYER M3_m ;
      RECT 0 472.535 0.07 472.605 ;
    END
  END r0_rd_out[99]
  PIN r0_rd_out[100]
    DIRECTION OUTPUT ;
    USE SIGNAL ;
    SHAPE ABUTMENT ;
    PORT
      LAYER M3_m ;
      RECT 0 473.235 0.07 473.305 ;
    END
  END r0_rd_out[100]
  PIN r0_rd_out[101]
    DIRECTION OUTPUT ;
    USE SIGNAL ;
    SHAPE ABUTMENT ;
    PORT
      LAYER M3_m ;
      RECT 0 473.935 0.07 474.005 ;
    END
  END r0_rd_out[101]
  PIN r0_rd_out[102]
    DIRECTION OUTPUT ;
    USE SIGNAL ;
    SHAPE ABUTMENT ;
    PORT
      LAYER M3_m ;
      RECT 0 474.635 0.07 474.705 ;
    END
  END r0_rd_out[102]
  PIN r0_rd_out[103]
    DIRECTION OUTPUT ;
    USE SIGNAL ;
    SHAPE ABUTMENT ;
    PORT
      LAYER M3_m ;
      RECT 0 475.335 0.07 475.405 ;
    END
  END r0_rd_out[103]
  PIN r0_rd_out[104]
    DIRECTION OUTPUT ;
    USE SIGNAL ;
    SHAPE ABUTMENT ;
    PORT
      LAYER M3_m ;
      RECT 0 476.035 0.07 476.105 ;
    END
  END r0_rd_out[104]
  PIN r0_rd_out[105]
    DIRECTION OUTPUT ;
    USE SIGNAL ;
    SHAPE ABUTMENT ;
    PORT
      LAYER M3_m ;
      RECT 0 476.735 0.07 476.805 ;
    END
  END r0_rd_out[105]
  PIN r0_rd_out[106]
    DIRECTION OUTPUT ;
    USE SIGNAL ;
    SHAPE ABUTMENT ;
    PORT
      LAYER M3_m ;
      RECT 0 477.435 0.07 477.505 ;
    END
  END r0_rd_out[106]
  PIN r0_rd_out[107]
    DIRECTION OUTPUT ;
    USE SIGNAL ;
    SHAPE ABUTMENT ;
    PORT
      LAYER M3_m ;
      RECT 0 478.135 0.07 478.205 ;
    END
  END r0_rd_out[107]
  PIN r0_rd_out[108]
    DIRECTION OUTPUT ;
    USE SIGNAL ;
    SHAPE ABUTMENT ;
    PORT
      LAYER M3_m ;
      RECT 0 478.835 0.07 478.905 ;
    END
  END r0_rd_out[108]
  PIN r0_rd_out[109]
    DIRECTION OUTPUT ;
    USE SIGNAL ;
    SHAPE ABUTMENT ;
    PORT
      LAYER M3_m ;
      RECT 0 479.535 0.07 479.605 ;
    END
  END r0_rd_out[109]
  PIN r0_rd_out[110]
    DIRECTION OUTPUT ;
    USE SIGNAL ;
    SHAPE ABUTMENT ;
    PORT
      LAYER M3_m ;
      RECT 0 480.235 0.07 480.305 ;
    END
  END r0_rd_out[110]
  PIN r0_rd_out[111]
    DIRECTION OUTPUT ;
    USE SIGNAL ;
    SHAPE ABUTMENT ;
    PORT
      LAYER M3_m ;
      RECT 0 480.935 0.07 481.005 ;
    END
  END r0_rd_out[111]
  PIN r0_rd_out[112]
    DIRECTION OUTPUT ;
    USE SIGNAL ;
    SHAPE ABUTMENT ;
    PORT
      LAYER M3_m ;
      RECT 0 481.635 0.07 481.705 ;
    END
  END r0_rd_out[112]
  PIN r0_rd_out[113]
    DIRECTION OUTPUT ;
    USE SIGNAL ;
    SHAPE ABUTMENT ;
    PORT
      LAYER M3_m ;
      RECT 0 482.335 0.07 482.405 ;
    END
  END r0_rd_out[113]
  PIN r0_rd_out[114]
    DIRECTION OUTPUT ;
    USE SIGNAL ;
    SHAPE ABUTMENT ;
    PORT
      LAYER M3_m ;
      RECT 0 483.035 0.07 483.105 ;
    END
  END r0_rd_out[114]
  PIN r0_rd_out[115]
    DIRECTION OUTPUT ;
    USE SIGNAL ;
    SHAPE ABUTMENT ;
    PORT
      LAYER M3_m ;
      RECT 0 483.735 0.07 483.805 ;
    END
  END r0_rd_out[115]
  PIN r0_rd_out[116]
    DIRECTION OUTPUT ;
    USE SIGNAL ;
    SHAPE ABUTMENT ;
    PORT
      LAYER M3_m ;
      RECT 0 484.435 0.07 484.505 ;
    END
  END r0_rd_out[116]
  PIN r0_rd_out[117]
    DIRECTION OUTPUT ;
    USE SIGNAL ;
    SHAPE ABUTMENT ;
    PORT
      LAYER M3_m ;
      RECT 0 485.135 0.07 485.205 ;
    END
  END r0_rd_out[117]
  PIN r0_rd_out[118]
    DIRECTION OUTPUT ;
    USE SIGNAL ;
    SHAPE ABUTMENT ;
    PORT
      LAYER M3_m ;
      RECT 0 485.835 0.07 485.905 ;
    END
  END r0_rd_out[118]
  PIN r0_rd_out[119]
    DIRECTION OUTPUT ;
    USE SIGNAL ;
    SHAPE ABUTMENT ;
    PORT
      LAYER M3_m ;
      RECT 0 486.535 0.07 486.605 ;
    END
  END r0_rd_out[119]
  PIN r0_rd_out[120]
    DIRECTION OUTPUT ;
    USE SIGNAL ;
    SHAPE ABUTMENT ;
    PORT
      LAYER M3_m ;
      RECT 0 487.235 0.07 487.305 ;
    END
  END r0_rd_out[120]
  PIN r0_rd_out[121]
    DIRECTION OUTPUT ;
    USE SIGNAL ;
    SHAPE ABUTMENT ;
    PORT
      LAYER M3_m ;
      RECT 0 487.935 0.07 488.005 ;
    END
  END r0_rd_out[121]
  PIN r0_rd_out[122]
    DIRECTION OUTPUT ;
    USE SIGNAL ;
    SHAPE ABUTMENT ;
    PORT
      LAYER M3_m ;
      RECT 0 488.635 0.07 488.705 ;
    END
  END r0_rd_out[122]
  PIN r0_rd_out[123]
    DIRECTION OUTPUT ;
    USE SIGNAL ;
    SHAPE ABUTMENT ;
    PORT
      LAYER M3_m ;
      RECT 0 489.335 0.07 489.405 ;
    END
  END r0_rd_out[123]
  PIN r0_rd_out[124]
    DIRECTION OUTPUT ;
    USE SIGNAL ;
    SHAPE ABUTMENT ;
    PORT
      LAYER M3_m ;
      RECT 0 490.035 0.07 490.105 ;
    END
  END r0_rd_out[124]
  PIN r0_rd_out[125]
    DIRECTION OUTPUT ;
    USE SIGNAL ;
    SHAPE ABUTMENT ;
    PORT
      LAYER M3_m ;
      RECT 0 490.735 0.07 490.805 ;
    END
  END r0_rd_out[125]
  PIN r0_rd_out[126]
    DIRECTION OUTPUT ;
    USE SIGNAL ;
    SHAPE ABUTMENT ;
    PORT
      LAYER M3_m ;
      RECT 0 491.435 0.07 491.505 ;
    END
  END r0_rd_out[126]
  PIN r0_rd_out[127]
    DIRECTION OUTPUT ;
    USE SIGNAL ;
    SHAPE ABUTMENT ;
    PORT
      LAYER M3_m ;
      RECT 0 492.135 0.07 492.205 ;
    END
  END r0_rd_out[127]
  PIN r0_rd_out[128]
    DIRECTION OUTPUT ;
    USE SIGNAL ;
    SHAPE ABUTMENT ;
    PORT
      LAYER M3_m ;
      RECT 0 492.835 0.07 492.905 ;
    END
  END r0_rd_out[128]
  PIN r0_rd_out[129]
    DIRECTION OUTPUT ;
    USE SIGNAL ;
    SHAPE ABUTMENT ;
    PORT
      LAYER M3_m ;
      RECT 0 493.535 0.07 493.605 ;
    END
  END r0_rd_out[129]
  PIN r0_rd_out[130]
    DIRECTION OUTPUT ;
    USE SIGNAL ;
    SHAPE ABUTMENT ;
    PORT
      LAYER M3_m ;
      RECT 0 494.235 0.07 494.305 ;
    END
  END r0_rd_out[130]
  PIN r0_rd_out[131]
    DIRECTION OUTPUT ;
    USE SIGNAL ;
    SHAPE ABUTMENT ;
    PORT
      LAYER M3_m ;
      RECT 0 494.935 0.07 495.005 ;
    END
  END r0_rd_out[131]
  PIN r0_rd_out[132]
    DIRECTION OUTPUT ;
    USE SIGNAL ;
    SHAPE ABUTMENT ;
    PORT
      LAYER M3_m ;
      RECT 0 495.635 0.07 495.705 ;
    END
  END r0_rd_out[132]
  PIN r0_rd_out[133]
    DIRECTION OUTPUT ;
    USE SIGNAL ;
    SHAPE ABUTMENT ;
    PORT
      LAYER M3_m ;
      RECT 0 496.335 0.07 496.405 ;
    END
  END r0_rd_out[133]
  PIN r0_rd_out[134]
    DIRECTION OUTPUT ;
    USE SIGNAL ;
    SHAPE ABUTMENT ;
    PORT
      LAYER M3_m ;
      RECT 0 497.035 0.07 497.105 ;
    END
  END r0_rd_out[134]
  PIN r0_rd_out[135]
    DIRECTION OUTPUT ;
    USE SIGNAL ;
    SHAPE ABUTMENT ;
    PORT
      LAYER M3_m ;
      RECT 0 497.735 0.07 497.805 ;
    END
  END r0_rd_out[135]
  PIN r0_rd_out[136]
    DIRECTION OUTPUT ;
    USE SIGNAL ;
    SHAPE ABUTMENT ;
    PORT
      LAYER M3_m ;
      RECT 0 498.435 0.07 498.505 ;
    END
  END r0_rd_out[136]
  PIN r0_rd_out[137]
    DIRECTION OUTPUT ;
    USE SIGNAL ;
    SHAPE ABUTMENT ;
    PORT
      LAYER M3_m ;
      RECT 0 499.135 0.07 499.205 ;
    END
  END r0_rd_out[137]
  PIN r0_rd_out[138]
    DIRECTION OUTPUT ;
    USE SIGNAL ;
    SHAPE ABUTMENT ;
    PORT
      LAYER M3_m ;
      RECT 0 499.835 0.07 499.905 ;
    END
  END r0_rd_out[138]
  PIN r0_rd_out[139]
    DIRECTION OUTPUT ;
    USE SIGNAL ;
    SHAPE ABUTMENT ;
    PORT
      LAYER M3_m ;
      RECT 0 500.535 0.07 500.605 ;
    END
  END r0_rd_out[139]
  PIN r0_rd_out[140]
    DIRECTION OUTPUT ;
    USE SIGNAL ;
    SHAPE ABUTMENT ;
    PORT
      LAYER M3_m ;
      RECT 0 501.235 0.07 501.305 ;
    END
  END r0_rd_out[140]
  PIN r0_rd_out[141]
    DIRECTION OUTPUT ;
    USE SIGNAL ;
    SHAPE ABUTMENT ;
    PORT
      LAYER M3_m ;
      RECT 0 501.935 0.07 502.005 ;
    END
  END r0_rd_out[141]
  PIN r0_rd_out[142]
    DIRECTION OUTPUT ;
    USE SIGNAL ;
    SHAPE ABUTMENT ;
    PORT
      LAYER M3_m ;
      RECT 0 502.635 0.07 502.705 ;
    END
  END r0_rd_out[142]
  PIN r0_rd_out[143]
    DIRECTION OUTPUT ;
    USE SIGNAL ;
    SHAPE ABUTMENT ;
    PORT
      LAYER M3_m ;
      RECT 0 503.335 0.07 503.405 ;
    END
  END r0_rd_out[143]
  PIN r0_rd_out[144]
    DIRECTION OUTPUT ;
    USE SIGNAL ;
    SHAPE ABUTMENT ;
    PORT
      LAYER M3_m ;
      RECT 0 504.035 0.07 504.105 ;
    END
  END r0_rd_out[144]
  PIN r0_rd_out[145]
    DIRECTION OUTPUT ;
    USE SIGNAL ;
    SHAPE ABUTMENT ;
    PORT
      LAYER M3_m ;
      RECT 0 504.735 0.07 504.805 ;
    END
  END r0_rd_out[145]
  PIN r0_rd_out[146]
    DIRECTION OUTPUT ;
    USE SIGNAL ;
    SHAPE ABUTMENT ;
    PORT
      LAYER M3_m ;
      RECT 0 505.435 0.07 505.505 ;
    END
  END r0_rd_out[146]
  PIN r0_rd_out[147]
    DIRECTION OUTPUT ;
    USE SIGNAL ;
    SHAPE ABUTMENT ;
    PORT
      LAYER M3_m ;
      RECT 0 506.135 0.07 506.205 ;
    END
  END r0_rd_out[147]
  PIN r0_rd_out[148]
    DIRECTION OUTPUT ;
    USE SIGNAL ;
    SHAPE ABUTMENT ;
    PORT
      LAYER M3_m ;
      RECT 0 506.835 0.07 506.905 ;
    END
  END r0_rd_out[148]
  PIN r0_rd_out[149]
    DIRECTION OUTPUT ;
    USE SIGNAL ;
    SHAPE ABUTMENT ;
    PORT
      LAYER M3_m ;
      RECT 0 507.535 0.07 507.605 ;
    END
  END r0_rd_out[149]
  PIN r0_rd_out[150]
    DIRECTION OUTPUT ;
    USE SIGNAL ;
    SHAPE ABUTMENT ;
    PORT
      LAYER M3_m ;
      RECT 0 508.235 0.07 508.305 ;
    END
  END r0_rd_out[150]
  PIN r0_rd_out[151]
    DIRECTION OUTPUT ;
    USE SIGNAL ;
    SHAPE ABUTMENT ;
    PORT
      LAYER M3_m ;
      RECT 0 508.935 0.07 509.005 ;
    END
  END r0_rd_out[151]
  PIN r0_rd_out[152]
    DIRECTION OUTPUT ;
    USE SIGNAL ;
    SHAPE ABUTMENT ;
    PORT
      LAYER M3_m ;
      RECT 0 509.635 0.07 509.705 ;
    END
  END r0_rd_out[152]
  PIN r0_rd_out[153]
    DIRECTION OUTPUT ;
    USE SIGNAL ;
    SHAPE ABUTMENT ;
    PORT
      LAYER M3_m ;
      RECT 0 510.335 0.07 510.405 ;
    END
  END r0_rd_out[153]
  PIN r0_rd_out[154]
    DIRECTION OUTPUT ;
    USE SIGNAL ;
    SHAPE ABUTMENT ;
    PORT
      LAYER M3_m ;
      RECT 0 511.035 0.07 511.105 ;
    END
  END r0_rd_out[154]
  PIN r0_rd_out[155]
    DIRECTION OUTPUT ;
    USE SIGNAL ;
    SHAPE ABUTMENT ;
    PORT
      LAYER M3_m ;
      RECT 0 511.735 0.07 511.805 ;
    END
  END r0_rd_out[155]
  PIN r0_rd_out[156]
    DIRECTION OUTPUT ;
    USE SIGNAL ;
    SHAPE ABUTMENT ;
    PORT
      LAYER M3_m ;
      RECT 0 512.435 0.07 512.505 ;
    END
  END r0_rd_out[156]
  PIN r0_rd_out[157]
    DIRECTION OUTPUT ;
    USE SIGNAL ;
    SHAPE ABUTMENT ;
    PORT
      LAYER M3_m ;
      RECT 0 513.135 0.07 513.205 ;
    END
  END r0_rd_out[157]
  PIN r0_rd_out[158]
    DIRECTION OUTPUT ;
    USE SIGNAL ;
    SHAPE ABUTMENT ;
    PORT
      LAYER M3_m ;
      RECT 0 513.835 0.07 513.905 ;
    END
  END r0_rd_out[158]
  PIN r0_rd_out[159]
    DIRECTION OUTPUT ;
    USE SIGNAL ;
    SHAPE ABUTMENT ;
    PORT
      LAYER M3_m ;
      RECT 0 514.535 0.07 514.605 ;
    END
  END r0_rd_out[159]
  PIN r0_rd_out[160]
    DIRECTION OUTPUT ;
    USE SIGNAL ;
    SHAPE ABUTMENT ;
    PORT
      LAYER M3_m ;
      RECT 0 515.235 0.07 515.305 ;
    END
  END r0_rd_out[160]
  PIN r0_rd_out[161]
    DIRECTION OUTPUT ;
    USE SIGNAL ;
    SHAPE ABUTMENT ;
    PORT
      LAYER M3_m ;
      RECT 0 515.935 0.07 516.005 ;
    END
  END r0_rd_out[161]
  PIN r0_rd_out[162]
    DIRECTION OUTPUT ;
    USE SIGNAL ;
    SHAPE ABUTMENT ;
    PORT
      LAYER M3_m ;
      RECT 0 516.635 0.07 516.705 ;
    END
  END r0_rd_out[162]
  PIN r0_rd_out[163]
    DIRECTION OUTPUT ;
    USE SIGNAL ;
    SHAPE ABUTMENT ;
    PORT
      LAYER M3_m ;
      RECT 0 517.335 0.07 517.405 ;
    END
  END r0_rd_out[163]
  PIN r0_rd_out[164]
    DIRECTION OUTPUT ;
    USE SIGNAL ;
    SHAPE ABUTMENT ;
    PORT
      LAYER M3_m ;
      RECT 0 518.035 0.07 518.105 ;
    END
  END r0_rd_out[164]
  PIN r0_rd_out[165]
    DIRECTION OUTPUT ;
    USE SIGNAL ;
    SHAPE ABUTMENT ;
    PORT
      LAYER M3_m ;
      RECT 0 518.735 0.07 518.805 ;
    END
  END r0_rd_out[165]
  PIN r0_rd_out[166]
    DIRECTION OUTPUT ;
    USE SIGNAL ;
    SHAPE ABUTMENT ;
    PORT
      LAYER M3_m ;
      RECT 0 519.435 0.07 519.505 ;
    END
  END r0_rd_out[166]
  PIN r0_rd_out[167]
    DIRECTION OUTPUT ;
    USE SIGNAL ;
    SHAPE ABUTMENT ;
    PORT
      LAYER M3_m ;
      RECT 0 520.135 0.07 520.205 ;
    END
  END r0_rd_out[167]
  PIN r0_rd_out[168]
    DIRECTION OUTPUT ;
    USE SIGNAL ;
    SHAPE ABUTMENT ;
    PORT
      LAYER M3_m ;
      RECT 0 520.835 0.07 520.905 ;
    END
  END r0_rd_out[168]
  PIN r0_rd_out[169]
    DIRECTION OUTPUT ;
    USE SIGNAL ;
    SHAPE ABUTMENT ;
    PORT
      LAYER M3_m ;
      RECT 0 521.535 0.07 521.605 ;
    END
  END r0_rd_out[169]
  PIN r0_rd_out[170]
    DIRECTION OUTPUT ;
    USE SIGNAL ;
    SHAPE ABUTMENT ;
    PORT
      LAYER M3_m ;
      RECT 0 522.235 0.07 522.305 ;
    END
  END r0_rd_out[170]
  PIN r0_rd_out[171]
    DIRECTION OUTPUT ;
    USE SIGNAL ;
    SHAPE ABUTMENT ;
    PORT
      LAYER M3_m ;
      RECT 0 522.935 0.07 523.005 ;
    END
  END r0_rd_out[171]
  PIN r0_rd_out[172]
    DIRECTION OUTPUT ;
    USE SIGNAL ;
    SHAPE ABUTMENT ;
    PORT
      LAYER M3_m ;
      RECT 0 523.635 0.07 523.705 ;
    END
  END r0_rd_out[172]
  PIN r0_rd_out[173]
    DIRECTION OUTPUT ;
    USE SIGNAL ;
    SHAPE ABUTMENT ;
    PORT
      LAYER M3_m ;
      RECT 0 524.335 0.07 524.405 ;
    END
  END r0_rd_out[173]
  PIN r0_rd_out[174]
    DIRECTION OUTPUT ;
    USE SIGNAL ;
    SHAPE ABUTMENT ;
    PORT
      LAYER M3_m ;
      RECT 0 525.035 0.07 525.105 ;
    END
  END r0_rd_out[174]
  PIN r0_rd_out[175]
    DIRECTION OUTPUT ;
    USE SIGNAL ;
    SHAPE ABUTMENT ;
    PORT
      LAYER M3_m ;
      RECT 0 525.735 0.07 525.805 ;
    END
  END r0_rd_out[175]
  PIN r0_rd_out[176]
    DIRECTION OUTPUT ;
    USE SIGNAL ;
    SHAPE ABUTMENT ;
    PORT
      LAYER M3_m ;
      RECT 0 526.435 0.07 526.505 ;
    END
  END r0_rd_out[176]
  PIN r0_rd_out[177]
    DIRECTION OUTPUT ;
    USE SIGNAL ;
    SHAPE ABUTMENT ;
    PORT
      LAYER M3_m ;
      RECT 0 527.135 0.07 527.205 ;
    END
  END r0_rd_out[177]
  PIN r0_rd_out[178]
    DIRECTION OUTPUT ;
    USE SIGNAL ;
    SHAPE ABUTMENT ;
    PORT
      LAYER M3_m ;
      RECT 0 527.835 0.07 527.905 ;
    END
  END r0_rd_out[178]
  PIN r0_rd_out[179]
    DIRECTION OUTPUT ;
    USE SIGNAL ;
    SHAPE ABUTMENT ;
    PORT
      LAYER M3_m ;
      RECT 0 528.535 0.07 528.605 ;
    END
  END r0_rd_out[179]
  PIN r0_rd_out[180]
    DIRECTION OUTPUT ;
    USE SIGNAL ;
    SHAPE ABUTMENT ;
    PORT
      LAYER M3_m ;
      RECT 0 529.235 0.07 529.305 ;
    END
  END r0_rd_out[180]
  PIN r0_rd_out[181]
    DIRECTION OUTPUT ;
    USE SIGNAL ;
    SHAPE ABUTMENT ;
    PORT
      LAYER M3_m ;
      RECT 0 529.935 0.07 530.005 ;
    END
  END r0_rd_out[181]
  PIN r0_rd_out[182]
    DIRECTION OUTPUT ;
    USE SIGNAL ;
    SHAPE ABUTMENT ;
    PORT
      LAYER M3_m ;
      RECT 0 530.635 0.07 530.705 ;
    END
  END r0_rd_out[182]
  PIN r0_rd_out[183]
    DIRECTION OUTPUT ;
    USE SIGNAL ;
    SHAPE ABUTMENT ;
    PORT
      LAYER M3_m ;
      RECT 0 531.335 0.07 531.405 ;
    END
  END r0_rd_out[183]
  PIN r0_rd_out[184]
    DIRECTION OUTPUT ;
    USE SIGNAL ;
    SHAPE ABUTMENT ;
    PORT
      LAYER M3_m ;
      RECT 0 532.035 0.07 532.105 ;
    END
  END r0_rd_out[184]
  PIN r0_rd_out[185]
    DIRECTION OUTPUT ;
    USE SIGNAL ;
    SHAPE ABUTMENT ;
    PORT
      LAYER M3_m ;
      RECT 0 532.735 0.07 532.805 ;
    END
  END r0_rd_out[185]
  PIN r0_rd_out[186]
    DIRECTION OUTPUT ;
    USE SIGNAL ;
    SHAPE ABUTMENT ;
    PORT
      LAYER M3_m ;
      RECT 0 533.435 0.07 533.505 ;
    END
  END r0_rd_out[186]
  PIN r0_rd_out[187]
    DIRECTION OUTPUT ;
    USE SIGNAL ;
    SHAPE ABUTMENT ;
    PORT
      LAYER M3_m ;
      RECT 0 534.135 0.07 534.205 ;
    END
  END r0_rd_out[187]
  PIN r0_rd_out[188]
    DIRECTION OUTPUT ;
    USE SIGNAL ;
    SHAPE ABUTMENT ;
    PORT
      LAYER M3_m ;
      RECT 0 534.835 0.07 534.905 ;
    END
  END r0_rd_out[188]
  PIN r0_rd_out[189]
    DIRECTION OUTPUT ;
    USE SIGNAL ;
    SHAPE ABUTMENT ;
    PORT
      LAYER M3_m ;
      RECT 0 535.535 0.07 535.605 ;
    END
  END r0_rd_out[189]
  PIN r0_rd_out[190]
    DIRECTION OUTPUT ;
    USE SIGNAL ;
    SHAPE ABUTMENT ;
    PORT
      LAYER M3_m ;
      RECT 0 536.235 0.07 536.305 ;
    END
  END r0_rd_out[190]
  PIN r0_rd_out[191]
    DIRECTION OUTPUT ;
    USE SIGNAL ;
    SHAPE ABUTMENT ;
    PORT
      LAYER M3_m ;
      RECT 0 536.935 0.07 537.005 ;
    END
  END r0_rd_out[191]
  PIN r0_rd_out[192]
    DIRECTION OUTPUT ;
    USE SIGNAL ;
    SHAPE ABUTMENT ;
    PORT
      LAYER M3_m ;
      RECT 0 537.635 0.07 537.705 ;
    END
  END r0_rd_out[192]
  PIN r0_rd_out[193]
    DIRECTION OUTPUT ;
    USE SIGNAL ;
    SHAPE ABUTMENT ;
    PORT
      LAYER M3_m ;
      RECT 0 538.335 0.07 538.405 ;
    END
  END r0_rd_out[193]
  PIN r0_rd_out[194]
    DIRECTION OUTPUT ;
    USE SIGNAL ;
    SHAPE ABUTMENT ;
    PORT
      LAYER M3_m ;
      RECT 0 539.035 0.07 539.105 ;
    END
  END r0_rd_out[194]
  PIN r0_rd_out[195]
    DIRECTION OUTPUT ;
    USE SIGNAL ;
    SHAPE ABUTMENT ;
    PORT
      LAYER M3_m ;
      RECT 0 539.735 0.07 539.805 ;
    END
  END r0_rd_out[195]
  PIN r0_rd_out[196]
    DIRECTION OUTPUT ;
    USE SIGNAL ;
    SHAPE ABUTMENT ;
    PORT
      LAYER M3_m ;
      RECT 0 540.435 0.07 540.505 ;
    END
  END r0_rd_out[196]
  PIN r0_rd_out[197]
    DIRECTION OUTPUT ;
    USE SIGNAL ;
    SHAPE ABUTMENT ;
    PORT
      LAYER M3_m ;
      RECT 0 541.135 0.07 541.205 ;
    END
  END r0_rd_out[197]
  PIN r0_rd_out[198]
    DIRECTION OUTPUT ;
    USE SIGNAL ;
    SHAPE ABUTMENT ;
    PORT
      LAYER M3_m ;
      RECT 0 541.835 0.07 541.905 ;
    END
  END r0_rd_out[198]
  PIN r0_rd_out[199]
    DIRECTION OUTPUT ;
    USE SIGNAL ;
    SHAPE ABUTMENT ;
    PORT
      LAYER M3_m ;
      RECT 0 542.535 0.07 542.605 ;
    END
  END r0_rd_out[199]
  PIN r0_rd_out[200]
    DIRECTION OUTPUT ;
    USE SIGNAL ;
    SHAPE ABUTMENT ;
    PORT
      LAYER M3_m ;
      RECT 0 543.235 0.07 543.305 ;
    END
  END r0_rd_out[200]
  PIN r0_rd_out[201]
    DIRECTION OUTPUT ;
    USE SIGNAL ;
    SHAPE ABUTMENT ;
    PORT
      LAYER M3_m ;
      RECT 0 543.935 0.07 544.005 ;
    END
  END r0_rd_out[201]
  PIN r0_rd_out[202]
    DIRECTION OUTPUT ;
    USE SIGNAL ;
    SHAPE ABUTMENT ;
    PORT
      LAYER M3_m ;
      RECT 0 544.635 0.07 544.705 ;
    END
  END r0_rd_out[202]
  PIN r0_rd_out[203]
    DIRECTION OUTPUT ;
    USE SIGNAL ;
    SHAPE ABUTMENT ;
    PORT
      LAYER M3_m ;
      RECT 0 545.335 0.07 545.405 ;
    END
  END r0_rd_out[203]
  PIN r0_rd_out[204]
    DIRECTION OUTPUT ;
    USE SIGNAL ;
    SHAPE ABUTMENT ;
    PORT
      LAYER M3_m ;
      RECT 0 546.035 0.07 546.105 ;
    END
  END r0_rd_out[204]
  PIN r0_rd_out[205]
    DIRECTION OUTPUT ;
    USE SIGNAL ;
    SHAPE ABUTMENT ;
    PORT
      LAYER M3_m ;
      RECT 0 546.735 0.07 546.805 ;
    END
  END r0_rd_out[205]
  PIN r0_rd_out[206]
    DIRECTION OUTPUT ;
    USE SIGNAL ;
    SHAPE ABUTMENT ;
    PORT
      LAYER M3_m ;
      RECT 0 547.435 0.07 547.505 ;
    END
  END r0_rd_out[206]
  PIN r0_rd_out[207]
    DIRECTION OUTPUT ;
    USE SIGNAL ;
    SHAPE ABUTMENT ;
    PORT
      LAYER M3_m ;
      RECT 0 548.135 0.07 548.205 ;
    END
  END r0_rd_out[207]
  PIN r0_rd_out[208]
    DIRECTION OUTPUT ;
    USE SIGNAL ;
    SHAPE ABUTMENT ;
    PORT
      LAYER M3_m ;
      RECT 0 548.835 0.07 548.905 ;
    END
  END r0_rd_out[208]
  PIN r0_rd_out[209]
    DIRECTION OUTPUT ;
    USE SIGNAL ;
    SHAPE ABUTMENT ;
    PORT
      LAYER M3_m ;
      RECT 0 549.535 0.07 549.605 ;
    END
  END r0_rd_out[209]
  PIN r0_rd_out[210]
    DIRECTION OUTPUT ;
    USE SIGNAL ;
    SHAPE ABUTMENT ;
    PORT
      LAYER M3_m ;
      RECT 0 550.235 0.07 550.305 ;
    END
  END r0_rd_out[210]
  PIN r0_rd_out[211]
    DIRECTION OUTPUT ;
    USE SIGNAL ;
    SHAPE ABUTMENT ;
    PORT
      LAYER M3_m ;
      RECT 0 550.935 0.07 551.005 ;
    END
  END r0_rd_out[211]
  PIN r0_rd_out[212]
    DIRECTION OUTPUT ;
    USE SIGNAL ;
    SHAPE ABUTMENT ;
    PORT
      LAYER M3_m ;
      RECT 0 551.635 0.07 551.705 ;
    END
  END r0_rd_out[212]
  PIN r0_rd_out[213]
    DIRECTION OUTPUT ;
    USE SIGNAL ;
    SHAPE ABUTMENT ;
    PORT
      LAYER M3_m ;
      RECT 0 552.335 0.07 552.405 ;
    END
  END r0_rd_out[213]
  PIN r0_rd_out[214]
    DIRECTION OUTPUT ;
    USE SIGNAL ;
    SHAPE ABUTMENT ;
    PORT
      LAYER M3_m ;
      RECT 0 553.035 0.07 553.105 ;
    END
  END r0_rd_out[214]
  PIN r0_rd_out[215]
    DIRECTION OUTPUT ;
    USE SIGNAL ;
    SHAPE ABUTMENT ;
    PORT
      LAYER M3_m ;
      RECT 0 553.735 0.07 553.805 ;
    END
  END r0_rd_out[215]
  PIN r0_rd_out[216]
    DIRECTION OUTPUT ;
    USE SIGNAL ;
    SHAPE ABUTMENT ;
    PORT
      LAYER M3_m ;
      RECT 0 554.435 0.07 554.505 ;
    END
  END r0_rd_out[216]
  PIN r0_rd_out[217]
    DIRECTION OUTPUT ;
    USE SIGNAL ;
    SHAPE ABUTMENT ;
    PORT
      LAYER M3_m ;
      RECT 0 555.135 0.07 555.205 ;
    END
  END r0_rd_out[217]
  PIN r0_rd_out[218]
    DIRECTION OUTPUT ;
    USE SIGNAL ;
    SHAPE ABUTMENT ;
    PORT
      LAYER M3_m ;
      RECT 0 555.835 0.07 555.905 ;
    END
  END r0_rd_out[218]
  PIN r0_rd_out[219]
    DIRECTION OUTPUT ;
    USE SIGNAL ;
    SHAPE ABUTMENT ;
    PORT
      LAYER M3_m ;
      RECT 0 556.535 0.07 556.605 ;
    END
  END r0_rd_out[219]
  PIN r0_rd_out[220]
    DIRECTION OUTPUT ;
    USE SIGNAL ;
    SHAPE ABUTMENT ;
    PORT
      LAYER M3_m ;
      RECT 0 557.235 0.07 557.305 ;
    END
  END r0_rd_out[220]
  PIN r0_rd_out[221]
    DIRECTION OUTPUT ;
    USE SIGNAL ;
    SHAPE ABUTMENT ;
    PORT
      LAYER M3_m ;
      RECT 0 557.935 0.07 558.005 ;
    END
  END r0_rd_out[221]
  PIN r0_rd_out[222]
    DIRECTION OUTPUT ;
    USE SIGNAL ;
    SHAPE ABUTMENT ;
    PORT
      LAYER M3_m ;
      RECT 0 558.635 0.07 558.705 ;
    END
  END r0_rd_out[222]
  PIN r0_rd_out[223]
    DIRECTION OUTPUT ;
    USE SIGNAL ;
    SHAPE ABUTMENT ;
    PORT
      LAYER M3_m ;
      RECT 0 559.335 0.07 559.405 ;
    END
  END r0_rd_out[223]
  PIN r0_rd_out[224]
    DIRECTION OUTPUT ;
    USE SIGNAL ;
    SHAPE ABUTMENT ;
    PORT
      LAYER M3_m ;
      RECT 0 560.035 0.07 560.105 ;
    END
  END r0_rd_out[224]
  PIN r0_rd_out[225]
    DIRECTION OUTPUT ;
    USE SIGNAL ;
    SHAPE ABUTMENT ;
    PORT
      LAYER M3_m ;
      RECT 0 560.735 0.07 560.805 ;
    END
  END r0_rd_out[225]
  PIN r0_rd_out[226]
    DIRECTION OUTPUT ;
    USE SIGNAL ;
    SHAPE ABUTMENT ;
    PORT
      LAYER M3_m ;
      RECT 0 561.435 0.07 561.505 ;
    END
  END r0_rd_out[226]
  PIN r0_rd_out[227]
    DIRECTION OUTPUT ;
    USE SIGNAL ;
    SHAPE ABUTMENT ;
    PORT
      LAYER M3_m ;
      RECT 0 562.135 0.07 562.205 ;
    END
  END r0_rd_out[227]
  PIN r0_rd_out[228]
    DIRECTION OUTPUT ;
    USE SIGNAL ;
    SHAPE ABUTMENT ;
    PORT
      LAYER M3_m ;
      RECT 0 562.835 0.07 562.905 ;
    END
  END r0_rd_out[228]
  PIN r0_rd_out[229]
    DIRECTION OUTPUT ;
    USE SIGNAL ;
    SHAPE ABUTMENT ;
    PORT
      LAYER M3_m ;
      RECT 0 563.535 0.07 563.605 ;
    END
  END r0_rd_out[229]
  PIN r0_rd_out[230]
    DIRECTION OUTPUT ;
    USE SIGNAL ;
    SHAPE ABUTMENT ;
    PORT
      LAYER M3_m ;
      RECT 0 564.235 0.07 564.305 ;
    END
  END r0_rd_out[230]
  PIN r0_rd_out[231]
    DIRECTION OUTPUT ;
    USE SIGNAL ;
    SHAPE ABUTMENT ;
    PORT
      LAYER M3_m ;
      RECT 0 564.935 0.07 565.005 ;
    END
  END r0_rd_out[231]
  PIN r0_rd_out[232]
    DIRECTION OUTPUT ;
    USE SIGNAL ;
    SHAPE ABUTMENT ;
    PORT
      LAYER M3_m ;
      RECT 0 565.635 0.07 565.705 ;
    END
  END r0_rd_out[232]
  PIN r0_rd_out[233]
    DIRECTION OUTPUT ;
    USE SIGNAL ;
    SHAPE ABUTMENT ;
    PORT
      LAYER M3_m ;
      RECT 0 566.335 0.07 566.405 ;
    END
  END r0_rd_out[233]
  PIN r0_rd_out[234]
    DIRECTION OUTPUT ;
    USE SIGNAL ;
    SHAPE ABUTMENT ;
    PORT
      LAYER M3_m ;
      RECT 0 567.035 0.07 567.105 ;
    END
  END r0_rd_out[234]
  PIN r0_rd_out[235]
    DIRECTION OUTPUT ;
    USE SIGNAL ;
    SHAPE ABUTMENT ;
    PORT
      LAYER M3_m ;
      RECT 0 567.735 0.07 567.805 ;
    END
  END r0_rd_out[235]
  PIN r0_rd_out[236]
    DIRECTION OUTPUT ;
    USE SIGNAL ;
    SHAPE ABUTMENT ;
    PORT
      LAYER M3_m ;
      RECT 0 568.435 0.07 568.505 ;
    END
  END r0_rd_out[236]
  PIN r0_rd_out[237]
    DIRECTION OUTPUT ;
    USE SIGNAL ;
    SHAPE ABUTMENT ;
    PORT
      LAYER M3_m ;
      RECT 0 569.135 0.07 569.205 ;
    END
  END r0_rd_out[237]
  PIN r0_rd_out[238]
    DIRECTION OUTPUT ;
    USE SIGNAL ;
    SHAPE ABUTMENT ;
    PORT
      LAYER M3_m ;
      RECT 0 569.835 0.07 569.905 ;
    END
  END r0_rd_out[238]
  PIN r0_rd_out[239]
    DIRECTION OUTPUT ;
    USE SIGNAL ;
    SHAPE ABUTMENT ;
    PORT
      LAYER M3_m ;
      RECT 0 570.535 0.07 570.605 ;
    END
  END r0_rd_out[239]
  PIN r0_rd_out[240]
    DIRECTION OUTPUT ;
    USE SIGNAL ;
    SHAPE ABUTMENT ;
    PORT
      LAYER M3_m ;
      RECT 0 571.235 0.07 571.305 ;
    END
  END r0_rd_out[240]
  PIN r0_rd_out[241]
    DIRECTION OUTPUT ;
    USE SIGNAL ;
    SHAPE ABUTMENT ;
    PORT
      LAYER M3_m ;
      RECT 0 571.935 0.07 572.005 ;
    END
  END r0_rd_out[241]
  PIN r0_rd_out[242]
    DIRECTION OUTPUT ;
    USE SIGNAL ;
    SHAPE ABUTMENT ;
    PORT
      LAYER M3_m ;
      RECT 0 572.635 0.07 572.705 ;
    END
  END r0_rd_out[242]
  PIN r0_rd_out[243]
    DIRECTION OUTPUT ;
    USE SIGNAL ;
    SHAPE ABUTMENT ;
    PORT
      LAYER M3_m ;
      RECT 0 573.335 0.07 573.405 ;
    END
  END r0_rd_out[243]
  PIN r0_rd_out[244]
    DIRECTION OUTPUT ;
    USE SIGNAL ;
    SHAPE ABUTMENT ;
    PORT
      LAYER M3_m ;
      RECT 0 574.035 0.07 574.105 ;
    END
  END r0_rd_out[244]
  PIN r0_rd_out[245]
    DIRECTION OUTPUT ;
    USE SIGNAL ;
    SHAPE ABUTMENT ;
    PORT
      LAYER M3_m ;
      RECT 0 574.735 0.07 574.805 ;
    END
  END r0_rd_out[245]
  PIN r0_rd_out[246]
    DIRECTION OUTPUT ;
    USE SIGNAL ;
    SHAPE ABUTMENT ;
    PORT
      LAYER M3_m ;
      RECT 0 575.435 0.07 575.505 ;
    END
  END r0_rd_out[246]
  PIN r0_rd_out[247]
    DIRECTION OUTPUT ;
    USE SIGNAL ;
    SHAPE ABUTMENT ;
    PORT
      LAYER M3_m ;
      RECT 0 576.135 0.07 576.205 ;
    END
  END r0_rd_out[247]
  PIN r0_rd_out[248]
    DIRECTION OUTPUT ;
    USE SIGNAL ;
    SHAPE ABUTMENT ;
    PORT
      LAYER M3_m ;
      RECT 0 576.835 0.07 576.905 ;
    END
  END r0_rd_out[248]
  PIN r0_rd_out[249]
    DIRECTION OUTPUT ;
    USE SIGNAL ;
    SHAPE ABUTMENT ;
    PORT
      LAYER M3_m ;
      RECT 0 577.535 0.07 577.605 ;
    END
  END r0_rd_out[249]
  PIN r0_rd_out[250]
    DIRECTION OUTPUT ;
    USE SIGNAL ;
    SHAPE ABUTMENT ;
    PORT
      LAYER M3_m ;
      RECT 0 578.235 0.07 578.305 ;
    END
  END r0_rd_out[250]
  PIN r0_rd_out[251]
    DIRECTION OUTPUT ;
    USE SIGNAL ;
    SHAPE ABUTMENT ;
    PORT
      LAYER M3_m ;
      RECT 0 578.935 0.07 579.005 ;
    END
  END r0_rd_out[251]
  PIN r0_rd_out[252]
    DIRECTION OUTPUT ;
    USE SIGNAL ;
    SHAPE ABUTMENT ;
    PORT
      LAYER M3_m ;
      RECT 0 579.635 0.07 579.705 ;
    END
  END r0_rd_out[252]
  PIN r0_rd_out[253]
    DIRECTION OUTPUT ;
    USE SIGNAL ;
    SHAPE ABUTMENT ;
    PORT
      LAYER M3_m ;
      RECT 0 580.335 0.07 580.405 ;
    END
  END r0_rd_out[253]
  PIN r0_rd_out[254]
    DIRECTION OUTPUT ;
    USE SIGNAL ;
    SHAPE ABUTMENT ;
    PORT
      LAYER M3_m ;
      RECT 0 581.035 0.07 581.105 ;
    END
  END r0_rd_out[254]
  PIN r0_rd_out[255]
    DIRECTION OUTPUT ;
    USE SIGNAL ;
    SHAPE ABUTMENT ;
    PORT
      LAYER M3_m ;
      RECT 0 581.735 0.07 581.805 ;
    END
  END r0_rd_out[255]
  PIN r0_rd_out[256]
    DIRECTION OUTPUT ;
    USE SIGNAL ;
    SHAPE ABUTMENT ;
    PORT
      LAYER M3_m ;
      RECT 0 582.435 0.07 582.505 ;
    END
  END r0_rd_out[256]
  PIN r0_rd_out[257]
    DIRECTION OUTPUT ;
    USE SIGNAL ;
    SHAPE ABUTMENT ;
    PORT
      LAYER M3_m ;
      RECT 0 583.135 0.07 583.205 ;
    END
  END r0_rd_out[257]
  PIN r0_rd_out[258]
    DIRECTION OUTPUT ;
    USE SIGNAL ;
    SHAPE ABUTMENT ;
    PORT
      LAYER M3_m ;
      RECT 0 583.835 0.07 583.905 ;
    END
  END r0_rd_out[258]
  PIN r0_rd_out[259]
    DIRECTION OUTPUT ;
    USE SIGNAL ;
    SHAPE ABUTMENT ;
    PORT
      LAYER M3_m ;
      RECT 0 584.535 0.07 584.605 ;
    END
  END r0_rd_out[259]
  PIN r0_rd_out[260]
    DIRECTION OUTPUT ;
    USE SIGNAL ;
    SHAPE ABUTMENT ;
    PORT
      LAYER M3_m ;
      RECT 0 585.235 0.07 585.305 ;
    END
  END r0_rd_out[260]
  PIN r0_rd_out[261]
    DIRECTION OUTPUT ;
    USE SIGNAL ;
    SHAPE ABUTMENT ;
    PORT
      LAYER M3_m ;
      RECT 0 585.935 0.07 586.005 ;
    END
  END r0_rd_out[261]
  PIN r0_rd_out[262]
    DIRECTION OUTPUT ;
    USE SIGNAL ;
    SHAPE ABUTMENT ;
    PORT
      LAYER M3_m ;
      RECT 0 586.635 0.07 586.705 ;
    END
  END r0_rd_out[262]
  PIN r0_rd_out[263]
    DIRECTION OUTPUT ;
    USE SIGNAL ;
    SHAPE ABUTMENT ;
    PORT
      LAYER M3_m ;
      RECT 0 587.335 0.07 587.405 ;
    END
  END r0_rd_out[263]
  PIN r0_rd_out[264]
    DIRECTION OUTPUT ;
    USE SIGNAL ;
    SHAPE ABUTMENT ;
    PORT
      LAYER M3_m ;
      RECT 0 588.035 0.07 588.105 ;
    END
  END r0_rd_out[264]
  PIN r0_rd_out[265]
    DIRECTION OUTPUT ;
    USE SIGNAL ;
    SHAPE ABUTMENT ;
    PORT
      LAYER M3_m ;
      RECT 0 588.735 0.07 588.805 ;
    END
  END r0_rd_out[265]
  PIN r0_rd_out[266]
    DIRECTION OUTPUT ;
    USE SIGNAL ;
    SHAPE ABUTMENT ;
    PORT
      LAYER M3_m ;
      RECT 0 589.435 0.07 589.505 ;
    END
  END r0_rd_out[266]
  PIN r0_rd_out[267]
    DIRECTION OUTPUT ;
    USE SIGNAL ;
    SHAPE ABUTMENT ;
    PORT
      LAYER M3_m ;
      RECT 0 590.135 0.07 590.205 ;
    END
  END r0_rd_out[267]
  PIN r0_rd_out[268]
    DIRECTION OUTPUT ;
    USE SIGNAL ;
    SHAPE ABUTMENT ;
    PORT
      LAYER M3_m ;
      RECT 0 590.835 0.07 590.905 ;
    END
  END r0_rd_out[268]
  PIN r0_rd_out[269]
    DIRECTION OUTPUT ;
    USE SIGNAL ;
    SHAPE ABUTMENT ;
    PORT
      LAYER M3_m ;
      RECT 0 591.535 0.07 591.605 ;
    END
  END r0_rd_out[269]
  PIN r0_rd_out[270]
    DIRECTION OUTPUT ;
    USE SIGNAL ;
    SHAPE ABUTMENT ;
    PORT
      LAYER M3_m ;
      RECT 0 592.235 0.07 592.305 ;
    END
  END r0_rd_out[270]
  PIN r0_rd_out[271]
    DIRECTION OUTPUT ;
    USE SIGNAL ;
    SHAPE ABUTMENT ;
    PORT
      LAYER M3_m ;
      RECT 0 592.935 0.07 593.005 ;
    END
  END r0_rd_out[271]
  PIN r0_rd_out[272]
    DIRECTION OUTPUT ;
    USE SIGNAL ;
    SHAPE ABUTMENT ;
    PORT
      LAYER M3_m ;
      RECT 0 593.635 0.07 593.705 ;
    END
  END r0_rd_out[272]
  PIN r0_rd_out[273]
    DIRECTION OUTPUT ;
    USE SIGNAL ;
    SHAPE ABUTMENT ;
    PORT
      LAYER M3_m ;
      RECT 0 594.335 0.07 594.405 ;
    END
  END r0_rd_out[273]
  PIN r0_rd_out[274]
    DIRECTION OUTPUT ;
    USE SIGNAL ;
    SHAPE ABUTMENT ;
    PORT
      LAYER M3_m ;
      RECT 0 595.035 0.07 595.105 ;
    END
  END r0_rd_out[274]
  PIN r0_rd_out[275]
    DIRECTION OUTPUT ;
    USE SIGNAL ;
    SHAPE ABUTMENT ;
    PORT
      LAYER M3_m ;
      RECT 0 595.735 0.07 595.805 ;
    END
  END r0_rd_out[275]
  PIN r0_rd_out[276]
    DIRECTION OUTPUT ;
    USE SIGNAL ;
    SHAPE ABUTMENT ;
    PORT
      LAYER M3_m ;
      RECT 0 596.435 0.07 596.505 ;
    END
  END r0_rd_out[276]
  PIN r0_rd_out[277]
    DIRECTION OUTPUT ;
    USE SIGNAL ;
    SHAPE ABUTMENT ;
    PORT
      LAYER M3_m ;
      RECT 0 597.135 0.07 597.205 ;
    END
  END r0_rd_out[277]
  PIN r0_rd_out[278]
    DIRECTION OUTPUT ;
    USE SIGNAL ;
    SHAPE ABUTMENT ;
    PORT
      LAYER M3_m ;
      RECT 0 597.835 0.07 597.905 ;
    END
  END r0_rd_out[278]
  PIN r0_rd_out[279]
    DIRECTION OUTPUT ;
    USE SIGNAL ;
    SHAPE ABUTMENT ;
    PORT
      LAYER M3_m ;
      RECT 0 598.535 0.07 598.605 ;
    END
  END r0_rd_out[279]
  PIN r0_rd_out[280]
    DIRECTION OUTPUT ;
    USE SIGNAL ;
    SHAPE ABUTMENT ;
    PORT
      LAYER M3_m ;
      RECT 0 599.235 0.07 599.305 ;
    END
  END r0_rd_out[280]
  PIN r0_rd_out[281]
    DIRECTION OUTPUT ;
    USE SIGNAL ;
    SHAPE ABUTMENT ;
    PORT
      LAYER M3_m ;
      RECT 0 599.935 0.07 600.005 ;
    END
  END r0_rd_out[281]
  PIN r0_rd_out[282]
    DIRECTION OUTPUT ;
    USE SIGNAL ;
    SHAPE ABUTMENT ;
    PORT
      LAYER M3_m ;
      RECT 0 600.635 0.07 600.705 ;
    END
  END r0_rd_out[282]
  PIN r0_rd_out[283]
    DIRECTION OUTPUT ;
    USE SIGNAL ;
    SHAPE ABUTMENT ;
    PORT
      LAYER M3_m ;
      RECT 0 601.335 0.07 601.405 ;
    END
  END r0_rd_out[283]
  PIN r0_rd_out[284]
    DIRECTION OUTPUT ;
    USE SIGNAL ;
    SHAPE ABUTMENT ;
    PORT
      LAYER M3_m ;
      RECT 0 602.035 0.07 602.105 ;
    END
  END r0_rd_out[284]
  PIN r0_rd_out[285]
    DIRECTION OUTPUT ;
    USE SIGNAL ;
    SHAPE ABUTMENT ;
    PORT
      LAYER M3_m ;
      RECT 0 602.735 0.07 602.805 ;
    END
  END r0_rd_out[285]
  PIN r0_rd_out[286]
    DIRECTION OUTPUT ;
    USE SIGNAL ;
    SHAPE ABUTMENT ;
    PORT
      LAYER M3_m ;
      RECT 0 603.435 0.07 603.505 ;
    END
  END r0_rd_out[286]
  PIN r0_rd_out[287]
    DIRECTION OUTPUT ;
    USE SIGNAL ;
    SHAPE ABUTMENT ;
    PORT
      LAYER M3_m ;
      RECT 0 604.135 0.07 604.205 ;
    END
  END r0_rd_out[287]
  PIN r0_rd_out[288]
    DIRECTION OUTPUT ;
    USE SIGNAL ;
    SHAPE ABUTMENT ;
    PORT
      LAYER M3_m ;
      RECT 0 604.835 0.07 604.905 ;
    END
  END r0_rd_out[288]
  PIN r0_rd_out[289]
    DIRECTION OUTPUT ;
    USE SIGNAL ;
    SHAPE ABUTMENT ;
    PORT
      LAYER M3_m ;
      RECT 0 605.535 0.07 605.605 ;
    END
  END r0_rd_out[289]
  PIN r0_rd_out[290]
    DIRECTION OUTPUT ;
    USE SIGNAL ;
    SHAPE ABUTMENT ;
    PORT
      LAYER M3_m ;
      RECT 0 606.235 0.07 606.305 ;
    END
  END r0_rd_out[290]
  PIN r0_rd_out[291]
    DIRECTION OUTPUT ;
    USE SIGNAL ;
    SHAPE ABUTMENT ;
    PORT
      LAYER M3_m ;
      RECT 0 606.935 0.07 607.005 ;
    END
  END r0_rd_out[291]
  PIN r0_rd_out[292]
    DIRECTION OUTPUT ;
    USE SIGNAL ;
    SHAPE ABUTMENT ;
    PORT
      LAYER M3_m ;
      RECT 0 607.635 0.07 607.705 ;
    END
  END r0_rd_out[292]
  PIN r0_rd_out[293]
    DIRECTION OUTPUT ;
    USE SIGNAL ;
    SHAPE ABUTMENT ;
    PORT
      LAYER M3_m ;
      RECT 0 608.335 0.07 608.405 ;
    END
  END r0_rd_out[293]
  PIN r0_rd_out[294]
    DIRECTION OUTPUT ;
    USE SIGNAL ;
    SHAPE ABUTMENT ;
    PORT
      LAYER M3_m ;
      RECT 0 609.035 0.07 609.105 ;
    END
  END r0_rd_out[294]
  PIN r0_rd_out[295]
    DIRECTION OUTPUT ;
    USE SIGNAL ;
    SHAPE ABUTMENT ;
    PORT
      LAYER M3_m ;
      RECT 0 609.735 0.07 609.805 ;
    END
  END r0_rd_out[295]
  PIN r0_rd_out[296]
    DIRECTION OUTPUT ;
    USE SIGNAL ;
    SHAPE ABUTMENT ;
    PORT
      LAYER M3_m ;
      RECT 0 610.435 0.07 610.505 ;
    END
  END r0_rd_out[296]
  PIN r0_rd_out[297]
    DIRECTION OUTPUT ;
    USE SIGNAL ;
    SHAPE ABUTMENT ;
    PORT
      LAYER M3_m ;
      RECT 0 611.135 0.07 611.205 ;
    END
  END r0_rd_out[297]
  PIN r0_rd_out[298]
    DIRECTION OUTPUT ;
    USE SIGNAL ;
    SHAPE ABUTMENT ;
    PORT
      LAYER M3_m ;
      RECT 0 611.835 0.07 611.905 ;
    END
  END r0_rd_out[298]
  PIN r0_rd_out[299]
    DIRECTION OUTPUT ;
    USE SIGNAL ;
    SHAPE ABUTMENT ;
    PORT
      LAYER M3_m ;
      RECT 0 612.535 0.07 612.605 ;
    END
  END r0_rd_out[299]
  PIN r0_rd_out[300]
    DIRECTION OUTPUT ;
    USE SIGNAL ;
    SHAPE ABUTMENT ;
    PORT
      LAYER M3_m ;
      RECT 0 613.235 0.07 613.305 ;
    END
  END r0_rd_out[300]
  PIN r0_rd_out[301]
    DIRECTION OUTPUT ;
    USE SIGNAL ;
    SHAPE ABUTMENT ;
    PORT
      LAYER M3_m ;
      RECT 0 613.935 0.07 614.005 ;
    END
  END r0_rd_out[301]
  PIN r0_rd_out[302]
    DIRECTION OUTPUT ;
    USE SIGNAL ;
    SHAPE ABUTMENT ;
    PORT
      LAYER M3_m ;
      RECT 0 614.635 0.07 614.705 ;
    END
  END r0_rd_out[302]
  PIN r0_rd_out[303]
    DIRECTION OUTPUT ;
    USE SIGNAL ;
    SHAPE ABUTMENT ;
    PORT
      LAYER M3_m ;
      RECT 0 615.335 0.07 615.405 ;
    END
  END r0_rd_out[303]
  PIN r0_rd_out[304]
    DIRECTION OUTPUT ;
    USE SIGNAL ;
    SHAPE ABUTMENT ;
    PORT
      LAYER M3_m ;
      RECT 0 616.035 0.07 616.105 ;
    END
  END r0_rd_out[304]
  PIN r0_rd_out[305]
    DIRECTION OUTPUT ;
    USE SIGNAL ;
    SHAPE ABUTMENT ;
    PORT
      LAYER M3_m ;
      RECT 0 616.735 0.07 616.805 ;
    END
  END r0_rd_out[305]
  PIN r0_rd_out[306]
    DIRECTION OUTPUT ;
    USE SIGNAL ;
    SHAPE ABUTMENT ;
    PORT
      LAYER M3_m ;
      RECT 0 617.435 0.07 617.505 ;
    END
  END r0_rd_out[306]
  PIN r0_rd_out[307]
    DIRECTION OUTPUT ;
    USE SIGNAL ;
    SHAPE ABUTMENT ;
    PORT
      LAYER M3_m ;
      RECT 0 618.135 0.07 618.205 ;
    END
  END r0_rd_out[307]
  PIN r0_rd_out[308]
    DIRECTION OUTPUT ;
    USE SIGNAL ;
    SHAPE ABUTMENT ;
    PORT
      LAYER M3_m ;
      RECT 0 618.835 0.07 618.905 ;
    END
  END r0_rd_out[308]
  PIN r0_rd_out[309]
    DIRECTION OUTPUT ;
    USE SIGNAL ;
    SHAPE ABUTMENT ;
    PORT
      LAYER M3_m ;
      RECT 0 619.535 0.07 619.605 ;
    END
  END r0_rd_out[309]
  PIN r0_rd_out[310]
    DIRECTION OUTPUT ;
    USE SIGNAL ;
    SHAPE ABUTMENT ;
    PORT
      LAYER M3_m ;
      RECT 0 620.235 0.07 620.305 ;
    END
  END r0_rd_out[310]
  PIN r0_rd_out[311]
    DIRECTION OUTPUT ;
    USE SIGNAL ;
    SHAPE ABUTMENT ;
    PORT
      LAYER M3_m ;
      RECT 0 620.935 0.07 621.005 ;
    END
  END r0_rd_out[311]
  PIN r0_rd_out[312]
    DIRECTION OUTPUT ;
    USE SIGNAL ;
    SHAPE ABUTMENT ;
    PORT
      LAYER M3_m ;
      RECT 0 621.635 0.07 621.705 ;
    END
  END r0_rd_out[312]
  PIN r0_rd_out[313]
    DIRECTION OUTPUT ;
    USE SIGNAL ;
    SHAPE ABUTMENT ;
    PORT
      LAYER M3_m ;
      RECT 0 622.335 0.07 622.405 ;
    END
  END r0_rd_out[313]
  PIN r0_rd_out[314]
    DIRECTION OUTPUT ;
    USE SIGNAL ;
    SHAPE ABUTMENT ;
    PORT
      LAYER M3_m ;
      RECT 0 623.035 0.07 623.105 ;
    END
  END r0_rd_out[314]
  PIN r0_rd_out[315]
    DIRECTION OUTPUT ;
    USE SIGNAL ;
    SHAPE ABUTMENT ;
    PORT
      LAYER M3_m ;
      RECT 0 623.735 0.07 623.805 ;
    END
  END r0_rd_out[315]
  PIN r0_rd_out[316]
    DIRECTION OUTPUT ;
    USE SIGNAL ;
    SHAPE ABUTMENT ;
    PORT
      LAYER M3_m ;
      RECT 0 624.435 0.07 624.505 ;
    END
  END r0_rd_out[316]
  PIN r0_rd_out[317]
    DIRECTION OUTPUT ;
    USE SIGNAL ;
    SHAPE ABUTMENT ;
    PORT
      LAYER M3_m ;
      RECT 0 625.135 0.07 625.205 ;
    END
  END r0_rd_out[317]
  PIN r0_rd_out[318]
    DIRECTION OUTPUT ;
    USE SIGNAL ;
    SHAPE ABUTMENT ;
    PORT
      LAYER M3_m ;
      RECT 0 625.835 0.07 625.905 ;
    END
  END r0_rd_out[318]
  PIN r0_rd_out[319]
    DIRECTION OUTPUT ;
    USE SIGNAL ;
    SHAPE ABUTMENT ;
    PORT
      LAYER M3_m ;
      RECT 0 626.535 0.07 626.605 ;
    END
  END r0_rd_out[319]
  PIN r0_rd_out[320]
    DIRECTION OUTPUT ;
    USE SIGNAL ;
    SHAPE ABUTMENT ;
    PORT
      LAYER M3_m ;
      RECT 0 627.235 0.07 627.305 ;
    END
  END r0_rd_out[320]
  PIN r0_rd_out[321]
    DIRECTION OUTPUT ;
    USE SIGNAL ;
    SHAPE ABUTMENT ;
    PORT
      LAYER M3_m ;
      RECT 0 627.935 0.07 628.005 ;
    END
  END r0_rd_out[321]
  PIN r0_rd_out[322]
    DIRECTION OUTPUT ;
    USE SIGNAL ;
    SHAPE ABUTMENT ;
    PORT
      LAYER M3_m ;
      RECT 0 628.635 0.07 628.705 ;
    END
  END r0_rd_out[322]
  PIN r0_rd_out[323]
    DIRECTION OUTPUT ;
    USE SIGNAL ;
    SHAPE ABUTMENT ;
    PORT
      LAYER M3_m ;
      RECT 0 629.335 0.07 629.405 ;
    END
  END r0_rd_out[323]
  PIN r0_rd_out[324]
    DIRECTION OUTPUT ;
    USE SIGNAL ;
    SHAPE ABUTMENT ;
    PORT
      LAYER M3_m ;
      RECT 0 630.035 0.07 630.105 ;
    END
  END r0_rd_out[324]
  PIN r0_rd_out[325]
    DIRECTION OUTPUT ;
    USE SIGNAL ;
    SHAPE ABUTMENT ;
    PORT
      LAYER M3_m ;
      RECT 0 630.735 0.07 630.805 ;
    END
  END r0_rd_out[325]
  PIN r0_rd_out[326]
    DIRECTION OUTPUT ;
    USE SIGNAL ;
    SHAPE ABUTMENT ;
    PORT
      LAYER M3_m ;
      RECT 0 631.435 0.07 631.505 ;
    END
  END r0_rd_out[326]
  PIN r0_rd_out[327]
    DIRECTION OUTPUT ;
    USE SIGNAL ;
    SHAPE ABUTMENT ;
    PORT
      LAYER M3_m ;
      RECT 0 632.135 0.07 632.205 ;
    END
  END r0_rd_out[327]
  PIN r0_rd_out[328]
    DIRECTION OUTPUT ;
    USE SIGNAL ;
    SHAPE ABUTMENT ;
    PORT
      LAYER M3_m ;
      RECT 0 632.835 0.07 632.905 ;
    END
  END r0_rd_out[328]
  PIN r0_rd_out[329]
    DIRECTION OUTPUT ;
    USE SIGNAL ;
    SHAPE ABUTMENT ;
    PORT
      LAYER M3_m ;
      RECT 0 633.535 0.07 633.605 ;
    END
  END r0_rd_out[329]
  PIN r0_rd_out[330]
    DIRECTION OUTPUT ;
    USE SIGNAL ;
    SHAPE ABUTMENT ;
    PORT
      LAYER M3_m ;
      RECT 0 634.235 0.07 634.305 ;
    END
  END r0_rd_out[330]
  PIN r0_rd_out[331]
    DIRECTION OUTPUT ;
    USE SIGNAL ;
    SHAPE ABUTMENT ;
    PORT
      LAYER M3_m ;
      RECT 0 634.935 0.07 635.005 ;
    END
  END r0_rd_out[331]
  PIN r0_rd_out[332]
    DIRECTION OUTPUT ;
    USE SIGNAL ;
    SHAPE ABUTMENT ;
    PORT
      LAYER M3_m ;
      RECT 0 635.635 0.07 635.705 ;
    END
  END r0_rd_out[332]
  PIN r0_rd_out[333]
    DIRECTION OUTPUT ;
    USE SIGNAL ;
    SHAPE ABUTMENT ;
    PORT
      LAYER M3_m ;
      RECT 0 636.335 0.07 636.405 ;
    END
  END r0_rd_out[333]
  PIN r0_rd_out[334]
    DIRECTION OUTPUT ;
    USE SIGNAL ;
    SHAPE ABUTMENT ;
    PORT
      LAYER M3_m ;
      RECT 0 637.035 0.07 637.105 ;
    END
  END r0_rd_out[334]
  PIN r0_rd_out[335]
    DIRECTION OUTPUT ;
    USE SIGNAL ;
    SHAPE ABUTMENT ;
    PORT
      LAYER M3_m ;
      RECT 0 637.735 0.07 637.805 ;
    END
  END r0_rd_out[335]
  PIN r0_rd_out[336]
    DIRECTION OUTPUT ;
    USE SIGNAL ;
    SHAPE ABUTMENT ;
    PORT
      LAYER M3_m ;
      RECT 0 638.435 0.07 638.505 ;
    END
  END r0_rd_out[336]
  PIN r0_rd_out[337]
    DIRECTION OUTPUT ;
    USE SIGNAL ;
    SHAPE ABUTMENT ;
    PORT
      LAYER M3_m ;
      RECT 0 639.135 0.07 639.205 ;
    END
  END r0_rd_out[337]
  PIN r0_rd_out[338]
    DIRECTION OUTPUT ;
    USE SIGNAL ;
    SHAPE ABUTMENT ;
    PORT
      LAYER M3_m ;
      RECT 0 639.835 0.07 639.905 ;
    END
  END r0_rd_out[338]
  PIN r0_rd_out[339]
    DIRECTION OUTPUT ;
    USE SIGNAL ;
    SHAPE ABUTMENT ;
    PORT
      LAYER M3_m ;
      RECT 0 640.535 0.07 640.605 ;
    END
  END r0_rd_out[339]
  PIN r0_rd_out[340]
    DIRECTION OUTPUT ;
    USE SIGNAL ;
    SHAPE ABUTMENT ;
    PORT
      LAYER M3_m ;
      RECT 0 641.235 0.07 641.305 ;
    END
  END r0_rd_out[340]
  PIN r0_rd_out[341]
    DIRECTION OUTPUT ;
    USE SIGNAL ;
    SHAPE ABUTMENT ;
    PORT
      LAYER M3_m ;
      RECT 0 641.935 0.07 642.005 ;
    END
  END r0_rd_out[341]
  PIN r0_rd_out[342]
    DIRECTION OUTPUT ;
    USE SIGNAL ;
    SHAPE ABUTMENT ;
    PORT
      LAYER M3_m ;
      RECT 0 642.635 0.07 642.705 ;
    END
  END r0_rd_out[342]
  PIN r0_rd_out[343]
    DIRECTION OUTPUT ;
    USE SIGNAL ;
    SHAPE ABUTMENT ;
    PORT
      LAYER M3_m ;
      RECT 0 643.335 0.07 643.405 ;
    END
  END r0_rd_out[343]
  PIN r0_rd_out[344]
    DIRECTION OUTPUT ;
    USE SIGNAL ;
    SHAPE ABUTMENT ;
    PORT
      LAYER M3_m ;
      RECT 0 644.035 0.07 644.105 ;
    END
  END r0_rd_out[344]
  PIN r0_rd_out[345]
    DIRECTION OUTPUT ;
    USE SIGNAL ;
    SHAPE ABUTMENT ;
    PORT
      LAYER M3_m ;
      RECT 0 644.735 0.07 644.805 ;
    END
  END r0_rd_out[345]
  PIN r0_rd_out[346]
    DIRECTION OUTPUT ;
    USE SIGNAL ;
    SHAPE ABUTMENT ;
    PORT
      LAYER M3_m ;
      RECT 0 645.435 0.07 645.505 ;
    END
  END r0_rd_out[346]
  PIN r0_rd_out[347]
    DIRECTION OUTPUT ;
    USE SIGNAL ;
    SHAPE ABUTMENT ;
    PORT
      LAYER M3_m ;
      RECT 0 646.135 0.07 646.205 ;
    END
  END r0_rd_out[347]
  PIN r0_rd_out[348]
    DIRECTION OUTPUT ;
    USE SIGNAL ;
    SHAPE ABUTMENT ;
    PORT
      LAYER M3_m ;
      RECT 0 646.835 0.07 646.905 ;
    END
  END r0_rd_out[348]
  PIN r0_rd_out[349]
    DIRECTION OUTPUT ;
    USE SIGNAL ;
    SHAPE ABUTMENT ;
    PORT
      LAYER M3_m ;
      RECT 0 647.535 0.07 647.605 ;
    END
  END r0_rd_out[349]
  PIN r0_rd_out[350]
    DIRECTION OUTPUT ;
    USE SIGNAL ;
    SHAPE ABUTMENT ;
    PORT
      LAYER M3_m ;
      RECT 0 648.235 0.07 648.305 ;
    END
  END r0_rd_out[350]
  PIN r0_rd_out[351]
    DIRECTION OUTPUT ;
    USE SIGNAL ;
    SHAPE ABUTMENT ;
    PORT
      LAYER M3_m ;
      RECT 0 648.935 0.07 649.005 ;
    END
  END r0_rd_out[351]
  PIN r0_rd_out[352]
    DIRECTION OUTPUT ;
    USE SIGNAL ;
    SHAPE ABUTMENT ;
    PORT
      LAYER M3_m ;
      RECT 0 649.635 0.07 649.705 ;
    END
  END r0_rd_out[352]
  PIN r0_rd_out[353]
    DIRECTION OUTPUT ;
    USE SIGNAL ;
    SHAPE ABUTMENT ;
    PORT
      LAYER M3_m ;
      RECT 0 650.335 0.07 650.405 ;
    END
  END r0_rd_out[353]
  PIN r0_rd_out[354]
    DIRECTION OUTPUT ;
    USE SIGNAL ;
    SHAPE ABUTMENT ;
    PORT
      LAYER M3_m ;
      RECT 0 651.035 0.07 651.105 ;
    END
  END r0_rd_out[354]
  PIN r0_rd_out[355]
    DIRECTION OUTPUT ;
    USE SIGNAL ;
    SHAPE ABUTMENT ;
    PORT
      LAYER M3_m ;
      RECT 0 651.735 0.07 651.805 ;
    END
  END r0_rd_out[355]
  PIN r0_rd_out[356]
    DIRECTION OUTPUT ;
    USE SIGNAL ;
    SHAPE ABUTMENT ;
    PORT
      LAYER M3_m ;
      RECT 0 652.435 0.07 652.505 ;
    END
  END r0_rd_out[356]
  PIN r0_rd_out[357]
    DIRECTION OUTPUT ;
    USE SIGNAL ;
    SHAPE ABUTMENT ;
    PORT
      LAYER M3_m ;
      RECT 0 653.135 0.07 653.205 ;
    END
  END r0_rd_out[357]
  PIN r0_rd_out[358]
    DIRECTION OUTPUT ;
    USE SIGNAL ;
    SHAPE ABUTMENT ;
    PORT
      LAYER M3_m ;
      RECT 0 653.835 0.07 653.905 ;
    END
  END r0_rd_out[358]
  PIN r0_rd_out[359]
    DIRECTION OUTPUT ;
    USE SIGNAL ;
    SHAPE ABUTMENT ;
    PORT
      LAYER M3_m ;
      RECT 0 654.535 0.07 654.605 ;
    END
  END r0_rd_out[359]
  PIN r0_rd_out[360]
    DIRECTION OUTPUT ;
    USE SIGNAL ;
    SHAPE ABUTMENT ;
    PORT
      LAYER M3_m ;
      RECT 0 655.235 0.07 655.305 ;
    END
  END r0_rd_out[360]
  PIN r0_rd_out[361]
    DIRECTION OUTPUT ;
    USE SIGNAL ;
    SHAPE ABUTMENT ;
    PORT
      LAYER M3_m ;
      RECT 0 655.935 0.07 656.005 ;
    END
  END r0_rd_out[361]
  PIN r0_rd_out[362]
    DIRECTION OUTPUT ;
    USE SIGNAL ;
    SHAPE ABUTMENT ;
    PORT
      LAYER M3_m ;
      RECT 0 656.635 0.07 656.705 ;
    END
  END r0_rd_out[362]
  PIN r0_rd_out[363]
    DIRECTION OUTPUT ;
    USE SIGNAL ;
    SHAPE ABUTMENT ;
    PORT
      LAYER M3_m ;
      RECT 0 657.335 0.07 657.405 ;
    END
  END r0_rd_out[363]
  PIN r0_rd_out[364]
    DIRECTION OUTPUT ;
    USE SIGNAL ;
    SHAPE ABUTMENT ;
    PORT
      LAYER M3_m ;
      RECT 0 658.035 0.07 658.105 ;
    END
  END r0_rd_out[364]
  PIN r0_rd_out[365]
    DIRECTION OUTPUT ;
    USE SIGNAL ;
    SHAPE ABUTMENT ;
    PORT
      LAYER M3_m ;
      RECT 0 658.735 0.07 658.805 ;
    END
  END r0_rd_out[365]
  PIN r0_rd_out[366]
    DIRECTION OUTPUT ;
    USE SIGNAL ;
    SHAPE ABUTMENT ;
    PORT
      LAYER M3_m ;
      RECT 0 659.435 0.07 659.505 ;
    END
  END r0_rd_out[366]
  PIN r0_rd_out[367]
    DIRECTION OUTPUT ;
    USE SIGNAL ;
    SHAPE ABUTMENT ;
    PORT
      LAYER M3_m ;
      RECT 0 660.135 0.07 660.205 ;
    END
  END r0_rd_out[367]
  PIN r0_rd_out[368]
    DIRECTION OUTPUT ;
    USE SIGNAL ;
    SHAPE ABUTMENT ;
    PORT
      LAYER M3_m ;
      RECT 0 660.835 0.07 660.905 ;
    END
  END r0_rd_out[368]
  PIN r0_rd_out[369]
    DIRECTION OUTPUT ;
    USE SIGNAL ;
    SHAPE ABUTMENT ;
    PORT
      LAYER M3_m ;
      RECT 0 661.535 0.07 661.605 ;
    END
  END r0_rd_out[369]
  PIN r0_rd_out[370]
    DIRECTION OUTPUT ;
    USE SIGNAL ;
    SHAPE ABUTMENT ;
    PORT
      LAYER M3_m ;
      RECT 0 662.235 0.07 662.305 ;
    END
  END r0_rd_out[370]
  PIN r0_rd_out[371]
    DIRECTION OUTPUT ;
    USE SIGNAL ;
    SHAPE ABUTMENT ;
    PORT
      LAYER M3_m ;
      RECT 0 662.935 0.07 663.005 ;
    END
  END r0_rd_out[371]
  PIN r0_rd_out[372]
    DIRECTION OUTPUT ;
    USE SIGNAL ;
    SHAPE ABUTMENT ;
    PORT
      LAYER M3_m ;
      RECT 0 663.635 0.07 663.705 ;
    END
  END r0_rd_out[372]
  PIN r0_rd_out[373]
    DIRECTION OUTPUT ;
    USE SIGNAL ;
    SHAPE ABUTMENT ;
    PORT
      LAYER M3_m ;
      RECT 0 664.335 0.07 664.405 ;
    END
  END r0_rd_out[373]
  PIN r0_rd_out[374]
    DIRECTION OUTPUT ;
    USE SIGNAL ;
    SHAPE ABUTMENT ;
    PORT
      LAYER M3_m ;
      RECT 0 665.035 0.07 665.105 ;
    END
  END r0_rd_out[374]
  PIN r0_rd_out[375]
    DIRECTION OUTPUT ;
    USE SIGNAL ;
    SHAPE ABUTMENT ;
    PORT
      LAYER M3_m ;
      RECT 0 665.735 0.07 665.805 ;
    END
  END r0_rd_out[375]
  PIN r0_rd_out[376]
    DIRECTION OUTPUT ;
    USE SIGNAL ;
    SHAPE ABUTMENT ;
    PORT
      LAYER M3_m ;
      RECT 0 666.435 0.07 666.505 ;
    END
  END r0_rd_out[376]
  PIN r0_rd_out[377]
    DIRECTION OUTPUT ;
    USE SIGNAL ;
    SHAPE ABUTMENT ;
    PORT
      LAYER M3_m ;
      RECT 0 667.135 0.07 667.205 ;
    END
  END r0_rd_out[377]
  PIN r0_rd_out[378]
    DIRECTION OUTPUT ;
    USE SIGNAL ;
    SHAPE ABUTMENT ;
    PORT
      LAYER M3_m ;
      RECT 0 667.835 0.07 667.905 ;
    END
  END r0_rd_out[378]
  PIN r0_rd_out[379]
    DIRECTION OUTPUT ;
    USE SIGNAL ;
    SHAPE ABUTMENT ;
    PORT
      LAYER M3_m ;
      RECT 0 668.535 0.07 668.605 ;
    END
  END r0_rd_out[379]
  PIN r0_rd_out[380]
    DIRECTION OUTPUT ;
    USE SIGNAL ;
    SHAPE ABUTMENT ;
    PORT
      LAYER M3_m ;
      RECT 0 669.235 0.07 669.305 ;
    END
  END r0_rd_out[380]
  PIN r0_rd_out[381]
    DIRECTION OUTPUT ;
    USE SIGNAL ;
    SHAPE ABUTMENT ;
    PORT
      LAYER M3_m ;
      RECT 0 669.935 0.07 670.005 ;
    END
  END r0_rd_out[381]
  PIN r0_rd_out[382]
    DIRECTION OUTPUT ;
    USE SIGNAL ;
    SHAPE ABUTMENT ;
    PORT
      LAYER M3_m ;
      RECT 0 670.635 0.07 670.705 ;
    END
  END r0_rd_out[382]
  PIN r0_rd_out[383]
    DIRECTION OUTPUT ;
    USE SIGNAL ;
    SHAPE ABUTMENT ;
    PORT
      LAYER M3_m ;
      RECT 0 671.335 0.07 671.405 ;
    END
  END r0_rd_out[383]
  PIN r0_rd_out[384]
    DIRECTION OUTPUT ;
    USE SIGNAL ;
    SHAPE ABUTMENT ;
    PORT
      LAYER M3_m ;
      RECT 0 672.035 0.07 672.105 ;
    END
  END r0_rd_out[384]
  PIN r0_rd_out[385]
    DIRECTION OUTPUT ;
    USE SIGNAL ;
    SHAPE ABUTMENT ;
    PORT
      LAYER M3_m ;
      RECT 0 672.735 0.07 672.805 ;
    END
  END r0_rd_out[385]
  PIN r0_rd_out[386]
    DIRECTION OUTPUT ;
    USE SIGNAL ;
    SHAPE ABUTMENT ;
    PORT
      LAYER M3_m ;
      RECT 0 673.435 0.07 673.505 ;
    END
  END r0_rd_out[386]
  PIN r0_rd_out[387]
    DIRECTION OUTPUT ;
    USE SIGNAL ;
    SHAPE ABUTMENT ;
    PORT
      LAYER M3_m ;
      RECT 0 674.135 0.07 674.205 ;
    END
  END r0_rd_out[387]
  PIN r0_rd_out[388]
    DIRECTION OUTPUT ;
    USE SIGNAL ;
    SHAPE ABUTMENT ;
    PORT
      LAYER M3_m ;
      RECT 0 674.835 0.07 674.905 ;
    END
  END r0_rd_out[388]
  PIN r0_rd_out[389]
    DIRECTION OUTPUT ;
    USE SIGNAL ;
    SHAPE ABUTMENT ;
    PORT
      LAYER M3_m ;
      RECT 0 675.535 0.07 675.605 ;
    END
  END r0_rd_out[389]
  PIN r0_rd_out[390]
    DIRECTION OUTPUT ;
    USE SIGNAL ;
    SHAPE ABUTMENT ;
    PORT
      LAYER M3_m ;
      RECT 0 676.235 0.07 676.305 ;
    END
  END r0_rd_out[390]
  PIN r0_rd_out[391]
    DIRECTION OUTPUT ;
    USE SIGNAL ;
    SHAPE ABUTMENT ;
    PORT
      LAYER M3_m ;
      RECT 0 676.935 0.07 677.005 ;
    END
  END r0_rd_out[391]
  PIN r0_rd_out[392]
    DIRECTION OUTPUT ;
    USE SIGNAL ;
    SHAPE ABUTMENT ;
    PORT
      LAYER M3_m ;
      RECT 0 677.635 0.07 677.705 ;
    END
  END r0_rd_out[392]
  PIN r0_rd_out[393]
    DIRECTION OUTPUT ;
    USE SIGNAL ;
    SHAPE ABUTMENT ;
    PORT
      LAYER M3_m ;
      RECT 0 678.335 0.07 678.405 ;
    END
  END r0_rd_out[393]
  PIN r0_rd_out[394]
    DIRECTION OUTPUT ;
    USE SIGNAL ;
    SHAPE ABUTMENT ;
    PORT
      LAYER M3_m ;
      RECT 0 679.035 0.07 679.105 ;
    END
  END r0_rd_out[394]
  PIN r0_rd_out[395]
    DIRECTION OUTPUT ;
    USE SIGNAL ;
    SHAPE ABUTMENT ;
    PORT
      LAYER M3_m ;
      RECT 0 679.735 0.07 679.805 ;
    END
  END r0_rd_out[395]
  PIN r0_rd_out[396]
    DIRECTION OUTPUT ;
    USE SIGNAL ;
    SHAPE ABUTMENT ;
    PORT
      LAYER M3_m ;
      RECT 0 680.435 0.07 680.505 ;
    END
  END r0_rd_out[396]
  PIN r0_rd_out[397]
    DIRECTION OUTPUT ;
    USE SIGNAL ;
    SHAPE ABUTMENT ;
    PORT
      LAYER M3_m ;
      RECT 0 681.135 0.07 681.205 ;
    END
  END r0_rd_out[397]
  PIN r0_rd_out[398]
    DIRECTION OUTPUT ;
    USE SIGNAL ;
    SHAPE ABUTMENT ;
    PORT
      LAYER M3_m ;
      RECT 0 681.835 0.07 681.905 ;
    END
  END r0_rd_out[398]
  PIN r0_rd_out[399]
    DIRECTION OUTPUT ;
    USE SIGNAL ;
    SHAPE ABUTMENT ;
    PORT
      LAYER M3_m ;
      RECT 0 682.535 0.07 682.605 ;
    END
  END r0_rd_out[399]
  PIN r0_rd_out[400]
    DIRECTION OUTPUT ;
    USE SIGNAL ;
    SHAPE ABUTMENT ;
    PORT
      LAYER M3_m ;
      RECT 0 683.235 0.07 683.305 ;
    END
  END r0_rd_out[400]
  PIN r0_rd_out[401]
    DIRECTION OUTPUT ;
    USE SIGNAL ;
    SHAPE ABUTMENT ;
    PORT
      LAYER M3_m ;
      RECT 0 683.935 0.07 684.005 ;
    END
  END r0_rd_out[401]
  PIN r0_rd_out[402]
    DIRECTION OUTPUT ;
    USE SIGNAL ;
    SHAPE ABUTMENT ;
    PORT
      LAYER M3_m ;
      RECT 0 684.635 0.07 684.705 ;
    END
  END r0_rd_out[402]
  PIN r0_rd_out[403]
    DIRECTION OUTPUT ;
    USE SIGNAL ;
    SHAPE ABUTMENT ;
    PORT
      LAYER M3_m ;
      RECT 0 685.335 0.07 685.405 ;
    END
  END r0_rd_out[403]
  PIN r0_rd_out[404]
    DIRECTION OUTPUT ;
    USE SIGNAL ;
    SHAPE ABUTMENT ;
    PORT
      LAYER M3_m ;
      RECT 0 686.035 0.07 686.105 ;
    END
  END r0_rd_out[404]
  PIN r0_rd_out[405]
    DIRECTION OUTPUT ;
    USE SIGNAL ;
    SHAPE ABUTMENT ;
    PORT
      LAYER M3_m ;
      RECT 0 686.735 0.07 686.805 ;
    END
  END r0_rd_out[405]
  PIN r0_rd_out[406]
    DIRECTION OUTPUT ;
    USE SIGNAL ;
    SHAPE ABUTMENT ;
    PORT
      LAYER M3_m ;
      RECT 0 687.435 0.07 687.505 ;
    END
  END r0_rd_out[406]
  PIN r0_rd_out[407]
    DIRECTION OUTPUT ;
    USE SIGNAL ;
    SHAPE ABUTMENT ;
    PORT
      LAYER M3_m ;
      RECT 0 688.135 0.07 688.205 ;
    END
  END r0_rd_out[407]
  PIN r0_rd_out[408]
    DIRECTION OUTPUT ;
    USE SIGNAL ;
    SHAPE ABUTMENT ;
    PORT
      LAYER M3_m ;
      RECT 0 688.835 0.07 688.905 ;
    END
  END r0_rd_out[408]
  PIN r0_rd_out[409]
    DIRECTION OUTPUT ;
    USE SIGNAL ;
    SHAPE ABUTMENT ;
    PORT
      LAYER M3_m ;
      RECT 0 689.535 0.07 689.605 ;
    END
  END r0_rd_out[409]
  PIN r0_rd_out[410]
    DIRECTION OUTPUT ;
    USE SIGNAL ;
    SHAPE ABUTMENT ;
    PORT
      LAYER M3_m ;
      RECT 0 690.235 0.07 690.305 ;
    END
  END r0_rd_out[410]
  PIN r0_rd_out[411]
    DIRECTION OUTPUT ;
    USE SIGNAL ;
    SHAPE ABUTMENT ;
    PORT
      LAYER M3_m ;
      RECT 0 690.935 0.07 691.005 ;
    END
  END r0_rd_out[411]
  PIN r0_rd_out[412]
    DIRECTION OUTPUT ;
    USE SIGNAL ;
    SHAPE ABUTMENT ;
    PORT
      LAYER M3_m ;
      RECT 0 691.635 0.07 691.705 ;
    END
  END r0_rd_out[412]
  PIN r0_rd_out[413]
    DIRECTION OUTPUT ;
    USE SIGNAL ;
    SHAPE ABUTMENT ;
    PORT
      LAYER M3_m ;
      RECT 0 692.335 0.07 692.405 ;
    END
  END r0_rd_out[413]
  PIN r0_rd_out[414]
    DIRECTION OUTPUT ;
    USE SIGNAL ;
    SHAPE ABUTMENT ;
    PORT
      LAYER M3_m ;
      RECT 0 693.035 0.07 693.105 ;
    END
  END r0_rd_out[414]
  PIN r0_rd_out[415]
    DIRECTION OUTPUT ;
    USE SIGNAL ;
    SHAPE ABUTMENT ;
    PORT
      LAYER M3_m ;
      RECT 0 693.735 0.07 693.805 ;
    END
  END r0_rd_out[415]
  PIN r0_rd_out[416]
    DIRECTION OUTPUT ;
    USE SIGNAL ;
    SHAPE ABUTMENT ;
    PORT
      LAYER M3_m ;
      RECT 0 694.435 0.07 694.505 ;
    END
  END r0_rd_out[416]
  PIN r0_rd_out[417]
    DIRECTION OUTPUT ;
    USE SIGNAL ;
    SHAPE ABUTMENT ;
    PORT
      LAYER M3_m ;
      RECT 0 695.135 0.07 695.205 ;
    END
  END r0_rd_out[417]
  PIN r0_rd_out[418]
    DIRECTION OUTPUT ;
    USE SIGNAL ;
    SHAPE ABUTMENT ;
    PORT
      LAYER M3_m ;
      RECT 0 695.835 0.07 695.905 ;
    END
  END r0_rd_out[418]
  PIN r0_rd_out[419]
    DIRECTION OUTPUT ;
    USE SIGNAL ;
    SHAPE ABUTMENT ;
    PORT
      LAYER M3_m ;
      RECT 0 696.535 0.07 696.605 ;
    END
  END r0_rd_out[419]
  PIN r0_rd_out[420]
    DIRECTION OUTPUT ;
    USE SIGNAL ;
    SHAPE ABUTMENT ;
    PORT
      LAYER M3_m ;
      RECT 0 697.235 0.07 697.305 ;
    END
  END r0_rd_out[420]
  PIN r0_rd_out[421]
    DIRECTION OUTPUT ;
    USE SIGNAL ;
    SHAPE ABUTMENT ;
    PORT
      LAYER M3_m ;
      RECT 0 697.935 0.07 698.005 ;
    END
  END r0_rd_out[421]
  PIN r0_rd_out[422]
    DIRECTION OUTPUT ;
    USE SIGNAL ;
    SHAPE ABUTMENT ;
    PORT
      LAYER M3_m ;
      RECT 0 698.635 0.07 698.705 ;
    END
  END r0_rd_out[422]
  PIN r0_rd_out[423]
    DIRECTION OUTPUT ;
    USE SIGNAL ;
    SHAPE ABUTMENT ;
    PORT
      LAYER M3_m ;
      RECT 0 699.335 0.07 699.405 ;
    END
  END r0_rd_out[423]
  PIN r0_rd_out[424]
    DIRECTION OUTPUT ;
    USE SIGNAL ;
    SHAPE ABUTMENT ;
    PORT
      LAYER M3_m ;
      RECT 0 700.035 0.07 700.105 ;
    END
  END r0_rd_out[424]
  PIN r0_rd_out[425]
    DIRECTION OUTPUT ;
    USE SIGNAL ;
    SHAPE ABUTMENT ;
    PORT
      LAYER M3_m ;
      RECT 0 700.735 0.07 700.805 ;
    END
  END r0_rd_out[425]
  PIN r0_rd_out[426]
    DIRECTION OUTPUT ;
    USE SIGNAL ;
    SHAPE ABUTMENT ;
    PORT
      LAYER M3_m ;
      RECT 0 701.435 0.07 701.505 ;
    END
  END r0_rd_out[426]
  PIN r0_rd_out[427]
    DIRECTION OUTPUT ;
    USE SIGNAL ;
    SHAPE ABUTMENT ;
    PORT
      LAYER M3_m ;
      RECT 0 702.135 0.07 702.205 ;
    END
  END r0_rd_out[427]
  PIN r0_rd_out[428]
    DIRECTION OUTPUT ;
    USE SIGNAL ;
    SHAPE ABUTMENT ;
    PORT
      LAYER M3_m ;
      RECT 0 702.835 0.07 702.905 ;
    END
  END r0_rd_out[428]
  PIN r0_rd_out[429]
    DIRECTION OUTPUT ;
    USE SIGNAL ;
    SHAPE ABUTMENT ;
    PORT
      LAYER M3_m ;
      RECT 0 703.535 0.07 703.605 ;
    END
  END r0_rd_out[429]
  PIN r0_rd_out[430]
    DIRECTION OUTPUT ;
    USE SIGNAL ;
    SHAPE ABUTMENT ;
    PORT
      LAYER M3_m ;
      RECT 0 704.235 0.07 704.305 ;
    END
  END r0_rd_out[430]
  PIN r0_rd_out[431]
    DIRECTION OUTPUT ;
    USE SIGNAL ;
    SHAPE ABUTMENT ;
    PORT
      LAYER M3_m ;
      RECT 0 704.935 0.07 705.005 ;
    END
  END r0_rd_out[431]
  PIN r0_rd_out[432]
    DIRECTION OUTPUT ;
    USE SIGNAL ;
    SHAPE ABUTMENT ;
    PORT
      LAYER M3_m ;
      RECT 0 705.635 0.07 705.705 ;
    END
  END r0_rd_out[432]
  PIN r0_rd_out[433]
    DIRECTION OUTPUT ;
    USE SIGNAL ;
    SHAPE ABUTMENT ;
    PORT
      LAYER M3_m ;
      RECT 0 706.335 0.07 706.405 ;
    END
  END r0_rd_out[433]
  PIN r0_rd_out[434]
    DIRECTION OUTPUT ;
    USE SIGNAL ;
    SHAPE ABUTMENT ;
    PORT
      LAYER M3_m ;
      RECT 0 707.035 0.07 707.105 ;
    END
  END r0_rd_out[434]
  PIN r0_rd_out[435]
    DIRECTION OUTPUT ;
    USE SIGNAL ;
    SHAPE ABUTMENT ;
    PORT
      LAYER M3_m ;
      RECT 0 707.735 0.07 707.805 ;
    END
  END r0_rd_out[435]
  PIN r0_rd_out[436]
    DIRECTION OUTPUT ;
    USE SIGNAL ;
    SHAPE ABUTMENT ;
    PORT
      LAYER M3_m ;
      RECT 0 708.435 0.07 708.505 ;
    END
  END r0_rd_out[436]
  PIN r0_rd_out[437]
    DIRECTION OUTPUT ;
    USE SIGNAL ;
    SHAPE ABUTMENT ;
    PORT
      LAYER M3_m ;
      RECT 0 709.135 0.07 709.205 ;
    END
  END r0_rd_out[437]
  PIN r0_rd_out[438]
    DIRECTION OUTPUT ;
    USE SIGNAL ;
    SHAPE ABUTMENT ;
    PORT
      LAYER M3_m ;
      RECT 0 709.835 0.07 709.905 ;
    END
  END r0_rd_out[438]
  PIN r0_rd_out[439]
    DIRECTION OUTPUT ;
    USE SIGNAL ;
    SHAPE ABUTMENT ;
    PORT
      LAYER M3_m ;
      RECT 0 710.535 0.07 710.605 ;
    END
  END r0_rd_out[439]
  PIN r0_rd_out[440]
    DIRECTION OUTPUT ;
    USE SIGNAL ;
    SHAPE ABUTMENT ;
    PORT
      LAYER M3_m ;
      RECT 0 711.235 0.07 711.305 ;
    END
  END r0_rd_out[440]
  PIN r0_rd_out[441]
    DIRECTION OUTPUT ;
    USE SIGNAL ;
    SHAPE ABUTMENT ;
    PORT
      LAYER M3_m ;
      RECT 0 711.935 0.07 712.005 ;
    END
  END r0_rd_out[441]
  PIN r0_rd_out[442]
    DIRECTION OUTPUT ;
    USE SIGNAL ;
    SHAPE ABUTMENT ;
    PORT
      LAYER M3_m ;
      RECT 0 712.635 0.07 712.705 ;
    END
  END r0_rd_out[442]
  PIN r0_rd_out[443]
    DIRECTION OUTPUT ;
    USE SIGNAL ;
    SHAPE ABUTMENT ;
    PORT
      LAYER M3_m ;
      RECT 0 713.335 0.07 713.405 ;
    END
  END r0_rd_out[443]
  PIN r0_rd_out[444]
    DIRECTION OUTPUT ;
    USE SIGNAL ;
    SHAPE ABUTMENT ;
    PORT
      LAYER M3_m ;
      RECT 0 714.035 0.07 714.105 ;
    END
  END r0_rd_out[444]
  PIN r0_rd_out[445]
    DIRECTION OUTPUT ;
    USE SIGNAL ;
    SHAPE ABUTMENT ;
    PORT
      LAYER M3_m ;
      RECT 0 714.735 0.07 714.805 ;
    END
  END r0_rd_out[445]
  PIN r0_rd_out[446]
    DIRECTION OUTPUT ;
    USE SIGNAL ;
    SHAPE ABUTMENT ;
    PORT
      LAYER M3_m ;
      RECT 0 715.435 0.07 715.505 ;
    END
  END r0_rd_out[446]
  PIN r0_rd_out[447]
    DIRECTION OUTPUT ;
    USE SIGNAL ;
    SHAPE ABUTMENT ;
    PORT
      LAYER M3_m ;
      RECT 0 716.135 0.07 716.205 ;
    END
  END r0_rd_out[447]
  PIN r0_rd_out[448]
    DIRECTION OUTPUT ;
    USE SIGNAL ;
    SHAPE ABUTMENT ;
    PORT
      LAYER M3_m ;
      RECT 0 716.835 0.07 716.905 ;
    END
  END r0_rd_out[448]
  PIN r0_rd_out[449]
    DIRECTION OUTPUT ;
    USE SIGNAL ;
    SHAPE ABUTMENT ;
    PORT
      LAYER M3_m ;
      RECT 0 717.535 0.07 717.605 ;
    END
  END r0_rd_out[449]
  PIN r0_rd_out[450]
    DIRECTION OUTPUT ;
    USE SIGNAL ;
    SHAPE ABUTMENT ;
    PORT
      LAYER M3_m ;
      RECT 0 718.235 0.07 718.305 ;
    END
  END r0_rd_out[450]
  PIN r0_rd_out[451]
    DIRECTION OUTPUT ;
    USE SIGNAL ;
    SHAPE ABUTMENT ;
    PORT
      LAYER M3_m ;
      RECT 0 718.935 0.07 719.005 ;
    END
  END r0_rd_out[451]
  PIN r0_rd_out[452]
    DIRECTION OUTPUT ;
    USE SIGNAL ;
    SHAPE ABUTMENT ;
    PORT
      LAYER M3_m ;
      RECT 0 719.635 0.07 719.705 ;
    END
  END r0_rd_out[452]
  PIN r0_rd_out[453]
    DIRECTION OUTPUT ;
    USE SIGNAL ;
    SHAPE ABUTMENT ;
    PORT
      LAYER M3_m ;
      RECT 0 720.335 0.07 720.405 ;
    END
  END r0_rd_out[453]
  PIN r0_rd_out[454]
    DIRECTION OUTPUT ;
    USE SIGNAL ;
    SHAPE ABUTMENT ;
    PORT
      LAYER M3_m ;
      RECT 0 721.035 0.07 721.105 ;
    END
  END r0_rd_out[454]
  PIN r0_rd_out[455]
    DIRECTION OUTPUT ;
    USE SIGNAL ;
    SHAPE ABUTMENT ;
    PORT
      LAYER M3_m ;
      RECT 0 721.735 0.07 721.805 ;
    END
  END r0_rd_out[455]
  PIN r0_rd_out[456]
    DIRECTION OUTPUT ;
    USE SIGNAL ;
    SHAPE ABUTMENT ;
    PORT
      LAYER M3_m ;
      RECT 0 722.435 0.07 722.505 ;
    END
  END r0_rd_out[456]
  PIN r0_rd_out[457]
    DIRECTION OUTPUT ;
    USE SIGNAL ;
    SHAPE ABUTMENT ;
    PORT
      LAYER M3_m ;
      RECT 0 723.135 0.07 723.205 ;
    END
  END r0_rd_out[457]
  PIN r0_rd_out[458]
    DIRECTION OUTPUT ;
    USE SIGNAL ;
    SHAPE ABUTMENT ;
    PORT
      LAYER M3_m ;
      RECT 0 723.835 0.07 723.905 ;
    END
  END r0_rd_out[458]
  PIN r0_rd_out[459]
    DIRECTION OUTPUT ;
    USE SIGNAL ;
    SHAPE ABUTMENT ;
    PORT
      LAYER M3_m ;
      RECT 0 724.535 0.07 724.605 ;
    END
  END r0_rd_out[459]
  PIN r0_rd_out[460]
    DIRECTION OUTPUT ;
    USE SIGNAL ;
    SHAPE ABUTMENT ;
    PORT
      LAYER M3_m ;
      RECT 0 725.235 0.07 725.305 ;
    END
  END r0_rd_out[460]
  PIN r0_rd_out[461]
    DIRECTION OUTPUT ;
    USE SIGNAL ;
    SHAPE ABUTMENT ;
    PORT
      LAYER M3_m ;
      RECT 0 725.935 0.07 726.005 ;
    END
  END r0_rd_out[461]
  PIN r0_rd_out[462]
    DIRECTION OUTPUT ;
    USE SIGNAL ;
    SHAPE ABUTMENT ;
    PORT
      LAYER M3_m ;
      RECT 0 726.635 0.07 726.705 ;
    END
  END r0_rd_out[462]
  PIN r0_rd_out[463]
    DIRECTION OUTPUT ;
    USE SIGNAL ;
    SHAPE ABUTMENT ;
    PORT
      LAYER M3_m ;
      RECT 0 727.335 0.07 727.405 ;
    END
  END r0_rd_out[463]
  PIN r0_rd_out[464]
    DIRECTION OUTPUT ;
    USE SIGNAL ;
    SHAPE ABUTMENT ;
    PORT
      LAYER M3_m ;
      RECT 0 728.035 0.07 728.105 ;
    END
  END r0_rd_out[464]
  PIN r0_rd_out[465]
    DIRECTION OUTPUT ;
    USE SIGNAL ;
    SHAPE ABUTMENT ;
    PORT
      LAYER M3_m ;
      RECT 0 728.735 0.07 728.805 ;
    END
  END r0_rd_out[465]
  PIN r0_rd_out[466]
    DIRECTION OUTPUT ;
    USE SIGNAL ;
    SHAPE ABUTMENT ;
    PORT
      LAYER M3_m ;
      RECT 0 729.435 0.07 729.505 ;
    END
  END r0_rd_out[466]
  PIN r0_rd_out[467]
    DIRECTION OUTPUT ;
    USE SIGNAL ;
    SHAPE ABUTMENT ;
    PORT
      LAYER M3_m ;
      RECT 0 730.135 0.07 730.205 ;
    END
  END r0_rd_out[467]
  PIN r0_rd_out[468]
    DIRECTION OUTPUT ;
    USE SIGNAL ;
    SHAPE ABUTMENT ;
    PORT
      LAYER M3_m ;
      RECT 0 730.835 0.07 730.905 ;
    END
  END r0_rd_out[468]
  PIN r0_rd_out[469]
    DIRECTION OUTPUT ;
    USE SIGNAL ;
    SHAPE ABUTMENT ;
    PORT
      LAYER M3_m ;
      RECT 0 731.535 0.07 731.605 ;
    END
  END r0_rd_out[469]
  PIN r0_rd_out[470]
    DIRECTION OUTPUT ;
    USE SIGNAL ;
    SHAPE ABUTMENT ;
    PORT
      LAYER M3_m ;
      RECT 0 732.235 0.07 732.305 ;
    END
  END r0_rd_out[470]
  PIN r0_rd_out[471]
    DIRECTION OUTPUT ;
    USE SIGNAL ;
    SHAPE ABUTMENT ;
    PORT
      LAYER M3_m ;
      RECT 0 732.935 0.07 733.005 ;
    END
  END r0_rd_out[471]
  PIN r0_rd_out[472]
    DIRECTION OUTPUT ;
    USE SIGNAL ;
    SHAPE ABUTMENT ;
    PORT
      LAYER M3_m ;
      RECT 0 733.635 0.07 733.705 ;
    END
  END r0_rd_out[472]
  PIN r0_rd_out[473]
    DIRECTION OUTPUT ;
    USE SIGNAL ;
    SHAPE ABUTMENT ;
    PORT
      LAYER M3_m ;
      RECT 0 734.335 0.07 734.405 ;
    END
  END r0_rd_out[473]
  PIN r0_rd_out[474]
    DIRECTION OUTPUT ;
    USE SIGNAL ;
    SHAPE ABUTMENT ;
    PORT
      LAYER M3_m ;
      RECT 0 735.035 0.07 735.105 ;
    END
  END r0_rd_out[474]
  PIN r0_rd_out[475]
    DIRECTION OUTPUT ;
    USE SIGNAL ;
    SHAPE ABUTMENT ;
    PORT
      LAYER M3_m ;
      RECT 0 735.735 0.07 735.805 ;
    END
  END r0_rd_out[475]
  PIN r0_rd_out[476]
    DIRECTION OUTPUT ;
    USE SIGNAL ;
    SHAPE ABUTMENT ;
    PORT
      LAYER M3_m ;
      RECT 0 736.435 0.07 736.505 ;
    END
  END r0_rd_out[476]
  PIN r0_rd_out[477]
    DIRECTION OUTPUT ;
    USE SIGNAL ;
    SHAPE ABUTMENT ;
    PORT
      LAYER M3_m ;
      RECT 0 737.135 0.07 737.205 ;
    END
  END r0_rd_out[477]
  PIN r0_rd_out[478]
    DIRECTION OUTPUT ;
    USE SIGNAL ;
    SHAPE ABUTMENT ;
    PORT
      LAYER M3_m ;
      RECT 0 737.835 0.07 737.905 ;
    END
  END r0_rd_out[478]
  PIN r0_rd_out[479]
    DIRECTION OUTPUT ;
    USE SIGNAL ;
    SHAPE ABUTMENT ;
    PORT
      LAYER M3_m ;
      RECT 0 738.535 0.07 738.605 ;
    END
  END r0_rd_out[479]
  PIN r0_rd_out[480]
    DIRECTION OUTPUT ;
    USE SIGNAL ;
    SHAPE ABUTMENT ;
    PORT
      LAYER M3_m ;
      RECT 0 739.235 0.07 739.305 ;
    END
  END r0_rd_out[480]
  PIN r0_rd_out[481]
    DIRECTION OUTPUT ;
    USE SIGNAL ;
    SHAPE ABUTMENT ;
    PORT
      LAYER M3_m ;
      RECT 0 739.935 0.07 740.005 ;
    END
  END r0_rd_out[481]
  PIN r0_rd_out[482]
    DIRECTION OUTPUT ;
    USE SIGNAL ;
    SHAPE ABUTMENT ;
    PORT
      LAYER M3_m ;
      RECT 0 740.635 0.07 740.705 ;
    END
  END r0_rd_out[482]
  PIN r0_rd_out[483]
    DIRECTION OUTPUT ;
    USE SIGNAL ;
    SHAPE ABUTMENT ;
    PORT
      LAYER M3_m ;
      RECT 0 741.335 0.07 741.405 ;
    END
  END r0_rd_out[483]
  PIN r0_rd_out[484]
    DIRECTION OUTPUT ;
    USE SIGNAL ;
    SHAPE ABUTMENT ;
    PORT
      LAYER M3_m ;
      RECT 0 742.035 0.07 742.105 ;
    END
  END r0_rd_out[484]
  PIN r0_rd_out[485]
    DIRECTION OUTPUT ;
    USE SIGNAL ;
    SHAPE ABUTMENT ;
    PORT
      LAYER M3_m ;
      RECT 0 742.735 0.07 742.805 ;
    END
  END r0_rd_out[485]
  PIN r0_rd_out[486]
    DIRECTION OUTPUT ;
    USE SIGNAL ;
    SHAPE ABUTMENT ;
    PORT
      LAYER M3_m ;
      RECT 0 743.435 0.07 743.505 ;
    END
  END r0_rd_out[486]
  PIN r0_rd_out[487]
    DIRECTION OUTPUT ;
    USE SIGNAL ;
    SHAPE ABUTMENT ;
    PORT
      LAYER M3_m ;
      RECT 0 744.135 0.07 744.205 ;
    END
  END r0_rd_out[487]
  PIN r0_rd_out[488]
    DIRECTION OUTPUT ;
    USE SIGNAL ;
    SHAPE ABUTMENT ;
    PORT
      LAYER M3_m ;
      RECT 0 744.835 0.07 744.905 ;
    END
  END r0_rd_out[488]
  PIN r0_rd_out[489]
    DIRECTION OUTPUT ;
    USE SIGNAL ;
    SHAPE ABUTMENT ;
    PORT
      LAYER M3_m ;
      RECT 0 745.535 0.07 745.605 ;
    END
  END r0_rd_out[489]
  PIN r0_rd_out[490]
    DIRECTION OUTPUT ;
    USE SIGNAL ;
    SHAPE ABUTMENT ;
    PORT
      LAYER M3_m ;
      RECT 0 746.235 0.07 746.305 ;
    END
  END r0_rd_out[490]
  PIN r0_rd_out[491]
    DIRECTION OUTPUT ;
    USE SIGNAL ;
    SHAPE ABUTMENT ;
    PORT
      LAYER M3_m ;
      RECT 0 746.935 0.07 747.005 ;
    END
  END r0_rd_out[491]
  PIN r0_rd_out[492]
    DIRECTION OUTPUT ;
    USE SIGNAL ;
    SHAPE ABUTMENT ;
    PORT
      LAYER M3_m ;
      RECT 0 747.635 0.07 747.705 ;
    END
  END r0_rd_out[492]
  PIN r0_rd_out[493]
    DIRECTION OUTPUT ;
    USE SIGNAL ;
    SHAPE ABUTMENT ;
    PORT
      LAYER M3_m ;
      RECT 0 748.335 0.07 748.405 ;
    END
  END r0_rd_out[493]
  PIN r0_rd_out[494]
    DIRECTION OUTPUT ;
    USE SIGNAL ;
    SHAPE ABUTMENT ;
    PORT
      LAYER M3_m ;
      RECT 0 749.035 0.07 749.105 ;
    END
  END r0_rd_out[494]
  PIN r0_rd_out[495]
    DIRECTION OUTPUT ;
    USE SIGNAL ;
    SHAPE ABUTMENT ;
    PORT
      LAYER M3_m ;
      RECT 0 749.735 0.07 749.805 ;
    END
  END r0_rd_out[495]
  PIN r0_rd_out[496]
    DIRECTION OUTPUT ;
    USE SIGNAL ;
    SHAPE ABUTMENT ;
    PORT
      LAYER M3_m ;
      RECT 0 750.435 0.07 750.505 ;
    END
  END r0_rd_out[496]
  PIN r0_rd_out[497]
    DIRECTION OUTPUT ;
    USE SIGNAL ;
    SHAPE ABUTMENT ;
    PORT
      LAYER M3_m ;
      RECT 0 751.135 0.07 751.205 ;
    END
  END r0_rd_out[497]
  PIN r0_rd_out[498]
    DIRECTION OUTPUT ;
    USE SIGNAL ;
    SHAPE ABUTMENT ;
    PORT
      LAYER M3_m ;
      RECT 0 751.835 0.07 751.905 ;
    END
  END r0_rd_out[498]
  PIN r0_rd_out[499]
    DIRECTION OUTPUT ;
    USE SIGNAL ;
    SHAPE ABUTMENT ;
    PORT
      LAYER M3_m ;
      RECT 0 752.535 0.07 752.605 ;
    END
  END r0_rd_out[499]
  PIN r0_rd_out[500]
    DIRECTION OUTPUT ;
    USE SIGNAL ;
    SHAPE ABUTMENT ;
    PORT
      LAYER M3_m ;
      RECT 0 753.235 0.07 753.305 ;
    END
  END r0_rd_out[500]
  PIN r0_rd_out[501]
    DIRECTION OUTPUT ;
    USE SIGNAL ;
    SHAPE ABUTMENT ;
    PORT
      LAYER M3_m ;
      RECT 0 753.935 0.07 754.005 ;
    END
  END r0_rd_out[501]
  PIN r0_rd_out[502]
    DIRECTION OUTPUT ;
    USE SIGNAL ;
    SHAPE ABUTMENT ;
    PORT
      LAYER M3_m ;
      RECT 0 754.635 0.07 754.705 ;
    END
  END r0_rd_out[502]
  PIN r0_rd_out[503]
    DIRECTION OUTPUT ;
    USE SIGNAL ;
    SHAPE ABUTMENT ;
    PORT
      LAYER M3_m ;
      RECT 0 755.335 0.07 755.405 ;
    END
  END r0_rd_out[503]
  PIN r0_rd_out[504]
    DIRECTION OUTPUT ;
    USE SIGNAL ;
    SHAPE ABUTMENT ;
    PORT
      LAYER M3_m ;
      RECT 0 756.035 0.07 756.105 ;
    END
  END r0_rd_out[504]
  PIN r0_rd_out[505]
    DIRECTION OUTPUT ;
    USE SIGNAL ;
    SHAPE ABUTMENT ;
    PORT
      LAYER M3_m ;
      RECT 0 756.735 0.07 756.805 ;
    END
  END r0_rd_out[505]
  PIN r0_rd_out[506]
    DIRECTION OUTPUT ;
    USE SIGNAL ;
    SHAPE ABUTMENT ;
    PORT
      LAYER M3_m ;
      RECT 0 757.435 0.07 757.505 ;
    END
  END r0_rd_out[506]
  PIN r0_rd_out[507]
    DIRECTION OUTPUT ;
    USE SIGNAL ;
    SHAPE ABUTMENT ;
    PORT
      LAYER M3_m ;
      RECT 0 758.135 0.07 758.205 ;
    END
  END r0_rd_out[507]
  PIN r0_rd_out[508]
    DIRECTION OUTPUT ;
    USE SIGNAL ;
    SHAPE ABUTMENT ;
    PORT
      LAYER M3_m ;
      RECT 0 758.835 0.07 758.905 ;
    END
  END r0_rd_out[508]
  PIN r0_rd_out[509]
    DIRECTION OUTPUT ;
    USE SIGNAL ;
    SHAPE ABUTMENT ;
    PORT
      LAYER M3_m ;
      RECT 0 759.535 0.07 759.605 ;
    END
  END r0_rd_out[509]
  PIN r0_rd_out[510]
    DIRECTION OUTPUT ;
    USE SIGNAL ;
    SHAPE ABUTMENT ;
    PORT
      LAYER M3_m ;
      RECT 0 760.235 0.07 760.305 ;
    END
  END r0_rd_out[510]
  PIN r0_rd_out[511]
    DIRECTION OUTPUT ;
    USE SIGNAL ;
    SHAPE ABUTMENT ;
    PORT
      LAYER M3_m ;
      RECT 0 760.935 0.07 761.005 ;
    END
  END r0_rd_out[511]
  PIN w0_addr_in[0]
    DIRECTION INPUT ;
    USE SIGNAL ;
    SHAPE ABUTMENT ;
    PORT
      LAYER M3_m ;
      RECT 0 761.635 0.07 761.705 ;
    END
  END w0_addr_in[0]
  PIN w0_addr_in[1]
    DIRECTION INPUT ;
    USE SIGNAL ;
    SHAPE ABUTMENT ;
    PORT
      LAYER M3_m ;
      RECT 0 762.335 0.07 762.405 ;
    END
  END w0_addr_in[1]
  PIN w0_addr_in[2]
    DIRECTION INPUT ;
    USE SIGNAL ;
    SHAPE ABUTMENT ;
    PORT
      LAYER M3_m ;
      RECT 0 763.035 0.07 763.105 ;
    END
  END w0_addr_in[2]
  PIN w0_addr_in[3]
    DIRECTION INPUT ;
    USE SIGNAL ;
    SHAPE ABUTMENT ;
    PORT
      LAYER M3_m ;
      RECT 0 763.735 0.07 763.805 ;
    END
  END w0_addr_in[3]
  PIN w0_addr_in[4]
    DIRECTION INPUT ;
    USE SIGNAL ;
    SHAPE ABUTMENT ;
    PORT
      LAYER M3_m ;
      RECT 0 764.435 0.07 764.505 ;
    END
  END w0_addr_in[4]
  PIN w0_addr_in[5]
    DIRECTION INPUT ;
    USE SIGNAL ;
    SHAPE ABUTMENT ;
    PORT
      LAYER M3_m ;
      RECT 0 765.135 0.07 765.205 ;
    END
  END w0_addr_in[5]
  PIN w0_addr_in[6]
    DIRECTION INPUT ;
    USE SIGNAL ;
    SHAPE ABUTMENT ;
    PORT
      LAYER M3_m ;
      RECT 0 765.835 0.07 765.905 ;
    END
  END w0_addr_in[6]
  PIN w0_addr_in[7]
    DIRECTION INPUT ;
    USE SIGNAL ;
    SHAPE ABUTMENT ;
    PORT
      LAYER M3_m ;
      RECT 0 766.535 0.07 766.605 ;
    END
  END w0_addr_in[7]
  PIN w0_addr_in[8]
    DIRECTION INPUT ;
    USE SIGNAL ;
    SHAPE ABUTMENT ;
    PORT
      LAYER M3_m ;
      RECT 0 767.235 0.07 767.305 ;
    END
  END w0_addr_in[8]
  PIN r0_addr_in[0]
    DIRECTION INPUT ;
    USE SIGNAL ;
    SHAPE ABUTMENT ;
    PORT
      LAYER M3_m ;
      RECT 0 767.935 0.07 768.005 ;
    END
  END r0_addr_in[0]
  PIN r0_addr_in[1]
    DIRECTION INPUT ;
    USE SIGNAL ;
    SHAPE ABUTMENT ;
    PORT
      LAYER M3_m ;
      RECT 0 768.635 0.07 768.705 ;
    END
  END r0_addr_in[1]
  PIN r0_addr_in[2]
    DIRECTION INPUT ;
    USE SIGNAL ;
    SHAPE ABUTMENT ;
    PORT
      LAYER M3_m ;
      RECT 0 769.335 0.07 769.405 ;
    END
  END r0_addr_in[2]
  PIN r0_addr_in[3]
    DIRECTION INPUT ;
    USE SIGNAL ;
    SHAPE ABUTMENT ;
    PORT
      LAYER M3_m ;
      RECT 0 770.035 0.07 770.105 ;
    END
  END r0_addr_in[3]
  PIN r0_addr_in[4]
    DIRECTION INPUT ;
    USE SIGNAL ;
    SHAPE ABUTMENT ;
    PORT
      LAYER M3_m ;
      RECT 0 770.735 0.07 770.805 ;
    END
  END r0_addr_in[4]
  PIN r0_addr_in[5]
    DIRECTION INPUT ;
    USE SIGNAL ;
    SHAPE ABUTMENT ;
    PORT
      LAYER M3_m ;
      RECT 0 771.435 0.07 771.505 ;
    END
  END r0_addr_in[5]
  PIN r0_addr_in[6]
    DIRECTION INPUT ;
    USE SIGNAL ;
    SHAPE ABUTMENT ;
    PORT
      LAYER M3_m ;
      RECT 0 772.135 0.07 772.205 ;
    END
  END r0_addr_in[6]
  PIN r0_addr_in[7]
    DIRECTION INPUT ;
    USE SIGNAL ;
    SHAPE ABUTMENT ;
    PORT
      LAYER M3_m ;
      RECT 0 772.835 0.07 772.905 ;
    END
  END r0_addr_in[7]
  PIN r0_addr_in[8]
    DIRECTION INPUT ;
    USE SIGNAL ;
    SHAPE ABUTMENT ;
    PORT
      LAYER M3_m ;
      RECT 0 773.535 0.07 773.605 ;
    END
  END r0_addr_in[8]
  PIN w0_we_in
    DIRECTION INPUT ;
    USE SIGNAL ;
    SHAPE ABUTMENT ;
    PORT
      LAYER M3_m ;
      RECT 0 774.235 0.07 774.305 ;
    END
  END w0_we_in
  PIN w0_ce_in
    DIRECTION INPUT ;
    USE SIGNAL ;
    SHAPE ABUTMENT ;
    PORT
      LAYER M3_m ;
      RECT 0 774.935 0.07 775.005 ;
    END
  END w0_ce_in
  PIN w0_clk
    DIRECTION INPUT ;
    USE SIGNAL ;
    SHAPE ABUTMENT ;
    PORT
      LAYER M3_m ;
      RECT 0 775.635 0.07 775.705 ;
    END
  END w0_clk
  PIN r0_ce_in
    DIRECTION INPUT ;
    USE SIGNAL ;
    SHAPE ABUTMENT ;
    PORT
      LAYER M3_m ;
      RECT 0 776.335 0.07 776.405 ;
    END
  END r0_ce_in
  PIN r0_clk
    DIRECTION INPUT ;
    USE SIGNAL ;
    SHAPE ABUTMENT ;
    PORT
      LAYER M3_m ;
      RECT 0 777.035 0.07 777.105 ;
    END
  END r0_clk
  PIN VSS
    DIRECTION INOUT ;
    USE GROUND ;
    PORT
      LAYER M4_m ;
      RECT 1 0.84 1.28 783.16 ;
      RECT 3.24 0.84 3.52 783.16 ;
      RECT 5.48 0.84 5.76 783.16 ;
      RECT 7.72 0.84 8 783.16 ;
      RECT 9.96 0.84 10.24 783.16 ;
      RECT 12.2 0.84 12.48 783.16 ;
      RECT 14.44 0.84 14.72 783.16 ;
      RECT 16.68 0.84 16.96 783.16 ;
      RECT 18.92 0.84 19.2 783.16 ;
      RECT 21.16 0.84 21.44 783.16 ;
      RECT 23.4 0.84 23.68 783.16 ;
      RECT 25.64 0.84 25.92 783.16 ;
      RECT 27.88 0.84 28.16 783.16 ;
      RECT 30.12 0.84 30.4 783.16 ;
      RECT 32.36 0.84 32.64 783.16 ;
      RECT 34.6 0.84 34.88 783.16 ;
      RECT 36.84 0.84 37.12 783.16 ;
      RECT 39.08 0.84 39.36 783.16 ;
      RECT 41.32 0.84 41.6 783.16 ;
      RECT 43.56 0.84 43.84 783.16 ;
      RECT 45.8 0.84 46.08 783.16 ;
      RECT 48.04 0.84 48.32 783.16 ;
      RECT 50.28 0.84 50.56 783.16 ;
      RECT 52.52 0.84 52.8 783.16 ;
      RECT 54.76 0.84 55.04 783.16 ;
      RECT 57 0.84 57.28 783.16 ;
      RECT 59.24 0.84 59.52 783.16 ;
      RECT 61.48 0.84 61.76 783.16 ;
      RECT 63.72 0.84 64 783.16 ;
      RECT 65.96 0.84 66.24 783.16 ;
      RECT 68.2 0.84 68.48 783.16 ;
      RECT 70.44 0.84 70.72 783.16 ;
      RECT 72.68 0.84 72.96 783.16 ;
      RECT 74.92 0.84 75.2 783.16 ;
      RECT 77.16 0.84 77.44 783.16 ;
      RECT 79.4 0.84 79.68 783.16 ;
      RECT 81.64 0.84 81.92 783.16 ;
      RECT 83.88 0.84 84.16 783.16 ;
      RECT 86.12 0.84 86.4 783.16 ;
      RECT 88.36 0.84 88.64 783.16 ;
      RECT 90.6 0.84 90.88 783.16 ;
      RECT 92.84 0.84 93.12 783.16 ;
      RECT 95.08 0.84 95.36 783.16 ;
      RECT 97.32 0.84 97.6 783.16 ;
      RECT 99.56 0.84 99.84 783.16 ;
      RECT 101.8 0.84 102.08 783.16 ;
      RECT 104.04 0.84 104.32 783.16 ;
      RECT 106.28 0.84 106.56 783.16 ;
      RECT 108.52 0.84 108.8 783.16 ;
      RECT 110.76 0.84 111.04 783.16 ;
      RECT 113 0.84 113.28 783.16 ;
      RECT 115.24 0.84 115.52 783.16 ;
      RECT 117.48 0.84 117.76 783.16 ;
      RECT 119.72 0.84 120 783.16 ;
      RECT 121.96 0.84 122.24 783.16 ;
      RECT 124.2 0.84 124.48 783.16 ;
      RECT 126.44 0.84 126.72 783.16 ;
      RECT 128.68 0.84 128.96 783.16 ;
      RECT 130.92 0.84 131.2 783.16 ;
      RECT 133.16 0.84 133.44 783.16 ;
      RECT 135.4 0.84 135.68 783.16 ;
      RECT 137.64 0.84 137.92 783.16 ;
      RECT 139.88 0.84 140.16 783.16 ;
      RECT 142.12 0.84 142.4 783.16 ;
      RECT 144.36 0.84 144.64 783.16 ;
      RECT 146.6 0.84 146.88 783.16 ;
      RECT 148.84 0.84 149.12 783.16 ;
      RECT 151.08 0.84 151.36 783.16 ;
      RECT 153.32 0.84 153.6 783.16 ;
      RECT 155.56 0.84 155.84 783.16 ;
      RECT 157.8 0.84 158.08 783.16 ;
      RECT 160.04 0.84 160.32 783.16 ;
      RECT 162.28 0.84 162.56 783.16 ;
      RECT 164.52 0.84 164.8 783.16 ;
      RECT 166.76 0.84 167.04 783.16 ;
      RECT 169 0.84 169.28 783.16 ;
      RECT 171.24 0.84 171.52 783.16 ;
      RECT 173.48 0.84 173.76 783.16 ;
      RECT 175.72 0.84 176 783.16 ;
      RECT 177.96 0.84 178.24 783.16 ;
      RECT 180.2 0.84 180.48 783.16 ;
      RECT 182.44 0.84 182.72 783.16 ;
      RECT 184.68 0.84 184.96 783.16 ;
      RECT 186.92 0.84 187.2 783.16 ;
      RECT 189.16 0.84 189.44 783.16 ;
      RECT 191.4 0.84 191.68 783.16 ;
      RECT 193.64 0.84 193.92 783.16 ;
      RECT 195.88 0.84 196.16 783.16 ;
      RECT 198.12 0.84 198.4 783.16 ;
      RECT 200.36 0.84 200.64 783.16 ;
      RECT 202.6 0.84 202.88 783.16 ;
      RECT 204.84 0.84 205.12 783.16 ;
      RECT 207.08 0.84 207.36 783.16 ;
      RECT 209.32 0.84 209.6 783.16 ;
      RECT 211.56 0.84 211.84 783.16 ;
      RECT 213.8 0.84 214.08 783.16 ;
      RECT 216.04 0.84 216.32 783.16 ;
      RECT 218.28 0.84 218.56 783.16 ;
      RECT 220.52 0.84 220.8 783.16 ;
      RECT 222.76 0.84 223.04 783.16 ;
      RECT 225 0.84 225.28 783.16 ;
      RECT 227.24 0.84 227.52 783.16 ;
      RECT 229.48 0.84 229.76 783.16 ;
      RECT 231.72 0.84 232 783.16 ;
      RECT 233.96 0.84 234.24 783.16 ;
      RECT 236.2 0.84 236.48 783.16 ;
      RECT 238.44 0.84 238.72 783.16 ;
      RECT 240.68 0.84 240.96 783.16 ;
      RECT 242.92 0.84 243.2 783.16 ;
      RECT 245.16 0.84 245.44 783.16 ;
      RECT 247.4 0.84 247.68 783.16 ;
      RECT 249.64 0.84 249.92 783.16 ;
      RECT 251.88 0.84 252.16 783.16 ;
      RECT 254.12 0.84 254.4 783.16 ;
      RECT 256.36 0.84 256.64 783.16 ;
      RECT 258.6 0.84 258.88 783.16 ;
      RECT 260.84 0.84 261.12 783.16 ;
      RECT 263.08 0.84 263.36 783.16 ;
      RECT 265.32 0.84 265.6 783.16 ;
      RECT 267.56 0.84 267.84 783.16 ;
      RECT 269.8 0.84 270.08 783.16 ;
      RECT 272.04 0.84 272.32 783.16 ;
      RECT 274.28 0.84 274.56 783.16 ;
      RECT 276.52 0.84 276.8 783.16 ;
      RECT 278.76 0.84 279.04 783.16 ;
      RECT 281 0.84 281.28 783.16 ;
      RECT 283.24 0.84 283.52 783.16 ;
      RECT 285.48 0.84 285.76 783.16 ;
      RECT 287.72 0.84 288 783.16 ;
      RECT 289.96 0.84 290.24 783.16 ;
      RECT 292.2 0.84 292.48 783.16 ;
      RECT 294.44 0.84 294.72 783.16 ;
      RECT 296.68 0.84 296.96 783.16 ;
      RECT 298.92 0.84 299.2 783.16 ;
      RECT 301.16 0.84 301.44 783.16 ;
      RECT 303.4 0.84 303.68 783.16 ;
      RECT 305.64 0.84 305.92 783.16 ;
      RECT 307.88 0.84 308.16 783.16 ;
      RECT 310.12 0.84 310.4 783.16 ;
      RECT 312.36 0.84 312.64 783.16 ;
      RECT 314.6 0.84 314.88 783.16 ;
      RECT 316.84 0.84 317.12 783.16 ;
      RECT 319.08 0.84 319.36 783.16 ;
      RECT 321.32 0.84 321.6 783.16 ;
      RECT 323.56 0.84 323.84 783.16 ;
      RECT 325.8 0.84 326.08 783.16 ;
      RECT 328.04 0.84 328.32 783.16 ;
      RECT 330.28 0.84 330.56 783.16 ;
      RECT 332.52 0.84 332.8 783.16 ;
      RECT 334.76 0.84 335.04 783.16 ;
      RECT 337 0.84 337.28 783.16 ;
      RECT 339.24 0.84 339.52 783.16 ;
      RECT 341.48 0.84 341.76 783.16 ;
      RECT 343.72 0.84 344 783.16 ;
      RECT 345.96 0.84 346.24 783.16 ;
      RECT 348.2 0.84 348.48 783.16 ;
      RECT 350.44 0.84 350.72 783.16 ;
      RECT 352.68 0.84 352.96 783.16 ;
      RECT 354.92 0.84 355.2 783.16 ;
      RECT 357.16 0.84 357.44 783.16 ;
      RECT 359.4 0.84 359.68 783.16 ;
      RECT 361.64 0.84 361.92 783.16 ;
      RECT 363.88 0.84 364.16 783.16 ;
      RECT 366.12 0.84 366.4 783.16 ;
      RECT 368.36 0.84 368.64 783.16 ;
      RECT 370.6 0.84 370.88 783.16 ;
      RECT 372.84 0.84 373.12 783.16 ;
      RECT 375.08 0.84 375.36 783.16 ;
      RECT 377.32 0.84 377.6 783.16 ;
      RECT 379.56 0.84 379.84 783.16 ;
      RECT 381.8 0.84 382.08 783.16 ;
      RECT 384.04 0.84 384.32 783.16 ;
      RECT 386.28 0.84 386.56 783.16 ;
      RECT 388.52 0.84 388.8 783.16 ;
      RECT 390.76 0.84 391.04 783.16 ;
      RECT 393 0.84 393.28 783.16 ;
      RECT 395.24 0.84 395.52 783.16 ;
      RECT 397.48 0.84 397.76 783.16 ;
      RECT 399.72 0.84 400 783.16 ;
      RECT 401.96 0.84 402.24 783.16 ;
      RECT 404.2 0.84 404.48 783.16 ;
      RECT 406.44 0.84 406.72 783.16 ;
      RECT 408.68 0.84 408.96 783.16 ;
      RECT 410.92 0.84 411.2 783.16 ;
      RECT 413.16 0.84 413.44 783.16 ;
      RECT 415.4 0.84 415.68 783.16 ;
      RECT 417.64 0.84 417.92 783.16 ;
      RECT 419.88 0.84 420.16 783.16 ;
      RECT 422.12 0.84 422.4 783.16 ;
      RECT 424.36 0.84 424.64 783.16 ;
      RECT 426.6 0.84 426.88 783.16 ;
      RECT 428.84 0.84 429.12 783.16 ;
      RECT 431.08 0.84 431.36 783.16 ;
      RECT 433.32 0.84 433.6 783.16 ;
      RECT 435.56 0.84 435.84 783.16 ;
      RECT 437.8 0.84 438.08 783.16 ;
      RECT 440.04 0.84 440.32 783.16 ;
      RECT 442.28 0.84 442.56 783.16 ;
      RECT 444.52 0.84 444.8 783.16 ;
      RECT 446.76 0.84 447.04 783.16 ;
      RECT 449 0.84 449.28 783.16 ;
      RECT 451.24 0.84 451.52 783.16 ;
      RECT 453.48 0.84 453.76 783.16 ;
      RECT 455.72 0.84 456 783.16 ;
      RECT 457.96 0.84 458.24 783.16 ;
      RECT 460.2 0.84 460.48 783.16 ;
      RECT 462.44 0.84 462.72 783.16 ;
      RECT 464.68 0.84 464.96 783.16 ;
      RECT 466.92 0.84 467.2 783.16 ;
      RECT 469.16 0.84 469.44 783.16 ;
      RECT 471.4 0.84 471.68 783.16 ;
      RECT 473.64 0.84 473.92 783.16 ;
      RECT 475.88 0.84 476.16 783.16 ;
      RECT 478.12 0.84 478.4 783.16 ;
      RECT 480.36 0.84 480.64 783.16 ;
      RECT 482.6 0.84 482.88 783.16 ;
      RECT 484.84 0.84 485.12 783.16 ;
      RECT 487.08 0.84 487.36 783.16 ;
      RECT 489.32 0.84 489.6 783.16 ;
      RECT 491.56 0.84 491.84 783.16 ;
      RECT 493.8 0.84 494.08 783.16 ;
      RECT 496.04 0.84 496.32 783.16 ;
      RECT 498.28 0.84 498.56 783.16 ;
      RECT 500.52 0.84 500.8 783.16 ;
      RECT 502.76 0.84 503.04 783.16 ;
      RECT 505 0.84 505.28 783.16 ;
      RECT 507.24 0.84 507.52 783.16 ;
      RECT 509.48 0.84 509.76 783.16 ;
      RECT 511.72 0.84 512 783.16 ;
      RECT 513.96 0.84 514.24 783.16 ;
      RECT 516.2 0.84 516.48 783.16 ;
      RECT 518.44 0.84 518.72 783.16 ;
      RECT 520.68 0.84 520.96 783.16 ;
      RECT 522.92 0.84 523.2 783.16 ;
      RECT 525.16 0.84 525.44 783.16 ;
      RECT 527.4 0.84 527.68 783.16 ;
      RECT 529.64 0.84 529.92 783.16 ;
      RECT 531.88 0.84 532.16 783.16 ;
      RECT 534.12 0.84 534.4 783.16 ;
      RECT 536.36 0.84 536.64 783.16 ;
      RECT 538.6 0.84 538.88 783.16 ;
      RECT 540.84 0.84 541.12 783.16 ;
      RECT 543.08 0.84 543.36 783.16 ;
      RECT 545.32 0.84 545.6 783.16 ;
      RECT 547.56 0.84 547.84 783.16 ;
      RECT 549.8 0.84 550.08 783.16 ;
      RECT 552.04 0.84 552.32 783.16 ;
      RECT 554.28 0.84 554.56 783.16 ;
      RECT 556.52 0.84 556.8 783.16 ;
      RECT 558.76 0.84 559.04 783.16 ;
      RECT 561 0.84 561.28 783.16 ;
      RECT 563.24 0.84 563.52 783.16 ;
      RECT 565.48 0.84 565.76 783.16 ;
      RECT 567.72 0.84 568 783.16 ;
      RECT 569.96 0.84 570.24 783.16 ;
      RECT 572.2 0.84 572.48 783.16 ;
      RECT 574.44 0.84 574.72 783.16 ;
      RECT 576.68 0.84 576.96 783.16 ;
      RECT 578.92 0.84 579.2 783.16 ;
      RECT 581.16 0.84 581.44 783.16 ;
      RECT 583.4 0.84 583.68 783.16 ;
      RECT 585.64 0.84 585.92 783.16 ;
      RECT 587.88 0.84 588.16 783.16 ;
      RECT 590.12 0.84 590.4 783.16 ;
      RECT 592.36 0.84 592.64 783.16 ;
      RECT 594.6 0.84 594.88 783.16 ;
      RECT 596.84 0.84 597.12 783.16 ;
      RECT 599.08 0.84 599.36 783.16 ;
      RECT 601.32 0.84 601.6 783.16 ;
      RECT 603.56 0.84 603.84 783.16 ;
      RECT 605.8 0.84 606.08 783.16 ;
      RECT 608.04 0.84 608.32 783.16 ;
      RECT 610.28 0.84 610.56 783.16 ;
      RECT 612.52 0.84 612.8 783.16 ;
      RECT 614.76 0.84 615.04 783.16 ;
      RECT 617 0.84 617.28 783.16 ;
      RECT 619.24 0.84 619.52 783.16 ;
      RECT 621.48 0.84 621.76 783.16 ;
      RECT 623.72 0.84 624 783.16 ;
      RECT 625.96 0.84 626.24 783.16 ;
      RECT 628.2 0.84 628.48 783.16 ;
      RECT 630.44 0.84 630.72 783.16 ;
      RECT 632.68 0.84 632.96 783.16 ;
      RECT 634.92 0.84 635.2 783.16 ;
      RECT 637.16 0.84 637.44 783.16 ;
      RECT 639.4 0.84 639.68 783.16 ;
      RECT 641.64 0.84 641.92 783.16 ;
      RECT 643.88 0.84 644.16 783.16 ;
      RECT 646.12 0.84 646.4 783.16 ;
      RECT 648.36 0.84 648.64 783.16 ;
      RECT 650.6 0.84 650.88 783.16 ;
      RECT 652.84 0.84 653.12 783.16 ;
      RECT 655.08 0.84 655.36 783.16 ;
      RECT 657.32 0.84 657.6 783.16 ;
      RECT 659.56 0.84 659.84 783.16 ;
      RECT 661.8 0.84 662.08 783.16 ;
      RECT 664.04 0.84 664.32 783.16 ;
      RECT 666.28 0.84 666.56 783.16 ;
      RECT 668.52 0.84 668.8 783.16 ;
      RECT 670.76 0.84 671.04 783.16 ;
      RECT 673 0.84 673.28 783.16 ;
      RECT 675.24 0.84 675.52 783.16 ;
      RECT 677.48 0.84 677.76 783.16 ;
      RECT 679.72 0.84 680 783.16 ;
      RECT 681.96 0.84 682.24 783.16 ;
      RECT 684.2 0.84 684.48 783.16 ;
      RECT 686.44 0.84 686.72 783.16 ;
      RECT 688.68 0.84 688.96 783.16 ;
      RECT 690.92 0.84 691.2 783.16 ;
      RECT 693.16 0.84 693.44 783.16 ;
      RECT 695.4 0.84 695.68 783.16 ;
      RECT 697.64 0.84 697.92 783.16 ;
      RECT 699.88 0.84 700.16 783.16 ;
      RECT 702.12 0.84 702.4 783.16 ;
      RECT 704.36 0.84 704.64 783.16 ;
      RECT 706.6 0.84 706.88 783.16 ;
      RECT 708.84 0.84 709.12 783.16 ;
      RECT 711.08 0.84 711.36 783.16 ;
      RECT 713.32 0.84 713.6 783.16 ;
      RECT 715.56 0.84 715.84 783.16 ;
      RECT 717.8 0.84 718.08 783.16 ;
      RECT 720.04 0.84 720.32 783.16 ;
      RECT 722.28 0.84 722.56 783.16 ;
      RECT 724.52 0.84 724.8 783.16 ;
      RECT 726.76 0.84 727.04 783.16 ;
      RECT 729 0.84 729.28 783.16 ;
      RECT 731.24 0.84 731.52 783.16 ;
      RECT 733.48 0.84 733.76 783.16 ;
      RECT 735.72 0.84 736 783.16 ;
      RECT 737.96 0.84 738.24 783.16 ;
      RECT 740.2 0.84 740.48 783.16 ;
      RECT 742.44 0.84 742.72 783.16 ;
      RECT 744.68 0.84 744.96 783.16 ;
      RECT 746.92 0.84 747.2 783.16 ;
      RECT 749.16 0.84 749.44 783.16 ;
      RECT 751.4 0.84 751.68 783.16 ;
      RECT 753.64 0.84 753.92 783.16 ;
      RECT 755.88 0.84 756.16 783.16 ;
      RECT 758.12 0.84 758.4 783.16 ;
      RECT 760.36 0.84 760.64 783.16 ;
      RECT 762.6 0.84 762.88 783.16 ;
      RECT 764.84 0.84 765.12 783.16 ;
      RECT 767.08 0.84 767.36 783.16 ;
      RECT 769.32 0.84 769.6 783.16 ;
      RECT 771.56 0.84 771.84 783.16 ;
      RECT 773.8 0.84 774.08 783.16 ;
      RECT 776.04 0.84 776.32 783.16 ;
      RECT 778.28 0.84 778.56 783.16 ;
      RECT 780.52 0.84 780.8 783.16 ;
      RECT 782.76 0.84 783.04 783.16 ;
      RECT 785 0.84 785.28 783.16 ;
      RECT 787.24 0.84 787.52 783.16 ;
      RECT 789.48 0.84 789.76 783.16 ;
      RECT 791.72 0.84 792 783.16 ;
      RECT 793.96 0.84 794.24 783.16 ;
      RECT 796.2 0.84 796.48 783.16 ;
      RECT 798.44 0.84 798.72 783.16 ;
      RECT 800.68 0.84 800.96 783.16 ;
      RECT 802.92 0.84 803.2 783.16 ;
      RECT 805.16 0.84 805.44 783.16 ;
      RECT 807.4 0.84 807.68 783.16 ;
      RECT 809.64 0.84 809.92 783.16 ;
      RECT 811.88 0.84 812.16 783.16 ;
      RECT 814.12 0.84 814.4 783.16 ;
      RECT 816.36 0.84 816.64 783.16 ;
      RECT 818.6 0.84 818.88 783.16 ;
      RECT 820.84 0.84 821.12 783.16 ;
      RECT 823.08 0.84 823.36 783.16 ;
      RECT 825.32 0.84 825.6 783.16 ;
      RECT 827.56 0.84 827.84 783.16 ;
      RECT 829.8 0.84 830.08 783.16 ;
      RECT 832.04 0.84 832.32 783.16 ;
      RECT 834.28 0.84 834.56 783.16 ;
      RECT 836.52 0.84 836.8 783.16 ;
      RECT 838.76 0.84 839.04 783.16 ;
      RECT 841 0.84 841.28 783.16 ;
      RECT 843.24 0.84 843.52 783.16 ;
      RECT 845.48 0.84 845.76 783.16 ;
      RECT 847.72 0.84 848 783.16 ;
      RECT 849.96 0.84 850.24 783.16 ;
      RECT 852.2 0.84 852.48 783.16 ;
      RECT 854.44 0.84 854.72 783.16 ;
      RECT 856.68 0.84 856.96 783.16 ;
      RECT 858.92 0.84 859.2 783.16 ;
      RECT 861.16 0.84 861.44 783.16 ;
      RECT 863.4 0.84 863.68 783.16 ;
      RECT 865.64 0.84 865.92 783.16 ;
      RECT 867.88 0.84 868.16 783.16 ;
      RECT 870.12 0.84 870.4 783.16 ;
      RECT 872.36 0.84 872.64 783.16 ;
      RECT 874.6 0.84 874.88 783.16 ;
      RECT 876.84 0.84 877.12 783.16 ;
      RECT 879.08 0.84 879.36 783.16 ;
      RECT 881.32 0.84 881.6 783.16 ;
      RECT 883.56 0.84 883.84 783.16 ;
      RECT 885.8 0.84 886.08 783.16 ;
      RECT 888.04 0.84 888.32 783.16 ;
      RECT 890.28 0.84 890.56 783.16 ;
      RECT 892.52 0.84 892.8 783.16 ;
      RECT 894.76 0.84 895.04 783.16 ;
      RECT 897 0.84 897.28 783.16 ;
      RECT 899.24 0.84 899.52 783.16 ;
      RECT 901.48 0.84 901.76 783.16 ;
      RECT 903.72 0.84 904 783.16 ;
      RECT 905.96 0.84 906.24 783.16 ;
    END
  END VSS
  PIN VDD
    DIRECTION INOUT ;
    USE POWER ;
    PORT
      LAYER M4_m ;
      RECT 2.12 0.84 2.4 783.16 ;
      RECT 4.36 0.84 4.64 783.16 ;
      RECT 6.6 0.84 6.88 783.16 ;
      RECT 8.84 0.84 9.12 783.16 ;
      RECT 11.08 0.84 11.36 783.16 ;
      RECT 13.32 0.84 13.6 783.16 ;
      RECT 15.56 0.84 15.84 783.16 ;
      RECT 17.8 0.84 18.08 783.16 ;
      RECT 20.04 0.84 20.32 783.16 ;
      RECT 22.28 0.84 22.56 783.16 ;
      RECT 24.52 0.84 24.8 783.16 ;
      RECT 26.76 0.84 27.04 783.16 ;
      RECT 29 0.84 29.28 783.16 ;
      RECT 31.24 0.84 31.52 783.16 ;
      RECT 33.48 0.84 33.76 783.16 ;
      RECT 35.72 0.84 36 783.16 ;
      RECT 37.96 0.84 38.24 783.16 ;
      RECT 40.2 0.84 40.48 783.16 ;
      RECT 42.44 0.84 42.72 783.16 ;
      RECT 44.68 0.84 44.96 783.16 ;
      RECT 46.92 0.84 47.2 783.16 ;
      RECT 49.16 0.84 49.44 783.16 ;
      RECT 51.4 0.84 51.68 783.16 ;
      RECT 53.64 0.84 53.92 783.16 ;
      RECT 55.88 0.84 56.16 783.16 ;
      RECT 58.12 0.84 58.4 783.16 ;
      RECT 60.36 0.84 60.64 783.16 ;
      RECT 62.6 0.84 62.88 783.16 ;
      RECT 64.84 0.84 65.12 783.16 ;
      RECT 67.08 0.84 67.36 783.16 ;
      RECT 69.32 0.84 69.6 783.16 ;
      RECT 71.56 0.84 71.84 783.16 ;
      RECT 73.8 0.84 74.08 783.16 ;
      RECT 76.04 0.84 76.32 783.16 ;
      RECT 78.28 0.84 78.56 783.16 ;
      RECT 80.52 0.84 80.8 783.16 ;
      RECT 82.76 0.84 83.04 783.16 ;
      RECT 85 0.84 85.28 783.16 ;
      RECT 87.24 0.84 87.52 783.16 ;
      RECT 89.48 0.84 89.76 783.16 ;
      RECT 91.72 0.84 92 783.16 ;
      RECT 93.96 0.84 94.24 783.16 ;
      RECT 96.2 0.84 96.48 783.16 ;
      RECT 98.44 0.84 98.72 783.16 ;
      RECT 100.68 0.84 100.96 783.16 ;
      RECT 102.92 0.84 103.2 783.16 ;
      RECT 105.16 0.84 105.44 783.16 ;
      RECT 107.4 0.84 107.68 783.16 ;
      RECT 109.64 0.84 109.92 783.16 ;
      RECT 111.88 0.84 112.16 783.16 ;
      RECT 114.12 0.84 114.4 783.16 ;
      RECT 116.36 0.84 116.64 783.16 ;
      RECT 118.6 0.84 118.88 783.16 ;
      RECT 120.84 0.84 121.12 783.16 ;
      RECT 123.08 0.84 123.36 783.16 ;
      RECT 125.32 0.84 125.6 783.16 ;
      RECT 127.56 0.84 127.84 783.16 ;
      RECT 129.8 0.84 130.08 783.16 ;
      RECT 132.04 0.84 132.32 783.16 ;
      RECT 134.28 0.84 134.56 783.16 ;
      RECT 136.52 0.84 136.8 783.16 ;
      RECT 138.76 0.84 139.04 783.16 ;
      RECT 141 0.84 141.28 783.16 ;
      RECT 143.24 0.84 143.52 783.16 ;
      RECT 145.48 0.84 145.76 783.16 ;
      RECT 147.72 0.84 148 783.16 ;
      RECT 149.96 0.84 150.24 783.16 ;
      RECT 152.2 0.84 152.48 783.16 ;
      RECT 154.44 0.84 154.72 783.16 ;
      RECT 156.68 0.84 156.96 783.16 ;
      RECT 158.92 0.84 159.2 783.16 ;
      RECT 161.16 0.84 161.44 783.16 ;
      RECT 163.4 0.84 163.68 783.16 ;
      RECT 165.64 0.84 165.92 783.16 ;
      RECT 167.88 0.84 168.16 783.16 ;
      RECT 170.12 0.84 170.4 783.16 ;
      RECT 172.36 0.84 172.64 783.16 ;
      RECT 174.6 0.84 174.88 783.16 ;
      RECT 176.84 0.84 177.12 783.16 ;
      RECT 179.08 0.84 179.36 783.16 ;
      RECT 181.32 0.84 181.6 783.16 ;
      RECT 183.56 0.84 183.84 783.16 ;
      RECT 185.8 0.84 186.08 783.16 ;
      RECT 188.04 0.84 188.32 783.16 ;
      RECT 190.28 0.84 190.56 783.16 ;
      RECT 192.52 0.84 192.8 783.16 ;
      RECT 194.76 0.84 195.04 783.16 ;
      RECT 197 0.84 197.28 783.16 ;
      RECT 199.24 0.84 199.52 783.16 ;
      RECT 201.48 0.84 201.76 783.16 ;
      RECT 203.72 0.84 204 783.16 ;
      RECT 205.96 0.84 206.24 783.16 ;
      RECT 208.2 0.84 208.48 783.16 ;
      RECT 210.44 0.84 210.72 783.16 ;
      RECT 212.68 0.84 212.96 783.16 ;
      RECT 214.92 0.84 215.2 783.16 ;
      RECT 217.16 0.84 217.44 783.16 ;
      RECT 219.4 0.84 219.68 783.16 ;
      RECT 221.64 0.84 221.92 783.16 ;
      RECT 223.88 0.84 224.16 783.16 ;
      RECT 226.12 0.84 226.4 783.16 ;
      RECT 228.36 0.84 228.64 783.16 ;
      RECT 230.6 0.84 230.88 783.16 ;
      RECT 232.84 0.84 233.12 783.16 ;
      RECT 235.08 0.84 235.36 783.16 ;
      RECT 237.32 0.84 237.6 783.16 ;
      RECT 239.56 0.84 239.84 783.16 ;
      RECT 241.8 0.84 242.08 783.16 ;
      RECT 244.04 0.84 244.32 783.16 ;
      RECT 246.28 0.84 246.56 783.16 ;
      RECT 248.52 0.84 248.8 783.16 ;
      RECT 250.76 0.84 251.04 783.16 ;
      RECT 253 0.84 253.28 783.16 ;
      RECT 255.24 0.84 255.52 783.16 ;
      RECT 257.48 0.84 257.76 783.16 ;
      RECT 259.72 0.84 260 783.16 ;
      RECT 261.96 0.84 262.24 783.16 ;
      RECT 264.2 0.84 264.48 783.16 ;
      RECT 266.44 0.84 266.72 783.16 ;
      RECT 268.68 0.84 268.96 783.16 ;
      RECT 270.92 0.84 271.2 783.16 ;
      RECT 273.16 0.84 273.44 783.16 ;
      RECT 275.4 0.84 275.68 783.16 ;
      RECT 277.64 0.84 277.92 783.16 ;
      RECT 279.88 0.84 280.16 783.16 ;
      RECT 282.12 0.84 282.4 783.16 ;
      RECT 284.36 0.84 284.64 783.16 ;
      RECT 286.6 0.84 286.88 783.16 ;
      RECT 288.84 0.84 289.12 783.16 ;
      RECT 291.08 0.84 291.36 783.16 ;
      RECT 293.32 0.84 293.6 783.16 ;
      RECT 295.56 0.84 295.84 783.16 ;
      RECT 297.8 0.84 298.08 783.16 ;
      RECT 300.04 0.84 300.32 783.16 ;
      RECT 302.28 0.84 302.56 783.16 ;
      RECT 304.52 0.84 304.8 783.16 ;
      RECT 306.76 0.84 307.04 783.16 ;
      RECT 309 0.84 309.28 783.16 ;
      RECT 311.24 0.84 311.52 783.16 ;
      RECT 313.48 0.84 313.76 783.16 ;
      RECT 315.72 0.84 316 783.16 ;
      RECT 317.96 0.84 318.24 783.16 ;
      RECT 320.2 0.84 320.48 783.16 ;
      RECT 322.44 0.84 322.72 783.16 ;
      RECT 324.68 0.84 324.96 783.16 ;
      RECT 326.92 0.84 327.2 783.16 ;
      RECT 329.16 0.84 329.44 783.16 ;
      RECT 331.4 0.84 331.68 783.16 ;
      RECT 333.64 0.84 333.92 783.16 ;
      RECT 335.88 0.84 336.16 783.16 ;
      RECT 338.12 0.84 338.4 783.16 ;
      RECT 340.36 0.84 340.64 783.16 ;
      RECT 342.6 0.84 342.88 783.16 ;
      RECT 344.84 0.84 345.12 783.16 ;
      RECT 347.08 0.84 347.36 783.16 ;
      RECT 349.32 0.84 349.6 783.16 ;
      RECT 351.56 0.84 351.84 783.16 ;
      RECT 353.8 0.84 354.08 783.16 ;
      RECT 356.04 0.84 356.32 783.16 ;
      RECT 358.28 0.84 358.56 783.16 ;
      RECT 360.52 0.84 360.8 783.16 ;
      RECT 362.76 0.84 363.04 783.16 ;
      RECT 365 0.84 365.28 783.16 ;
      RECT 367.24 0.84 367.52 783.16 ;
      RECT 369.48 0.84 369.76 783.16 ;
      RECT 371.72 0.84 372 783.16 ;
      RECT 373.96 0.84 374.24 783.16 ;
      RECT 376.2 0.84 376.48 783.16 ;
      RECT 378.44 0.84 378.72 783.16 ;
      RECT 380.68 0.84 380.96 783.16 ;
      RECT 382.92 0.84 383.2 783.16 ;
      RECT 385.16 0.84 385.44 783.16 ;
      RECT 387.4 0.84 387.68 783.16 ;
      RECT 389.64 0.84 389.92 783.16 ;
      RECT 391.88 0.84 392.16 783.16 ;
      RECT 394.12 0.84 394.4 783.16 ;
      RECT 396.36 0.84 396.64 783.16 ;
      RECT 398.6 0.84 398.88 783.16 ;
      RECT 400.84 0.84 401.12 783.16 ;
      RECT 403.08 0.84 403.36 783.16 ;
      RECT 405.32 0.84 405.6 783.16 ;
      RECT 407.56 0.84 407.84 783.16 ;
      RECT 409.8 0.84 410.08 783.16 ;
      RECT 412.04 0.84 412.32 783.16 ;
      RECT 414.28 0.84 414.56 783.16 ;
      RECT 416.52 0.84 416.8 783.16 ;
      RECT 418.76 0.84 419.04 783.16 ;
      RECT 421 0.84 421.28 783.16 ;
      RECT 423.24 0.84 423.52 783.16 ;
      RECT 425.48 0.84 425.76 783.16 ;
      RECT 427.72 0.84 428 783.16 ;
      RECT 429.96 0.84 430.24 783.16 ;
      RECT 432.2 0.84 432.48 783.16 ;
      RECT 434.44 0.84 434.72 783.16 ;
      RECT 436.68 0.84 436.96 783.16 ;
      RECT 438.92 0.84 439.2 783.16 ;
      RECT 441.16 0.84 441.44 783.16 ;
      RECT 443.4 0.84 443.68 783.16 ;
      RECT 445.64 0.84 445.92 783.16 ;
      RECT 447.88 0.84 448.16 783.16 ;
      RECT 450.12 0.84 450.4 783.16 ;
      RECT 452.36 0.84 452.64 783.16 ;
      RECT 454.6 0.84 454.88 783.16 ;
      RECT 456.84 0.84 457.12 783.16 ;
      RECT 459.08 0.84 459.36 783.16 ;
      RECT 461.32 0.84 461.6 783.16 ;
      RECT 463.56 0.84 463.84 783.16 ;
      RECT 465.8 0.84 466.08 783.16 ;
      RECT 468.04 0.84 468.32 783.16 ;
      RECT 470.28 0.84 470.56 783.16 ;
      RECT 472.52 0.84 472.8 783.16 ;
      RECT 474.76 0.84 475.04 783.16 ;
      RECT 477 0.84 477.28 783.16 ;
      RECT 479.24 0.84 479.52 783.16 ;
      RECT 481.48 0.84 481.76 783.16 ;
      RECT 483.72 0.84 484 783.16 ;
      RECT 485.96 0.84 486.24 783.16 ;
      RECT 488.2 0.84 488.48 783.16 ;
      RECT 490.44 0.84 490.72 783.16 ;
      RECT 492.68 0.84 492.96 783.16 ;
      RECT 494.92 0.84 495.2 783.16 ;
      RECT 497.16 0.84 497.44 783.16 ;
      RECT 499.4 0.84 499.68 783.16 ;
      RECT 501.64 0.84 501.92 783.16 ;
      RECT 503.88 0.84 504.16 783.16 ;
      RECT 506.12 0.84 506.4 783.16 ;
      RECT 508.36 0.84 508.64 783.16 ;
      RECT 510.6 0.84 510.88 783.16 ;
      RECT 512.84 0.84 513.12 783.16 ;
      RECT 515.08 0.84 515.36 783.16 ;
      RECT 517.32 0.84 517.6 783.16 ;
      RECT 519.56 0.84 519.84 783.16 ;
      RECT 521.8 0.84 522.08 783.16 ;
      RECT 524.04 0.84 524.32 783.16 ;
      RECT 526.28 0.84 526.56 783.16 ;
      RECT 528.52 0.84 528.8 783.16 ;
      RECT 530.76 0.84 531.04 783.16 ;
      RECT 533 0.84 533.28 783.16 ;
      RECT 535.24 0.84 535.52 783.16 ;
      RECT 537.48 0.84 537.76 783.16 ;
      RECT 539.72 0.84 540 783.16 ;
      RECT 541.96 0.84 542.24 783.16 ;
      RECT 544.2 0.84 544.48 783.16 ;
      RECT 546.44 0.84 546.72 783.16 ;
      RECT 548.68 0.84 548.96 783.16 ;
      RECT 550.92 0.84 551.2 783.16 ;
      RECT 553.16 0.84 553.44 783.16 ;
      RECT 555.4 0.84 555.68 783.16 ;
      RECT 557.64 0.84 557.92 783.16 ;
      RECT 559.88 0.84 560.16 783.16 ;
      RECT 562.12 0.84 562.4 783.16 ;
      RECT 564.36 0.84 564.64 783.16 ;
      RECT 566.6 0.84 566.88 783.16 ;
      RECT 568.84 0.84 569.12 783.16 ;
      RECT 571.08 0.84 571.36 783.16 ;
      RECT 573.32 0.84 573.6 783.16 ;
      RECT 575.56 0.84 575.84 783.16 ;
      RECT 577.8 0.84 578.08 783.16 ;
      RECT 580.04 0.84 580.32 783.16 ;
      RECT 582.28 0.84 582.56 783.16 ;
      RECT 584.52 0.84 584.8 783.16 ;
      RECT 586.76 0.84 587.04 783.16 ;
      RECT 589 0.84 589.28 783.16 ;
      RECT 591.24 0.84 591.52 783.16 ;
      RECT 593.48 0.84 593.76 783.16 ;
      RECT 595.72 0.84 596 783.16 ;
      RECT 597.96 0.84 598.24 783.16 ;
      RECT 600.2 0.84 600.48 783.16 ;
      RECT 602.44 0.84 602.72 783.16 ;
      RECT 604.68 0.84 604.96 783.16 ;
      RECT 606.92 0.84 607.2 783.16 ;
      RECT 609.16 0.84 609.44 783.16 ;
      RECT 611.4 0.84 611.68 783.16 ;
      RECT 613.64 0.84 613.92 783.16 ;
      RECT 615.88 0.84 616.16 783.16 ;
      RECT 618.12 0.84 618.4 783.16 ;
      RECT 620.36 0.84 620.64 783.16 ;
      RECT 622.6 0.84 622.88 783.16 ;
      RECT 624.84 0.84 625.12 783.16 ;
      RECT 627.08 0.84 627.36 783.16 ;
      RECT 629.32 0.84 629.6 783.16 ;
      RECT 631.56 0.84 631.84 783.16 ;
      RECT 633.8 0.84 634.08 783.16 ;
      RECT 636.04 0.84 636.32 783.16 ;
      RECT 638.28 0.84 638.56 783.16 ;
      RECT 640.52 0.84 640.8 783.16 ;
      RECT 642.76 0.84 643.04 783.16 ;
      RECT 645 0.84 645.28 783.16 ;
      RECT 647.24 0.84 647.52 783.16 ;
      RECT 649.48 0.84 649.76 783.16 ;
      RECT 651.72 0.84 652 783.16 ;
      RECT 653.96 0.84 654.24 783.16 ;
      RECT 656.2 0.84 656.48 783.16 ;
      RECT 658.44 0.84 658.72 783.16 ;
      RECT 660.68 0.84 660.96 783.16 ;
      RECT 662.92 0.84 663.2 783.16 ;
      RECT 665.16 0.84 665.44 783.16 ;
      RECT 667.4 0.84 667.68 783.16 ;
      RECT 669.64 0.84 669.92 783.16 ;
      RECT 671.88 0.84 672.16 783.16 ;
      RECT 674.12 0.84 674.4 783.16 ;
      RECT 676.36 0.84 676.64 783.16 ;
      RECT 678.6 0.84 678.88 783.16 ;
      RECT 680.84 0.84 681.12 783.16 ;
      RECT 683.08 0.84 683.36 783.16 ;
      RECT 685.32 0.84 685.6 783.16 ;
      RECT 687.56 0.84 687.84 783.16 ;
      RECT 689.8 0.84 690.08 783.16 ;
      RECT 692.04 0.84 692.32 783.16 ;
      RECT 694.28 0.84 694.56 783.16 ;
      RECT 696.52 0.84 696.8 783.16 ;
      RECT 698.76 0.84 699.04 783.16 ;
      RECT 701 0.84 701.28 783.16 ;
      RECT 703.24 0.84 703.52 783.16 ;
      RECT 705.48 0.84 705.76 783.16 ;
      RECT 707.72 0.84 708 783.16 ;
      RECT 709.96 0.84 710.24 783.16 ;
      RECT 712.2 0.84 712.48 783.16 ;
      RECT 714.44 0.84 714.72 783.16 ;
      RECT 716.68 0.84 716.96 783.16 ;
      RECT 718.92 0.84 719.2 783.16 ;
      RECT 721.16 0.84 721.44 783.16 ;
      RECT 723.4 0.84 723.68 783.16 ;
      RECT 725.64 0.84 725.92 783.16 ;
      RECT 727.88 0.84 728.16 783.16 ;
      RECT 730.12 0.84 730.4 783.16 ;
      RECT 732.36 0.84 732.64 783.16 ;
      RECT 734.6 0.84 734.88 783.16 ;
      RECT 736.84 0.84 737.12 783.16 ;
      RECT 739.08 0.84 739.36 783.16 ;
      RECT 741.32 0.84 741.6 783.16 ;
      RECT 743.56 0.84 743.84 783.16 ;
      RECT 745.8 0.84 746.08 783.16 ;
      RECT 748.04 0.84 748.32 783.16 ;
      RECT 750.28 0.84 750.56 783.16 ;
      RECT 752.52 0.84 752.8 783.16 ;
      RECT 754.76 0.84 755.04 783.16 ;
      RECT 757 0.84 757.28 783.16 ;
      RECT 759.24 0.84 759.52 783.16 ;
      RECT 761.48 0.84 761.76 783.16 ;
      RECT 763.72 0.84 764 783.16 ;
      RECT 765.96 0.84 766.24 783.16 ;
      RECT 768.2 0.84 768.48 783.16 ;
      RECT 770.44 0.84 770.72 783.16 ;
      RECT 772.68 0.84 772.96 783.16 ;
      RECT 774.92 0.84 775.2 783.16 ;
      RECT 777.16 0.84 777.44 783.16 ;
      RECT 779.4 0.84 779.68 783.16 ;
      RECT 781.64 0.84 781.92 783.16 ;
      RECT 783.88 0.84 784.16 783.16 ;
      RECT 786.12 0.84 786.4 783.16 ;
      RECT 788.36 0.84 788.64 783.16 ;
      RECT 790.6 0.84 790.88 783.16 ;
      RECT 792.84 0.84 793.12 783.16 ;
      RECT 795.08 0.84 795.36 783.16 ;
      RECT 797.32 0.84 797.6 783.16 ;
      RECT 799.56 0.84 799.84 783.16 ;
      RECT 801.8 0.84 802.08 783.16 ;
      RECT 804.04 0.84 804.32 783.16 ;
      RECT 806.28 0.84 806.56 783.16 ;
      RECT 808.52 0.84 808.8 783.16 ;
      RECT 810.76 0.84 811.04 783.16 ;
      RECT 813 0.84 813.28 783.16 ;
      RECT 815.24 0.84 815.52 783.16 ;
      RECT 817.48 0.84 817.76 783.16 ;
      RECT 819.72 0.84 820 783.16 ;
      RECT 821.96 0.84 822.24 783.16 ;
      RECT 824.2 0.84 824.48 783.16 ;
      RECT 826.44 0.84 826.72 783.16 ;
      RECT 828.68 0.84 828.96 783.16 ;
      RECT 830.92 0.84 831.2 783.16 ;
      RECT 833.16 0.84 833.44 783.16 ;
      RECT 835.4 0.84 835.68 783.16 ;
      RECT 837.64 0.84 837.92 783.16 ;
      RECT 839.88 0.84 840.16 783.16 ;
      RECT 842.12 0.84 842.4 783.16 ;
      RECT 844.36 0.84 844.64 783.16 ;
      RECT 846.6 0.84 846.88 783.16 ;
      RECT 848.84 0.84 849.12 783.16 ;
      RECT 851.08 0.84 851.36 783.16 ;
      RECT 853.32 0.84 853.6 783.16 ;
      RECT 855.56 0.84 855.84 783.16 ;
      RECT 857.8 0.84 858.08 783.16 ;
      RECT 860.04 0.84 860.32 783.16 ;
      RECT 862.28 0.84 862.56 783.16 ;
      RECT 864.52 0.84 864.8 783.16 ;
      RECT 866.76 0.84 867.04 783.16 ;
      RECT 869 0.84 869.28 783.16 ;
      RECT 871.24 0.84 871.52 783.16 ;
      RECT 873.48 0.84 873.76 783.16 ;
      RECT 875.72 0.84 876 783.16 ;
      RECT 877.96 0.84 878.24 783.16 ;
      RECT 880.2 0.84 880.48 783.16 ;
      RECT 882.44 0.84 882.72 783.16 ;
      RECT 884.68 0.84 884.96 783.16 ;
      RECT 886.92 0.84 887.2 783.16 ;
      RECT 889.16 0.84 889.44 783.16 ;
      RECT 891.4 0.84 891.68 783.16 ;
      RECT 893.64 0.84 893.92 783.16 ;
      RECT 895.88 0.84 896.16 783.16 ;
      RECT 898.12 0.84 898.4 783.16 ;
      RECT 900.36 0.84 900.64 783.16 ;
      RECT 902.6 0.84 902.88 783.16 ;
      RECT 904.84 0.84 905.12 783.16 ;
    END
  END VDD
  OBS
    LAYER M1_m ;
    RECT 0 0 906.3 784 ;
    LAYER M2_m ;
    RECT 0 0 906.3 784 ;
  END
END ht45_rocketgemmini_mem_0_ext_upper

END LIBRARY
